# 
# LEF OUT 
# User Name : spalutla 
# Date : Tue Mar 31 10:02:19 2015
# 
VERSION 5.5 ;
NAMESCASESENSITIVE ON ;
BUSBITCHARS "[]" ;
DIVIDERCHAR "/" ;

UNITS
  DATABASE MICRONS 1000 ;
END UNITS
MANUFACTURINGGRID 0.001 ;

LAYER poly
  TYPE MASTERSLICE ;
END poly

LAYER tcn
  TYPE MASTERSLICE ;
END tcn

LAYER marker
  TYPE MASTERSLICE ;
END marker

LAYER ptpdrawn
  TYPE MASTERSLICE ;
END ptpdrawn

LAYER nwell
  TYPE MASTERSLICE ;
END nwell

LAYER nsddrawn
  TYPE MASTERSLICE ;
END nsddrawn

LAYER psddrawn
  TYPE MASTERSLICE ;
END psddrawn

LAYER resdrawn
  TYPE MASTERSLICE ;
END resdrawn

LAYER nwellesddrawn
  TYPE MASTERSLICE ;
END nwellesddrawn

LAYER deepnwelldrawn
  TYPE MASTERSLICE ;
END deepnwelldrawn

LAYER tgoxiddrawn
  TYPE MASTERSLICE ;
END tgoxiddrawn

LAYER esddrawn
  TYPE MASTERSLICE ;
END esddrawn

LAYER mresistordrawn
  TYPE MASTERSLICE ;
END mresistordrawn

LAYER ulndrawn
  TYPE MASTERSLICE ;
END ulndrawn

LAYER ulpdrawn
  TYPE MASTERSLICE ;
END ulpdrawn

LAYER llndrawn
  TYPE MASTERSLICE ;
END llndrawn

LAYER llpdrawn
  TYPE MASTERSLICE ;
END llpdrawn

LAYER via10drawn
  TYPE MASTERSLICE ;
END via10drawn

LAYER dummy54
  TYPE MASTERSLICE ;
END dummy54

LAYER via11drawn
  TYPE MASTERSLICE ;
END via11drawn

LAYER metal11drawn
  TYPE MASTERSLICE ;
END metal11drawn

LAYER noprot
  TYPE MASTERSLICE ;
END noprot

LAYER tv2drawn
  TYPE MASTERSLICE ;
END tv2drawn

LAYER tm2drawn
  TYPE MASTERSLICE ;
END tm2drawn

LAYER txrdrawn
  TYPE MASTERSLICE ;
END txrdrawn

LAYER m1pgdrawn
  TYPE MASTERSLICE ;
END m1pgdrawn

LAYER m2pgdrawn
  TYPE MASTERSLICE ;
END m2pgdrawn

LAYER m3pgdrawn
  TYPE MASTERSLICE ;
END m3pgdrawn

LAYER ce3drawn
  TYPE MASTERSLICE ;
END ce3drawn

LAYER dummy81
  TYPE MASTERSLICE ;
END dummy81

LAYER sram_iddrawn
  TYPE MASTERSLICE ;
END sram_iddrawn

LAYER dummy83
  TYPE MASTERSLICE ;
END dummy83

LAYER polycheckdrawn
  TYPE MASTERSLICE ;
END polycheckdrawn

LAYER prmdrawn
  TYPE MASTERSLICE ;
END prmdrawn

LAYER rctdrawn
  TYPE MASTERSLICE ;
END rctdrawn

LAYER cptdrawn
  TYPE MASTERSLICE ;
END cptdrawn

LAYER cobdrawn
  TYPE MASTERSLICE ;
END cobdrawn

LAYER cbpdrawn
  TYPE MASTERSLICE ;
END cbpdrawn

LAYER ce2
  TYPE MASTERSLICE ;
END ce2

LAYER ce1
  TYPE MASTERSLICE ;
END ce1

LAYER cbvdrawn
  TYPE MASTERSLICE ;
END cbvdrawn

LAYER nv1drawn
  TYPE MASTERSLICE ;
END nv1drawn

LAYER pv1drawn
  TYPE MASTERSLICE ;
END pv1drawn

LAYER nv2drawn
  TYPE MASTERSLICE ;
END nv2drawn

LAYER pv2drawn
  TYPE MASTERSLICE ;
END pv2drawn

LAYER pv3drawn
  TYPE MASTERSLICE ;
END pv3drawn

LAYER nv3drawn
  TYPE MASTERSLICE ;
END nv3drawn

LAYER tnwdrawn
  TYPE MASTERSLICE ;
END tnwdrawn

LAYER tpwdrawn
  TYPE MASTERSLICE ;
END tpwdrawn

LAYER diffusiondrawn
  TYPE MASTERSLICE ;
END diffusiondrawn

LAYER pwelldrawn
  TYPE MASTERSLICE ;
END pwelldrawn

LAYER metalc1drawn
  TYPE MASTERSLICE ;
END metalc1drawn

LAYER metalc2drawn
  TYPE MASTERSLICE ;
END metalc2drawn

LAYER metalc3drawn
  TYPE MASTERSLICE ;
END metalc3drawn

LAYER metalc4drawn
  TYPE MASTERSLICE ;
END metalc4drawn

LAYER metalc5drawn
  TYPE MASTERSLICE ;
END metalc5drawn

LAYER dummy126
  TYPE MASTERSLICE ;
END dummy126

LAYER tntdrawn
  TYPE MASTERSLICE ;
END tntdrawn

LAYER tptdrawn
  TYPE MASTERSLICE ;
END tptdrawn

LAYER nu1drawn
  TYPE MASTERSLICE ;
END nu1drawn

LAYER pu1drawn
  TYPE MASTERSLICE ;
END pu1drawn

LAYER thxdrawn
  TYPE MASTERSLICE ;
END thxdrawn

LAYER xntdrawn
  TYPE MASTERSLICE ;
END xntdrawn

LAYER xptdrawn
  TYPE MASTERSLICE ;
END xptdrawn

LAYER xhxdrawn
  TYPE MASTERSLICE ;
END xhxdrawn

LAYER ulldrawn
  TYPE MASTERSLICE ;
END ulldrawn

LAYER naldrawn
  TYPE MASTERSLICE ;
END naldrawn

LAYER paldrawn
  TYPE MASTERSLICE ;
END paldrawn

LAYER dvndrawn
  TYPE MASTERSLICE ;
END dvndrawn

LAYER bgddrawn
  TYPE MASTERSLICE ;
END bgddrawn

LAYER dvpdrawn
  TYPE MASTERSLICE ;
END dvpdrawn

LAYER hvgdrawn
  TYPE MASTERSLICE ;
END hvgdrawn

LAYER dmgdrawn
  TYPE MASTERSLICE ;
END dmgdrawn

LAYER nmgdrawn
  TYPE MASTERSLICE ;
END nmgdrawn

LAYER pmgdrawn
  TYPE MASTERSLICE ;
END pmgdrawn

LAYER svndrawn
  TYPE MASTERSLICE ;
END svndrawn

LAYER svpdrawn
  TYPE MASTERSLICE ;
END svpdrawn

LAYER nesdrawn
  TYPE MASTERSLICE ;
END nesdrawn

LAYER doxdrawn
  TYPE MASTERSLICE ;
END doxdrawn

LAYER evndrawn
  TYPE MASTERSLICE ;
END evndrawn

LAYER tcalignmentdrawn
  TYPE MASTERSLICE ;
END tcalignmentdrawn

LAYER reidrawn
  TYPE MASTERSLICE ;
END reidrawn

LAYER xvndrawn
  TYPE MASTERSLICE ;
END xvndrawn

LAYER ag3drawn
  TYPE MASTERSLICE ;
END ag3drawn

LAYER tcnpdrawn
  TYPE MASTERSLICE ;
END tcnpdrawn

LAYER pladrawn
  TYPE MASTERSLICE ;
END pladrawn

LAYER c4tdrawn
  TYPE MASTERSLICE ;
END c4tdrawn

LAYER c4edrawn
  TYPE MASTERSLICE ;
END c4edrawn

LAYER zerothdrawn
  TYPE MASTERSLICE ;
END zerothdrawn

LAYER raddrawn
  TYPE MASTERSLICE ;
END raddrawn

LAYER ag2drawn
  TYPE MASTERSLICE ;
END ag2drawn

LAYER ag5drawn
  TYPE MASTERSLICE ;
END ag5drawn

LAYER gcn
  TYPE MASTERSLICE ;
END gcn

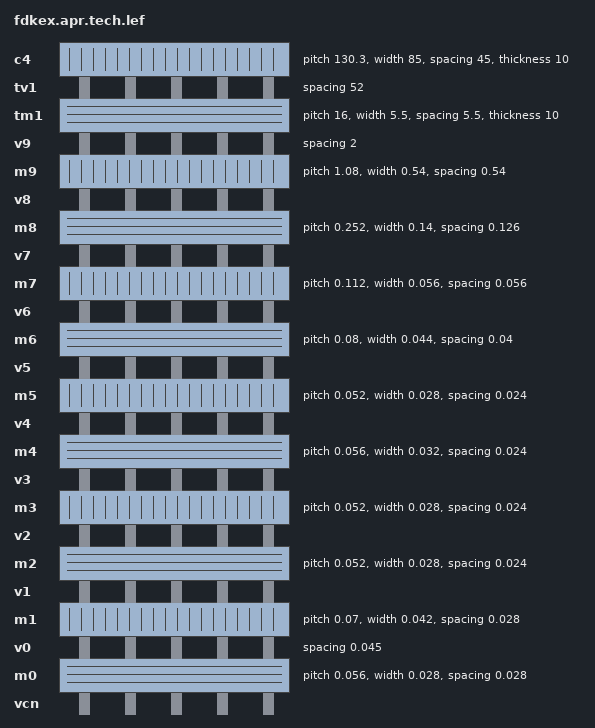
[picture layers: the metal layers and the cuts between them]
LAYER vcn
  TYPE CUT ;
END vcn

LAYER m0
  TYPE ROUTING ;
  DIRECTION HORIZONTAL ;
  PITCH 0.056 ;
  WIDTH 0.028 ;
  SPACING 0.028 ;
  MINWIDTH 0.028 ;
  CAPMULTIPLIER 1 ;
END m0

LAYER v0
  TYPE CUT ;
  SPACING 0.045 ADJACENTCUTS 3 WITHIN 0.045 ;
END v0

LAYER m1
  TYPE ROUTING ;
  DIRECTION VERTICAL ;
  PITCH 0.07 ;
  WIDTH 0.042 ;
  SPACING 0.028 ;
  MINWIDTH 0.042 ;
  CAPMULTIPLIER 1 ;
END m1

LAYER v1
  TYPE CUT ;
END v1

LAYER m2
  TYPE ROUTING ;
  DIRECTION HORIZONTAL ;
  PITCH 0.052 ;
  WIDTH 0.028 ;
  SPACING 0.024 ;
  MINWIDTH 0.028 ;
  CAPMULTIPLIER 1 ;
END m2

LAYER v2
  TYPE CUT ;
END v2

LAYER m3
  TYPE ROUTING ;
  DIRECTION VERTICAL ;
  PITCH 0.052 ;
  WIDTH 0.028 ;
  SPACING 0.024 ;
  MINWIDTH 0.028 ;
  CAPMULTIPLIER 1 ;
END m3

LAYER v3
  TYPE CUT ;
END v3

LAYER m4
  TYPE ROUTING ;
  DIRECTION HORIZONTAL ;
  PITCH 0.056 ;
  WIDTH 0.032 ;
  SPACING 0.024 ;
  MINWIDTH 0.028 ;
  CAPMULTIPLIER 1 ;
END m4

LAYER v4
  TYPE CUT ;
END v4

LAYER m5
  TYPE ROUTING ;
  DIRECTION VERTICAL ;
  PITCH 0.052 ;
  WIDTH 0.028 ;
  SPACING 0.024 ;
  MINWIDTH 0.028 ;
  CAPMULTIPLIER 1 ;
END m5

LAYER v5
  TYPE CUT ;
END v5

LAYER m6
  TYPE ROUTING ;
  DIRECTION HORIZONTAL ;
  PITCH 0.08 ;
  WIDTH 0.044 ;
  SPACING 0.04 ;
  MINWIDTH 0.04 ;
  CAPMULTIPLIER 1 ;
END m6

LAYER v6
  TYPE CUT ;
END v6

LAYER m7
  TYPE ROUTING ;
  DIRECTION VERTICAL ;
  PITCH 0.112 ;
  WIDTH 0.056 ;
  SPACING 0.056 ;
  MINWIDTH 0.056 ;
  CAPMULTIPLIER 1 ;
END m7

LAYER v7
  TYPE CUT ;
END v7

LAYER m8
  TYPE ROUTING ;
  DIRECTION HORIZONTAL ;
  PITCH 0.252 ;
  WIDTH 0.14 ;
  SPACING 0.126 ;
  MINWIDTH 0.126 ;
  CAPMULTIPLIER 1 ;
END m8

LAYER v8
  TYPE CUT ;
END v8

LAYER m9
  TYPE ROUTING ;
  DIRECTION VERTICAL ;
  PITCH 1.08 ;
  WIDTH 0.54 ;
  SPACING 0.54 ;
  MINWIDTH 0.54 ;
  MINENCLOSEDAREA 2.2 ;
  CAPMULTIPLIER 1 ;
END m9

LAYER v9
  TYPE CUT ;
  SPACING 2 ;
END v9

LAYER tm1
  TYPE ROUTING ;
  DIRECTION HORIZONTAL ;
  PITCH 16 ;
  WIDTH 5.5 ;
  AREA 200 ;
  SPACING 5.5 ;
  MINWIDTH 5.5 ;
  MINENCLOSEDAREA 250 ;
  THICKNESS 10 ;
  CAPMULTIPLIER 1 ;
END tm1

LAYER tv1
  TYPE CUT ;
  SPACING 52 ;
END tv1

LAYER c4
  TYPE ROUTING ;
  DIRECTION VERTICAL ;
  PITCH 130.3 ;
  WIDTH 85 ;
  AREA 200 ;
  SPACING 45 ;
  MINWIDTH 85 ;
  THICKNESS 10 ;
  CAPMULTIPLIER 1 ;
END c4

LAYER OverlapCheck
  TYPE OVERLAP ;
END OverlapCheck
MAXVIASTACK 10 RANGE gcn c4 ;

VIA VCNAX
  DEFAULT 
  RESISTANCE 5.72 ;
  LAYER gcn ;
    RECT -0.0270 -0.0160 0.0270 0.0160 ;
  LAYER vcn ;
    RECT -0.0210 -0.0140 0.0210 0.0140 ;
  LAYER m0 ;
    RECT -0.0430 -0.0140 0.0430 0.0140 ;
END VCNAX

VIA VIA0AX
  DEFAULT 
  RESISTANCE 5.72 ;
  LAYER m0 ;
    RECT -0.0350 -0.0140 0.0350 0.0140 ;
  LAYER v0 ;
    RECT -0.0210 -0.0140 0.0210 0.0140 ;
  LAYER m1 ;
    RECT -0.0210 -0.0280 0.0210 0.0280 ;
END VIA0AX

VIA VCNB
  RESISTANCE 5.72 ;
  LAYER gcn ;
    RECT -0.0270 -0.0160 0.0270 0.0160 ;
  LAYER vcn ;
    RECT -0.0210 -0.0230 0.0210 0.0230 ;
  LAYER m0 ;
    RECT -0.0430 -0.0230 0.0430 0.0230 ;
END VCNB

VIA VIA0CX
  RESISTANCE 5.72 ;
  LAYER m0 ;
    RECT -0.0350 -0.0200 0.0350 0.0200 ;
  LAYER v0 ;
    RECT -0.0210 -0.0200 0.0210 0.0200 ;
  LAYER m1 ;
    RECT -0.0210 -0.0340 0.0210 0.0340 ;
END VIA0CX

VIA VIA1A
  DEFAULT 
  RESISTANCE 5.72 ;
  LAYER m1 ;
    RECT -0.0210 -0.0210 0.0210 0.0210 ;
  LAYER v1 ;
    RECT -0.0180 -0.0140 0.0180 0.0140 ;
  LAYER m2 ;
    RECT -0.0420 -0.0140 0.0420 0.0140 ;
END VIA1A

VIA VIA1F
  RESISTANCE 5.72 ;
  LAYER m1 ;
    RECT -0.0210 -0.0270 0.0210 0.0270 ;
  LAYER v1 ;
    RECT -0.0180 -0.0200 0.0180 0.0200 ;
  LAYER m2 ;
    RECT -0.0420 -0.0200 0.0420 0.0200 ;
END VIA1F

VIA VIA1V
  RESISTANCE 5.72 ;
  LAYER m1 ;
    RECT -0.0210 -0.0440 0.0210 0.0440 ;
  LAYER v1 ;
    RECT -0.0180 -0.0370 0.0180 0.0370 ;
  LAYER m2 ;
    RECT -0.0420 -0.0370 0.0420 0.0370 ;
END VIA1V

VIA VIA0A
  RESISTANCE 5.72 ;
  LAYER m0 ;
    RECT -0.0350 -0.0210 0.0350 0.0210 ;
  LAYER v0 ;
    RECT -0.0210 -0.0210 0.0210 0.0210 ;
  LAYER m1 ;
    RECT -0.0210 -0.0350 0.0210 0.0350 ;
END VIA0A

VIA VIA0B
  RESISTANCE 5.72 ;
  LAYER m0 ;
    RECT -0.0350 -0.0230 0.0350 0.0230 ;
  LAYER v0 ;
    RECT -0.0210 -0.0230 0.0210 0.0230 ;
  LAYER m1 ;
    RECT -0.0210 -0.0370 0.0210 0.0370 ;
END VIA0B

VIA VIA2B
  RESISTANCE 5.72 ;
  LAYER m2 ;
    RECT -0.0240 -0.0140 0.0240 0.0140 ;
  LAYER v2 ;
    RECT -0.0150 -0.0160 0.0150 0.0160 ;
  LAYER m3 ;
    RECT -0.0150 -0.0400 0.0150 0.0400 ;
END VIA2B

VIA VIA2F
  RESISTANCE 5.72 ;
  LAYER m2 ;
    RECT -0.0290 -0.0140 0.0290 0.0140 ;
  LAYER v2 ;
    RECT -0.0200 -0.0160 0.0200 0.0160 ;
  LAYER m3 ;
    RECT -0.0200 -0.0400 0.0200 0.0400 ;
END VIA2F

VIA VIA3B
  RESISTANCE 5.72 ;
  LAYER m3 ;
    RECT -0.0140 -0.0240 0.0140 0.0240 ;
  LAYER v3 ;
    RECT -0.0160 -0.0150 0.0160 0.0150 ;
  LAYER m4 ;
    RECT -0.0400 -0.0150 0.0400 0.0150 ;
END VIA3B

VIA VIA4B
  RESISTANCE 5.72 ;
  LAYER m4 ;
    RECT -0.0240 -0.0140 0.0240 0.0140 ;
  LAYER v4 ;
    RECT -0.0150 -0.0160 0.0150 0.0160 ;
  LAYER m5 ;
    RECT -0.0150 -0.0400 0.0150 0.0400 ;
END VIA4B

VIA VIA4F
  RESISTANCE 5.72 ;
  LAYER m4 ;
    RECT -0.0290 -0.0140 0.0290 0.0140 ;
  LAYER v4 ;
    RECT -0.0200 -0.0160 0.0200 0.0160 ;
  LAYER m5 ;
    RECT -0.0200 -0.0400 0.0200 0.0400 ;
END VIA4F

VIA VIA8A
  DEFAULT 
  RESISTANCE 5.72 ;
  LAYER m8 ;
    RECT -0.3500 -0.3500 0.3500 0.3500 ;
  LAYER v8 ;
    RECT -0.2200 -0.2200 0.2200 0.2200 ;
  LAYER m9 ;
    RECT -0.2700 -0.3500 0.2700 0.3500 ;
END VIA8A

VIA VIA8C
  RESISTANCE 5.72 ;
  LAYER m8 ;
    RECT -0.5200 -0.3000 0.5200 0.3000 ;
  LAYER v8 ;
    RECT -0.4400 -0.2200 0.4400 0.2200 ;
  LAYER m9 ;
    RECT -0.4900 -0.3500 0.4900 0.3500 ;
END VIA8C

VIA VIA2A
  DEFAULT 
  RESISTANCE 5.72 ;
  LAYER m2 ;
    RECT -0.0230 -0.0140 0.0230 0.0140 ;
  LAYER v2 ;
    RECT -0.0140 -0.0160 0.0140 0.0160 ;
  LAYER m3 ;
    RECT -0.0140 -0.0400 0.0140 0.0400 ;
END VIA2A

VIA VIA2L40
  RESISTANCE 5.72 ;
  LAYER m2 ;
    RECT -0.0430 -0.0200 0.0430 0.0200 ;
  LAYER v2 ;
    RECT -0.0340 -0.0160 0.0340 0.0160 ;
  LAYER m3 ;
    RECT -0.0340 -0.0400 0.0340 0.0400 ;
END VIA2L40

VIA VIA2L74
  RESISTANCE 5.72 ;
  LAYER m2 ;
    RECT -0.0430 -0.0370 0.0430 0.0370 ;
  LAYER v2 ;
    RECT -0.0340 -0.0160 0.0340 0.0160 ;
  LAYER m3 ;
    RECT -0.0340 -0.0400 0.0340 0.0400 ;
END VIA2L74

VIA VIA9A
  DEFAULT 
  RESISTANCE 5.72 ;
  LAYER m9 ;
    RECT -0.5400 -1.0650 0.5400 1.0650 ;
  LAYER v9 ;
    RECT -0.4000 -0.9250 0.4000 0.9250 ;
  LAYER tm1 ;
    RECT -3.4000 -3.9250 3.4000 3.9250 ;
END VIA9A

VIA VIA9B
  RESISTANCE 5.72 ;
  LAYER m9 ;
    RECT -0.5400 -3.8400 0.5400 3.8400 ;
  LAYER v9 ;
    RECT -0.4000 -3.7000 0.4000 3.7000 ;
  LAYER tm1 ;
    RECT -3.4000 -6.7000 3.4000 6.7000 ;
END VIA9B

VIA VIA9C
  RESISTANCE 5.72 ;
  LAYER m9 ;
    RECT -0.5400 -1.9900 0.5400 1.9900 ;
  LAYER v9 ;
    RECT -0.4000 -1.8500 0.4000 1.8500 ;
  LAYER tm1 ;
    RECT -3.4000 -4.8500 3.4000 4.8500 ;
END VIA9C

VIA VIA2S
  RESISTANCE 5.72 ;
  LAYER m2 ;
    RECT -0.0470 -0.0140 0.0470 0.0140 ;
  LAYER v2 ;
    RECT -0.0380 -0.0160 0.0380 0.0160 ;
  LAYER m3 ;
    RECT -0.0380 -0.0400 0.0380 0.0400 ;
END VIA2S

VIA VIA3A
  RESISTANCE 5.72 ;
  LAYER m3 ;
    RECT -0.0140 -0.0230 0.0140 0.0230 ;
  LAYER v3 ;
    RECT -0.0160 -0.0140 0.0160 0.0140 ;
  LAYER m4 ;
    RECT -0.0400 -0.0140 0.0400 0.0140 ;
END VIA3A

VIA VIA3F
  RESISTANCE 5.72 ;
  LAYER m3 ;
    RECT -0.0140 -0.0290 0.0140 0.0290 ;
  LAYER v3 ;
    RECT -0.0160 -0.0200 0.0160 0.0200 ;
  LAYER m4 ;
    RECT -0.0400 -0.0200 0.0400 0.0200 ;
END VIA3F

VIA VIA3RY
  RESISTANCE 5.72 ;
  LAYER m3 ;
    RECT -0.0340 -0.0390 0.0340 0.0390 ;
  LAYER v3 ;
    RECT -0.0220 -0.0300 0.0220 0.0300 ;
  LAYER m4 ;
    RECT -0.0460 -0.0300 0.0460 0.0300 ;
END VIA3RY

VIA VIA3VX
  RESISTANCE 5.72 ;
  LAYER m3 ;
    RECT -0.0340 -0.0420 0.0340 0.0420 ;
  LAYER v3 ;
    RECT -0.0200 -0.0330 0.0200 0.0330 ;
  LAYER m4 ;
    RECT -0.0440 -0.0330 0.0440 0.0330 ;
END VIA3VX

VIA VIA3NX
  RESISTANCE 5.72 ;
  LAYER m3 ;
    RECT -0.0340 -0.0460 0.0340 0.0460 ;
  LAYER v3 ;
    RECT -0.0190 -0.0370 0.0190 0.0370 ;
  LAYER m4 ;
    RECT -0.0430 -0.0370 0.0430 0.0370 ;
END VIA3NX

VIA VIA4A
  DEFAULT 
  RESISTANCE 5.72 ;
  LAYER m4 ;
    RECT -0.0230 -0.0140 0.0230 0.0140 ;
  LAYER v4 ;
    RECT -0.0140 -0.0160 0.0140 0.0160 ;
  LAYER m5 ;
    RECT -0.0140 -0.0400 0.0140 0.0400 ;
END VIA4A

VIA VIA4L40
  RESISTANCE 5.72 ;
  LAYER m4 ;
    RECT -0.0430 -0.0200 0.0430 0.0200 ;
  LAYER v4 ;
    RECT -0.0340 -0.0160 0.0340 0.0160 ;
  LAYER m5 ;
    RECT -0.0340 -0.0400 0.0340 0.0400 ;
END VIA4L40

VIA VIA4L60
  RESISTANCE 5.72 ;
  LAYER m4 ;
    RECT -0.0430 -0.0300 0.0430 0.0300 ;
  LAYER v4 ;
    RECT -0.0340 -0.0160 0.0340 0.0160 ;
  LAYER m5 ;
    RECT -0.0340 -0.0400 0.0340 0.0400 ;
END VIA4L60

VIA VIA4L66
  RESISTANCE 5.72 ;
  LAYER m4 ;
    RECT -0.0430 -0.0330 0.0430 0.0330 ;
  LAYER v4 ;
    RECT -0.0340 -0.0160 0.0340 0.0160 ;
  LAYER m5 ;
    RECT -0.0340 -0.0400 0.0340 0.0400 ;
END VIA4L66

VIA VIA4L74
  RESISTANCE 5.72 ;
  LAYER m4 ;
    RECT -0.0430 -0.0370 0.0430 0.0370 ;
  LAYER v4 ;
    RECT -0.0340 -0.0160 0.0340 0.0160 ;
  LAYER m5 ;
    RECT -0.0340 -0.0400 0.0340 0.0400 ;
END VIA4L74

VIA VIA3GX
  RESISTANCE 5.72 ;
  LAYER m3 ;
    RECT -0.0240 -0.0320 0.0240 0.0320 ;
  LAYER v3 ;
    RECT -0.0260 -0.0230 0.0260 0.0230 ;
  LAYER m4 ;
    RECT -0.0500 -0.0230 0.0500 0.0230 ;
END VIA3GX

VIA VIA5A
  RESISTANCE 5.72 ;
  LAYER m5 ;
    RECT -0.0140 -0.0320 0.0140 0.0320 ;
  LAYER v5 ;
    RECT -0.0160 -0.0200 0.0160 0.0200 ;
  LAYER m6 ;
    RECT -0.0380 -0.0200 0.0380 0.0200 ;
END VIA5A

VIA VIA5B
  DEFAULT 
  RESISTANCE 5.72 ;
  LAYER m5 ;
    RECT -0.0140 -0.0340 0.0140 0.0340 ;
  LAYER v5 ;
    RECT -0.0160 -0.0220 0.0160 0.0220 ;
  LAYER m6 ;
    RECT -0.0380 -0.0220 0.0380 0.0220 ;
END VIA5B

VIA VIA4S
  RESISTANCE 5.72 ;
  LAYER m4 ;
    RECT -0.0470 -0.0140 0.0470 0.0140 ;
  LAYER v4 ;
    RECT -0.0380 -0.0160 0.0380 0.0160 ;
  LAYER m5 ;
    RECT -0.0380 -0.0400 0.0380 0.0400 ;
END VIA4S

VIA VIA5A_30
  RESISTANCE 5.72 ;
  LAYER m5 ;
    RECT -0.0150 -0.0320 0.0150 0.0320 ;
  LAYER v5 ;
    RECT -0.0160 -0.0200 0.0160 0.0200 ;
  LAYER m6 ;
    RECT -0.0380 -0.0200 0.0380 0.0200 ;
END VIA5A_30

VIA VIA5V
  RESISTANCE 5.72 ;
  LAYER m5 ;
    RECT -0.0220 -0.0570 0.0220 0.0570 ;
  LAYER v5 ;
    RECT -0.0240 -0.0450 0.0240 0.0450 ;
  LAYER m6 ;
    RECT -0.0460 -0.0450 0.0460 0.0450 ;
END VIA5V

VIA VIA3RX
  RESISTANCE 5.72 ;
  LAYER m3 ;
    RECT -0.0200 -0.0390 0.0200 0.0390 ;
  LAYER v3 ;
    RECT -0.0190 -0.0300 0.0190 0.0300 ;
  LAYER m4 ;
    RECT -0.0430 -0.0300 0.0430 0.0300 ;
END VIA3RX

VIA VIA5R
  RESISTANCE 5.72 ;
  LAYER m5 ;
    RECT -0.0140 -0.0570 0.0140 0.0570 ;
  LAYER v5 ;
    RECT -0.0160 -0.0450 0.0160 0.0450 ;
  LAYER m6 ;
    RECT -0.0380 -0.0450 0.0380 0.0450 ;
END VIA5R

VIA VIA6A40
  RESISTANCE 5.72 ;
  LAYER m6 ;
    RECT -0.0440 -0.0200 0.0440 0.0200 ;
  LAYER v6 ;
    RECT -0.0280 -0.0300 0.0280 0.0300 ;
  LAYER m7 ;
    RECT -0.0280 -0.0620 0.0280 0.0620 ;
END VIA6A40

VIA VIA6A44
  DEFAULT 
  RESISTANCE 5.72 ;
  LAYER m6 ;
    RECT -0.0440 -0.0220 0.0440 0.0220 ;
  LAYER v6 ;
    RECT -0.0280 -0.0300 0.0280 0.0300 ;
  LAYER m7 ;
    RECT -0.0280 -0.0620 0.0280 0.0620 ;
END VIA6A44

VIA VIA6F
  RESISTANCE 5.72 ;
  LAYER m6 ;
    RECT -0.1000 -0.0450 0.1000 0.0450 ;
  LAYER v6 ;
    RECT -0.0840 -0.0300 0.0840 0.0300 ;
  LAYER m7 ;
    RECT -0.0840 -0.0620 0.0840 0.0620 ;
END VIA6F

VIA VIA5RP
  RESISTANCE 5.72 ;
  LAYER m5 ;
    RECT -0.0200 -0.0570 0.0200 0.0570 ;
  LAYER v5 ;
    RECT -0.0220 -0.0450 0.0220 0.0450 ;
  LAYER m6 ;
    RECT -0.0440 -0.0450 0.0440 0.0450 ;
END VIA5RP

VIA VIA5W
  RESISTANCE 5.72 ;
  LAYER m5 ;
    RECT -0.0320 -0.0340 0.0320 0.0340 ;
  LAYER v5 ;
    RECT -0.0340 -0.0220 0.0340 0.0220 ;
  LAYER m6 ;
    RECT -0.0560 -0.0220 0.0560 0.0220 ;
END VIA5W

VIA VIA7E
  RESISTANCE 5.72 ;
  LAYER m7 ;
    RECT -0.0330 -0.1890 0.0330 0.1890 ;
  LAYER v7 ;
    RECT -0.0420 -0.0630 0.0420 0.0630 ;
  LAYER m8 ;
    RECT -0.0700 -0.0910 0.0700 0.0910 ;
END VIA7E

VIA VIA4J
  RESISTANCE 5.72 ;
  LAYER m4 ;
    RECT -0.0370 -0.0140 0.0370 0.0140 ;
  LAYER v4 ;
    RECT -0.0280 -0.0160 0.0280 0.0160 ;
  LAYER m5 ;
    RECT -0.0280 -0.0400 0.0280 0.0400 ;
END VIA4J

VIA VIA7A
  RESISTANCE 5.72 ;
  LAYER m7 ;
    RECT -0.0280 -0.0910 0.0280 0.0910 ;
  LAYER v7 ;
    RECT -0.0370 -0.0630 0.0370 0.0630 ;
  LAYER m8 ;
    RECT -0.0650 -0.0630 0.0650 0.0630 ;
END VIA7A

VIA VIA7D
  RESISTANCE 5.72 ;
  LAYER m7 ;
    RECT -0.0810 -0.0910 0.0810 0.0910 ;
  LAYER v7 ;
    RECT -0.0900 -0.0630 0.0900 0.0630 ;
  LAYER m8 ;
    RECT -0.1180 -0.0630 0.1180 0.0630 ;
END VIA7D

VIA VIA3G
  RESISTANCE 5.72 ;
  LAYER m3 ;
    RECT -0.0140 -0.0320 0.0140 0.0320 ;
  LAYER v3 ;
    RECT -0.0160 -0.0230 0.0160 0.0230 ;
  LAYER m4 ;
    RECT -0.0400 -0.0230 0.0400 0.0230 ;
END VIA3G

VIA VIA2JX
  RESISTANCE 5.72 ;
  LAYER m2 ;
    RECT -0.0370 -0.0210 0.0370 0.0210 ;
  LAYER v2 ;
    RECT -0.0280 -0.0230 0.0280 0.0230 ;
  LAYER m3 ;
    RECT -0.0280 -0.0470 0.0280 0.0470 ;
END VIA2JX

VIA VIA2R
  RESISTANCE 5.72 ;
  LAYER m2 ;
    RECT -0.0390 -0.0140 0.0390 0.0140 ;
  LAYER v2 ;
    RECT -0.0300 -0.0160 0.0300 0.0160 ;
  LAYER m3 ;
    RECT -0.0300 -0.0400 0.0300 0.0400 ;
END VIA2R

VIA VIA2RX
  RESISTANCE 5.72 ;
  LAYER m2 ;
    RECT -0.0390 -0.0210 0.0390 0.0210 ;
  LAYER v2 ;
    RECT -0.0300 -0.0190 0.0300 0.0190 ;
  LAYER m3 ;
    RECT -0.0300 -0.0430 0.0300 0.0430 ;
END VIA2RX

VIA VIA2RY
  RESISTANCE 5.72 ;
  LAYER m2 ;
    RECT -0.0390 -0.0200 0.0390 0.0200 ;
  LAYER v2 ;
    RECT -0.0300 -0.0220 0.0300 0.0220 ;
  LAYER m3 ;
    RECT -0.0300 -0.0460 0.0300 0.0460 ;
END VIA2RY

VIA VIA4JX
  RESISTANCE 5.72 ;
  LAYER m4 ;
    RECT -0.0370 -0.0200 0.0370 0.0200 ;
  LAYER v4 ;
    RECT -0.0280 -0.0230 0.0280 0.0230 ;
  LAYER m5 ;
    RECT -0.0280 -0.0470 0.0280 0.0470 ;
END VIA4JX

VIA VIA4R
  RESISTANCE 5.72 ;
  LAYER m4 ;
    RECT -0.0390 -0.0140 0.0390 0.0140 ;
  LAYER v4 ;
    RECT -0.0300 -0.0160 0.0300 0.0160 ;
  LAYER m5 ;
    RECT -0.0300 -0.0400 0.0300 0.0400 ;
END VIA4R

VIA VIA4RY
  RESISTANCE 5.72 ;
  LAYER m4 ;
    RECT -0.0390 -0.0200 0.0390 0.0200 ;
  LAYER v4 ;
    RECT -0.0300 -0.0220 0.0300 0.0220 ;
  LAYER m5 ;
    RECT -0.0300 -0.0460 0.0300 0.0460 ;
END VIA4RY

VIA VIA3A_30
  RESISTANCE 5.72 ;
  LAYER m3 ;
    RECT -0.0150 -0.0230 0.0150 0.0230 ;
  LAYER v3 ;
    RECT -0.0160 -0.0140 0.0160 0.0140 ;
  LAYER m4 ;
    RECT -0.0400 -0.0140 0.0400 0.0140 ;
END VIA3A_30

VIA VIA3A_40
  RESISTANCE 5.72 ;
  LAYER m3 ;
    RECT -0.0200 -0.0230 0.0200 0.0230 ;
  LAYER v3 ;
    RECT -0.0160 -0.0140 0.0160 0.0140 ;
  LAYER m4 ;
    RECT -0.0400 -0.0140 0.0400 0.0140 ;
END VIA3A_40

VIA VIA5B_44
  RESISTANCE 5.72 ;
  LAYER m5 ;
    RECT -0.0160 -0.0340 0.0160 0.0340 ;
  LAYER v5 ;
    RECT -0.0160 -0.0220 0.0160 0.0220 ;
  LAYER m6 ;
    RECT -0.0380 -0.0220 0.0380 0.0220 ;
END VIA5B_44

VIA VIA5A_40
  RESISTANCE 5.72 ;
  LAYER m5 ;
    RECT -0.0200 -0.0320 0.0200 0.0320 ;
  LAYER v5 ;
    RECT -0.0160 -0.0200 0.0160 0.0200 ;
  LAYER m6 ;
    RECT -0.0380 -0.0200 0.0380 0.0200 ;
END VIA5A_40

VIA VIA4F_30
  RESISTANCE 5.72 ;
  LAYER m4 ;
    RECT -0.0290 -0.0150 0.0290 0.0150 ;
  LAYER v4 ;
    RECT -0.0200 -0.0160 0.0200 0.0160 ;
  LAYER m5 ;
    RECT -0.0200 -0.0400 0.0200 0.0400 ;
END VIA4F_30

VIA VIA4B_30
  RESISTANCE 5.72 ;
  LAYER m4 ;
    RECT -0.0240 -0.0150 0.0240 0.0150 ;
  LAYER v4 ;
    RECT -0.0150 -0.0160 0.0150 0.0160 ;
  LAYER m5 ;
    RECT -0.0150 -0.0400 0.0150 0.0400 ;
END VIA4B_30

VIA VIA3B_30
  RESISTANCE 5.72 ;
  LAYER m3 ;
    RECT -0.0150 -0.0240 0.0150 0.0240 ;
  LAYER v3 ;
    RECT -0.0160 -0.0150 0.0160 0.0150 ;
  LAYER m4 ;
    RECT -0.0400 -0.0150 0.0400 0.0150 ;
END VIA3B_30

VIA VIA3B_40
  RESISTANCE 5.72 ;
  LAYER m3 ;
    RECT -0.0200 -0.0240 0.0200 0.0240 ;
  LAYER v3 ;
    RECT -0.0160 -0.0150 0.0160 0.0150 ;
  LAYER m4 ;
    RECT -0.0400 -0.0150 0.0400 0.0150 ;
END VIA3B_40

VIA VIA5B_4044
  RESISTANCE 5.72 ;
  LAYER m5 ;
    RECT -0.0200 -0.0340 0.0200 0.0340 ;
  LAYER v5 ;
    RECT -0.0160 -0.0220 0.0160 0.0220 ;
  LAYER m6 ;
    RECT -0.0380 -0.0220 0.0380 0.0220 ;
END VIA5B_4044

VIA VIA4A_30
  RESISTANCE 5.72 ;
  LAYER m4 ;
    RECT -0.0230 -0.0150 0.0230 0.0150 ;
  LAYER v4 ;
    RECT -0.0140 -0.0160 0.0140 0.0160 ;
  LAYER m5 ;
    RECT -0.0140 -0.0400 0.0140 0.0400 ;
END VIA4A_30

VIA VIA5BP
  RESISTANCE 5.72 ;
  LAYER m5 ;
    RECT -0.0200 -0.0340 0.0200 0.0340 ;
  LAYER v5 ;
    RECT -0.0220 -0.0220 0.0220 0.0220 ;
  LAYER m6 ;
    RECT -0.0440 -0.0220 0.0440 0.0220 ;
END VIA5BP

VIA VIA5MP
  RESISTANCE 5.72 ;
  LAYER m5 ;
    RECT -0.0230 -0.0660 0.0230 0.0660 ;
  LAYER v5 ;
    RECT -0.0220 -0.0540 0.0220 0.0540 ;
  LAYER m6 ;
    RECT -0.0440 -0.0540 0.0440 0.0540 ;
END VIA5MP

VIA VIA4O
  RESISTANCE 5.72 ;
  LAYER m4 ;
    RECT -0.0510 -0.0140 0.0510 0.0140 ;
  LAYER v4 ;
    RECT -0.0420 -0.0160 0.0420 0.0160 ;
  LAYER m5 ;
    RECT -0.0420 -0.0400 0.0420 0.0400 ;
END VIA4O

VIA VIA2J
  RESISTANCE 5.72 ;
  LAYER m2 ;
    RECT -0.0370 -0.0140 0.0370 0.0140 ;
  LAYER v2 ;
    RECT -0.0280 -0.0160 0.0280 0.0160 ;
  LAYER m3 ;
    RECT -0.0280 -0.0400 0.0280 0.0400 ;
END VIA2J

VIA VIA3N
  RESISTANCE 5.72 ;
  LAYER m3 ;
    RECT -0.0140 -0.0420 0.0140 0.0420 ;
  LAYER v3 ;
    RECT -0.0160 -0.0330 0.0160 0.0330 ;
  LAYER m4 ;
    RECT -0.0400 -0.0330 0.0400 0.0330 ;
END VIA3N

VIA VIA2TIE68
  RESISTANCE 5.72 ;
  LAYER m2 ;
    RECT -0.0430 -0.0140 0.0430 0.0140 ;
  LAYER v2 ;
    RECT -0.0340 -0.0160 0.0340 0.0160 ;
  LAYER m3 ;
    RECT -0.0340 -0.0400 0.0340 0.0400 ;
END VIA2TIE68

VIA VIA2O
  RESISTANCE 5.72 ;
  LAYER m2 ;
    RECT -0.0510 -0.0140 0.0510 0.0140 ;
  LAYER v2 ;
    RECT -0.0420 -0.0160 0.0420 0.0160 ;
  LAYER m3 ;
    RECT -0.0420 -0.0400 0.0420 0.0400 ;
END VIA2O

VIA VIA3HL
  RESISTANCE 5.72 ;
  LAYER m3 ;
    RECT -0.0160 -0.0330 0.0160 0.0330 ;
  LAYER v3 ;
    RECT -0.0160 -0.0240 0.0160 0.0240 ;
  LAYER m4 ;
    RECT -0.0400 -0.0300 0.0400 0.0300 ;
END VIA3HL

VIA VIA4RX
  RESISTANCE 5.72 ;
  LAYER m4 ;
    RECT -0.0390 -0.0190 0.0390 0.0190 ;
  LAYER v4 ;
    RECT -0.0300 -0.0190 0.0300 0.0190 ;
  LAYER m5 ;
    RECT -0.0300 -0.0430 0.0300 0.0430 ;
END VIA4RX

VIA VIA7C
  RESISTANCE 5.72 ;
  LAYER m7 ;
    RECT -0.0540 -0.0910 0.0540 0.0910 ;
  LAYER v7 ;
    RECT -0.0630 -0.0630 0.0630 0.0630 ;
  LAYER m8 ;
    RECT -0.0910 -0.0630 0.0910 0.0630 ;
END VIA7C

VIA VIA2HL
  RESISTANCE 5.72 ;
  LAYER m2 ;
    RECT -0.0240 -0.0140 0.0240 0.0140 ;
  LAYER v2 ;
    RECT -0.0240 -0.0160 0.0240 0.0160 ;
  LAYER m3 ;
    RECT -0.0300 -0.0400 0.0300 0.0400 ;
END VIA2HL

VIA VIA3S
  RESISTANCE 5.72 ;
  LAYER m3 ;
    RECT -0.0140 -0.0470 0.0140 0.0470 ;
  LAYER v3 ;
    RECT -0.0160 -0.0380 0.0160 0.0380 ;
  LAYER m4 ;
    RECT -0.0400 -0.0380 0.0400 0.0380 ;
END VIA3S

VIA VIA3D
  RESISTANCE 5.72 ;
  LAYER m3 ;
    RECT -0.0140 -0.0270 0.0140 0.0270 ;
  LAYER v3 ;
    RECT -0.0160 -0.0180 0.0160 0.0180 ;
  LAYER m4 ;
    RECT -0.0400 -0.0180 0.0400 0.0180 ;
END VIA3D

VIA VIA5A_32
  RESISTANCE 5.72 ;
  LAYER m5 ;
    RECT -0.0160 -0.0320 0.0160 0.0320 ;
  LAYER v5 ;
    RECT -0.0160 -0.0200 0.0160 0.0200 ;
  LAYER m6 ;
    RECT -0.0380 -0.0200 0.0380 0.0200 ;
END VIA5A_32

VIA VIA2C
  RESISTANCE 5.72 ;
  LAYER m2 ;
    RECT -0.0250 -0.0140 0.0250 0.0140 ;
  LAYER v2 ;
    RECT -0.0160 -0.0160 0.0160 0.0160 ;
  LAYER m3 ;
    RECT -0.0160 -0.0400 0.0160 0.0400 ;
END VIA2C

VIA VIA4C
  RESISTANCE 5.72 ;
  LAYER m4 ;
    RECT -0.0250 -0.0160 0.0250 0.0160 ;
  LAYER v4 ;
    RECT -0.0160 -0.0160 0.0160 0.0160 ;
  LAYER m5 ;
    RECT -0.0160 -0.0400 0.0160 0.0400 ;
END VIA4C

VIA VIA3O
  RESISTANCE 5.72 ;
  LAYER m3 ;
    RECT -0.0140 -0.0510 0.0140 0.0510 ;
  LAYER v3 ;
    RECT -0.0160 -0.0420 0.0160 0.0420 ;
  LAYER m4 ;
    RECT -0.0400 -0.0420 0.0400 0.0420 ;
END VIA3O

VIA VIA3C
  RESISTANCE 5.72 ;
  LAYER m3 ;
    RECT -0.0160 -0.0250 0.0160 0.0250 ;
  LAYER v3 ;
    RECT -0.0160 -0.0160 0.0160 0.0160 ;
  LAYER m4 ;
    RECT -0.0400 -0.0160 0.0400 0.0160 ;
END VIA3C

VIA VIA3C_32
  DEFAULT 
  RESISTANCE 5.72 ;
  LAYER m3 ;
    RECT -0.0140 -0.0250 0.0140 0.0250 ;
  LAYER v3 ;
    RECT -0.0160 -0.0160 0.0160 0.0160 ;
  LAYER m4 ;
    RECT -0.0400 -0.0160 0.0400 0.0160 ;
END VIA3C_32

VIA VIA5FA
  RESISTANCE 5.72 ;
  LAYER m5 ;
    RECT -0.0140 -0.0660 0.0140 0.0660 ;
  LAYER v5 ;
    RECT -0.0160 -0.0540 0.0160 0.0540 ;
  LAYER m6 ;
    RECT -0.0380 -0.0540 0.0380 0.0540 ;
END VIA5FA

VIA VIA7F
  DEFAULT 
  RESISTANCE 5.72 ;
  LAYER m7 ;
    RECT -0.0280 -0.0980 0.0280 0.0980 ;
  LAYER v7 ;
    RECT -0.0370 -0.0700 0.0370 0.0700 ;
  LAYER m8 ;
    RECT -0.0650 -0.0700 0.0650 0.0700 ;
END VIA7F

VIA VIA3S_TIE
  RESISTANCE 5.72 ;
  LAYER m3 ;
    RECT -0.0160 -0.0470 0.0160 0.0470 ;
  LAYER v3 ;
    RECT -0.0160 -0.0380 0.0160 0.0380 ;
  LAYER m4 ;
    RECT -0.0400 -0.0380 0.0400 0.0380 ;
END VIA3S_TIE

VIA VIA3O_TIE
  RESISTANCE 5.72 ;
  LAYER m3 ;
    RECT -0.0160 -0.0510 0.0160 0.0510 ;
  LAYER v3 ;
    RECT -0.0160 -0.0420 0.0160 0.0420 ;
  LAYER m4 ;
    RECT -0.0400 -0.0420 0.0400 0.0420 ;
END VIA3O_TIE

VIA VIA4O_TIE
  RESISTANCE 5.72 ;
  LAYER m4 ;
    RECT -0.0510 -0.0160 0.0510 0.0160 ;
  LAYER v4 ;
    RECT -0.0420 -0.0160 0.0420 0.0160 ;
  LAYER m5 ;
    RECT -0.0420 -0.0400 0.0420 0.0400 ;
END VIA4O_TIE

VIA VIA6C
  RESISTANCE 5.72 ;
  LAYER m6 ;
    RECT -0.0580 -0.0200 0.0580 0.0200 ;
  LAYER v6 ;
    RECT -0.0420 -0.0300 0.0420 0.0300 ;
  LAYER m7 ;
    RECT -0.0420 -0.0620 0.0420 0.0620 ;
END VIA6C

VIA VIA6CX
  RESISTANCE 5.72 ;
  LAYER m6 ;
    RECT -0.0580 -0.0360 0.0580 0.0360 ;
  LAYER v6 ;
    RECT -0.0420 -0.0360 0.0420 0.0360 ;
  LAYER m7 ;
    RECT -0.0420 -0.0680 0.0420 0.0680 ;
END VIA6CX

VIA VIA0AY
  RESISTANCE 5.72 ;
  LAYER m0 ;
    RECT -0.0430 -0.0140 0.0430 0.0140 ;
  LAYER v0 ;
    RECT -0.0280 -0.0140 0.0280 0.0140 ;
  LAYER m1 ;
    RECT -0.0280 -0.0280 0.0280 0.0280 ;
END VIA0AY

VIA VIA7B
  RESISTANCE 5.72 ;
  LAYER m7 ;
    RECT -0.0280 -0.1330 0.0280 0.1330 ;
  LAYER v7 ;
    RECT -0.0370 -0.1050 0.0370 0.1050 ;
  LAYER m8 ;
    RECT -0.0650 -0.1050 0.0650 0.1050 ;
END VIA7B

VIA VIA7C_A
  RESISTANCE 5.72 ;
  LAYER m7 ;
    RECT -0.0540 -0.0910 0.0540 0.0910 ;
  LAYER v7 ;
    RECT -0.0630 -0.0630 0.0630 0.0630 ;
  LAYER m8 ;
    RECT -0.0910 -0.0630 0.0910 0.0630 ;
END VIA7C_A

VIA VIA0AX_XN
  RESISTANCE 5.72 ;
  LAYER m0 ;
    RECT -0.0350 -0.0140 0.0350 0.0140 ;
  LAYER v0 ;
    RECT -0.0210 -0.0140 0.0210 0.0140 ;
  LAYER m1 ;
    RECT -0.0280 -0.0280 0.0280 0.0280 ;
END VIA0AX_XN

VIA VIA0CX_XN
  RESISTANCE 5.72 ;
  LAYER m0 ;
    RECT -0.0350 -0.0200 0.0350 0.0200 ;
  LAYER v0 ;
    RECT -0.0210 -0.0200 0.0210 0.0200 ;
  LAYER m1 ;
    RECT -0.0280 -0.0340 0.0280 0.0340 ;
END VIA0CX_XN

VIA VIA0A_XN
  RESISTANCE 5.72 ;
  LAYER m0 ;
    RECT -0.0350 -0.0210 0.0350 0.0210 ;
  LAYER v0 ;
    RECT -0.0210 -0.0210 0.0210 0.0210 ;
  LAYER m1 ;
    RECT -0.0280 -0.0350 0.0280 0.0350 ;
END VIA0A_XN

VIA VIA1A_XN
  RESISTANCE 5.72 ;
  LAYER m1 ;
    RECT -0.0280 -0.0210 0.0280 0.0210 ;
  LAYER v1 ;
    RECT -0.0180 -0.0140 0.0180 0.0140 ;
  LAYER m2 ;
    RECT -0.0420 -0.0140 0.0420 0.0140 ;
END VIA1A_XN

VIA VIA1F_XN
  RESISTANCE 5.72 ;
  LAYER m1 ;
    RECT -0.0280 -0.0270 0.0280 0.0270 ;
  LAYER v1 ;
    RECT -0.0180 -0.0200 0.0180 0.0200 ;
  LAYER m2 ;
    RECT -0.0420 -0.0200 0.0420 0.0200 ;
END VIA1F_XN

VIA VIA3RX_TIE_28
  RESISTANCE 5.72 ;
  LAYER m3 ;
    RECT -0.0140 -0.0390 0.0140 0.0390 ;
  LAYER v3 ;
    RECT -0.0190 -0.0300 0.0190 0.0300 ;
  LAYER m4 ;
    RECT -0.0430 -0.0300 0.0430 0.0300 ;
END VIA3RX_TIE_28

VIA VIA3RX_TIE_32
  RESISTANCE 5.72 ;
  LAYER m3 ;
    RECT -0.0160 -0.0390 0.0160 0.0390 ;
  LAYER v3 ;
    RECT -0.0190 -0.0300 0.0190 0.0300 ;
  LAYER m4 ;
    RECT -0.0430 -0.0300 0.0430 0.0300 ;
END VIA3RX_TIE_32

VIA VIA0BW
  RESISTANCE 5.72 ;
  LAYER m0 ;
    RECT -0.0420 -0.0230 0.0420 0.0230 ;
  LAYER v0 ;
    RECT -0.0280 -0.0230 0.0280 0.0230 ;
  LAYER m1 ;
    RECT -0.0280 -0.0370 0.0280 0.0370 ;
END VIA0BW

VIA VIA1V_XN
  RESISTANCE 5.72 ;
  LAYER m1 ;
    RECT -0.0280 -0.0440 0.0280 0.0440 ;
  LAYER v1 ;
    RECT -0.0180 -0.0370 0.0180 0.0370 ;
  LAYER m2 ;
    RECT -0.0420 -0.0370 0.0420 0.0370 ;
END VIA1V_XN

VIA VIA2A_32
  DEFAULT 
  RESISTANCE 5.72 ;
  LAYER m2 ;
    RECT -0.0230 -0.0160 0.0230 0.0160 ;
  LAYER v2 ;
    RECT -0.0140 -0.0160 0.0140 0.0160 ;
  LAYER m3 ;
    RECT -0.0140 -0.0400 0.0140 0.0400 ;
END VIA2A_32

VIA VIA1C
  RESISTANCE 5.72 ;
  LAYER m1 ;
    RECT -0.0210 -0.0230 0.0210 0.0230 ;
  LAYER v1 ;
    RECT -0.0180 -0.0160 0.0180 0.0160 ;
  LAYER m2 ;
    RECT -0.0420 -0.0160 0.0420 0.0160 ;
END VIA1C

VIA VIA1E
  RESISTANCE 5.72 ;
  LAYER m1 ;
    RECT -0.0210 -0.0260 0.0210 0.0260 ;
  LAYER v1 ;
    RECT -0.0180 -0.0190 0.0180 0.0190 ;
  LAYER m2 ;
    RECT -0.0420 -0.0190 0.0420 0.0190 ;
END VIA1E

VIA VIA0FX
  RESISTANCE 5.72 ;
  LAYER m0 ;
    RECT -0.0350 -0.0410 0.0350 0.0410 ;
  LAYER v0 ;
    RECT -0.0210 -0.0390 0.0210 0.0390 ;
  LAYER m1 ;
    RECT -0.0210 -0.0560 0.0210 0.0560 ;
END VIA0FX

VIA VIA5MP_56
  RESISTANCE 5.72 ;
  LAYER m5 ;
    RECT -0.0280 -0.0660 0.0280 0.0660 ;
  LAYER v5 ;
    RECT -0.0220 -0.0540 0.0220 0.0540 ;
  LAYER m6 ;
    RECT -0.0440 -0.0540 0.0440 0.0540 ;
END VIA5MP_56

VIA VIA5MP_60
  RESISTANCE 5.72 ;
  LAYER m5 ;
    RECT -0.0300 -0.0660 0.0300 0.0660 ;
  LAYER v5 ;
    RECT -0.0220 -0.0540 0.0220 0.0540 ;
  LAYER m6 ;
    RECT -0.0440 -0.0540 0.0440 0.0540 ;
END VIA5MP_60

VIA VIA4O_30
  RESISTANCE 5.72 ;
  LAYER m4 ;
    RECT -0.0510 -0.0150 0.0510 0.0150 ;
  LAYER v4 ;
    RECT -0.0420 -0.0160 0.0420 0.0160 ;
  LAYER m5 ;
    RECT -0.0420 -0.0400 0.0420 0.0400 ;
END VIA4O_30

VIA VIA6F_44
  RESISTANCE 5.72 ;
  LAYER m6 ;
    RECT -0.1000 -0.0220 0.1000 0.0220 ;
  LAYER v6 ;
    RECT -0.0840 -0.0300 0.0840 0.0300 ;
  LAYER m7 ;
    RECT -0.0840 -0.0620 0.0840 0.0620 ;
END VIA6F_44

VIA VIA2G
  RESISTANCE 5.72 ;
  LAYER m2 ;
    RECT -0.0320 -0.0140 0.0320 0.0140 ;
  LAYER v2 ;
    RECT -0.0230 -0.0160 0.0230 0.0160 ;
  LAYER m3 ;
    RECT -0.0230 -0.0400 0.0230 0.0400 ;
END VIA2G

VIA VIA2G_32
  RESISTANCE 5.72 ;
  LAYER m2 ;
    RECT -0.0320 -0.0160 0.0320 0.0160 ;
  LAYER v2 ;
    RECT -0.0230 -0.0160 0.0230 0.0160 ;
  LAYER m3 ;
    RECT -0.0230 -0.0400 0.0230 0.0400 ;
END VIA2G_32

VIA VIA2G_38
  RESISTANCE 5.72 ;
  LAYER m2 ;
    RECT -0.0320 -0.0190 0.0320 0.0190 ;
  LAYER v2 ;
    RECT -0.0230 -0.0160 0.0230 0.0160 ;
  LAYER m3 ;
    RECT -0.0230 -0.0400 0.0230 0.0400 ;
END VIA2G_38

VIA VIA2G_40
  RESISTANCE 5.72 ;
  LAYER m2 ;
    RECT -0.0320 -0.0200 0.0320 0.0200 ;
  LAYER v2 ;
    RECT -0.0230 -0.0160 0.0230 0.0160 ;
  LAYER m3 ;
    RECT -0.0230 -0.0400 0.0230 0.0400 ;
END VIA2G_40

VIA VIA2R_32
  RESISTANCE 5.72 ;
  LAYER m2 ;
    RECT -0.0390 -0.0160 0.0390 0.0160 ;
  LAYER v2 ;
    RECT -0.0300 -0.0160 0.0300 0.0160 ;
  LAYER m3 ;
    RECT -0.0300 -0.0400 0.0300 0.0400 ;
END VIA2R_32

VIA VIA2R_38
  RESISTANCE 5.72 ;
  LAYER m2 ;
    RECT -0.0390 -0.0190 0.0390 0.0190 ;
  LAYER v2 ;
    RECT -0.0300 -0.0160 0.0300 0.0160 ;
  LAYER m3 ;
    RECT -0.0300 -0.0400 0.0300 0.0400 ;
END VIA2R_38

VIA VIA2L38
  RESISTANCE 5.72 ;
  LAYER m2 ;
    RECT -0.0430 -0.0190 0.0430 0.0190 ;
  LAYER v2 ;
    RECT -0.0340 -0.0160 0.0340 0.0160 ;
  LAYER m3 ;
    RECT -0.0340 -0.0400 0.0340 0.0400 ;
END VIA2L38

VIA VIA2GY
  RESISTANCE 5.72 ;
  LAYER m2 ;
    RECT -0.0320 -0.0290 0.0320 0.0290 ;
  LAYER v2 ;
    RECT -0.0230 -0.0290 0.0230 0.0290 ;
  LAYER m3 ;
    RECT -0.0230 -0.0530 0.0230 0.0530 ;
END VIA2GY

VIA VIA3A_60
  RESISTANCE 5.72 ;
  LAYER m3 ;
    RECT -0.0300 -0.0230 0.0300 0.0230 ;
  LAYER v3 ;
    RECT -0.0160 -0.0140 0.0160 0.0140 ;
  LAYER m4 ;
    RECT -0.0400 -0.0140 0.0400 0.0140 ;
END VIA3A_60

VIA VIA3B_60
  RESISTANCE 5.72 ;
  LAYER m3 ;
    RECT -0.0300 -0.0240 0.0300 0.0240 ;
  LAYER v3 ;
    RECT -0.0160 -0.0150 0.0160 0.0150 ;
  LAYER m4 ;
    RECT -0.0400 -0.0150 0.0400 0.0150 ;
END VIA3B_60

VIA VIA3C_40
  RESISTANCE 5.72 ;
  LAYER m3 ;
    RECT -0.0200 -0.0250 0.0200 0.0250 ;
  LAYER v3 ;
    RECT -0.0160 -0.0160 0.0160 0.0160 ;
  LAYER m4 ;
    RECT -0.0400 -0.0160 0.0400 0.0160 ;
END VIA3C_40

VIA VIA3C_60
  RESISTANCE 5.72 ;
  LAYER m3 ;
    RECT -0.0300 -0.0250 0.0300 0.0250 ;
  LAYER v3 ;
    RECT -0.0160 -0.0160 0.0160 0.0160 ;
  LAYER m4 ;
    RECT -0.0400 -0.0160 0.0400 0.0160 ;
END VIA3C_60

VIA VIA3C_30
  RESISTANCE 5.72 ;
  LAYER m3 ;
    RECT -0.0150 -0.0250 0.0150 0.0250 ;
  LAYER v3 ;
    RECT -0.0160 -0.0160 0.0160 0.0160 ;
  LAYER m4 ;
    RECT -0.0400 -0.0160 0.0400 0.0160 ;
END VIA3C_30

VIA VIA3F_30
  RESISTANCE 5.72 ;
  LAYER m3 ;
    RECT -0.0150 -0.0290 0.0150 0.0290 ;
  LAYER v3 ;
    RECT -0.0160 -0.0200 0.0160 0.0200 ;
  LAYER m4 ;
    RECT -0.0400 -0.0200 0.0400 0.0200 ;
END VIA3F_30

VIA VIA3F_32
  RESISTANCE 5.72 ;
  LAYER m3 ;
    RECT -0.0160 -0.0290 0.0160 0.0290 ;
  LAYER v3 ;
    RECT -0.0160 -0.0200 0.0160 0.0200 ;
  LAYER m4 ;
    RECT -0.0400 -0.0200 0.0400 0.0200 ;
END VIA3F_32

VIA VIA3F_40
  RESISTANCE 5.72 ;
  LAYER m3 ;
    RECT -0.0200 -0.0290 0.0200 0.0290 ;
  LAYER v3 ;
    RECT -0.0160 -0.0200 0.0160 0.0200 ;
  LAYER m4 ;
    RECT -0.0400 -0.0200 0.0400 0.0200 ;
END VIA3F_40

VIA VIA3F_60
  RESISTANCE 5.72 ;
  LAYER m3 ;
    RECT -0.0300 -0.0290 0.0300 0.0290 ;
  LAYER v3 ;
    RECT -0.0160 -0.0200 0.0160 0.0200 ;
  LAYER m4 ;
    RECT -0.0400 -0.0200 0.0400 0.0200 ;
END VIA3F_60

VIA VIA3F_68
  RESISTANCE 5.72 ;
  LAYER m3 ;
    RECT -0.0340 -0.0290 0.0340 0.0290 ;
  LAYER v3 ;
    RECT -0.0160 -0.0200 0.0160 0.0200 ;
  LAYER m4 ;
    RECT -0.0400 -0.0200 0.0400 0.0200 ;
END VIA3F_68

VIA VIA3G_30
  RESISTANCE 5.72 ;
  LAYER m3 ;
    RECT -0.0150 -0.0320 0.0150 0.0320 ;
  LAYER v3 ;
    RECT -0.0160 -0.0230 0.0160 0.0230 ;
  LAYER m4 ;
    RECT -0.0400 -0.0230 0.0400 0.0230 ;
END VIA3G_30

VIA VIA3G_32
  RESISTANCE 5.72 ;
  LAYER m3 ;
    RECT -0.0160 -0.0320 0.0160 0.0320 ;
  LAYER v3 ;
    RECT -0.0160 -0.0230 0.0160 0.0230 ;
  LAYER m4 ;
    RECT -0.0400 -0.0230 0.0400 0.0230 ;
END VIA3G_32

VIA VIA3G_40
  RESISTANCE 5.72 ;
  LAYER m3 ;
    RECT -0.0200 -0.0320 0.0200 0.0320 ;
  LAYER v3 ;
    RECT -0.0160 -0.0230 0.0160 0.0230 ;
  LAYER m4 ;
    RECT -0.0400 -0.0230 0.0400 0.0230 ;
END VIA3G_40

VIA VIA3G_60
  RESISTANCE 5.72 ;
  LAYER m3 ;
    RECT -0.0300 -0.0320 0.0300 0.0320 ;
  LAYER v3 ;
    RECT -0.0160 -0.0230 0.0160 0.0230 ;
  LAYER m4 ;
    RECT -0.0400 -0.0230 0.0400 0.0230 ;
END VIA3G_60

VIA VIA3R
  RESISTANCE 5.72 ;
  LAYER m3 ;
    RECT -0.0140 -0.0390 0.0140 0.0390 ;
  LAYER v3 ;
    RECT -0.0160 -0.0300 0.0160 0.0300 ;
  LAYER m4 ;
    RECT -0.0400 -0.0300 0.0400 0.0300 ;
END VIA3R

VIA VIA3R_30
  RESISTANCE 5.72 ;
  LAYER m3 ;
    RECT -0.0150 -0.0390 0.0150 0.0390 ;
  LAYER v3 ;
    RECT -0.0160 -0.0300 0.0160 0.0300 ;
  LAYER m4 ;
    RECT -0.0400 -0.0300 0.0400 0.0300 ;
END VIA3R_30

VIA VIA3R_32
  RESISTANCE 5.72 ;
  LAYER m3 ;
    RECT -0.0160 -0.0390 0.0160 0.0390 ;
  LAYER v3 ;
    RECT -0.0160 -0.0300 0.0160 0.0300 ;
  LAYER m4 ;
    RECT -0.0400 -0.0300 0.0400 0.0300 ;
END VIA3R_32

VIA VIA3R_40
  RESISTANCE 5.72 ;
  LAYER m3 ;
    RECT -0.0200 -0.0390 0.0200 0.0390 ;
  LAYER v3 ;
    RECT -0.0160 -0.0300 0.0160 0.0300 ;
  LAYER m4 ;
    RECT -0.0400 -0.0300 0.0400 0.0300 ;
END VIA3R_40

VIA VIA3RY_60
  RESISTANCE 5.72 ;
  LAYER m3 ;
    RECT -0.0300 -0.0390 0.0300 0.0390 ;
  LAYER v3 ;
    RECT -0.0220 -0.0300 0.0220 0.0300 ;
  LAYER m4 ;
    RECT -0.0460 -0.0300 0.0460 0.0300 ;
END VIA3RY_60

VIA VIA3N_30
  RESISTANCE 5.72 ;
  LAYER m3 ;
    RECT -0.0150 -0.0420 0.0150 0.0420 ;
  LAYER v3 ;
    RECT -0.0160 -0.0330 0.0160 0.0330 ;
  LAYER m4 ;
    RECT -0.0400 -0.0330 0.0400 0.0330 ;
END VIA3N_30

VIA VIA3N_32
  RESISTANCE 5.72 ;
  LAYER m3 ;
    RECT -0.0160 -0.0420 0.0160 0.0420 ;
  LAYER v3 ;
    RECT -0.0160 -0.0330 0.0160 0.0330 ;
  LAYER m4 ;
    RECT -0.0400 -0.0330 0.0400 0.0330 ;
END VIA3N_32

VIA VIA3N_40
  RESISTANCE 5.72 ;
  LAYER m3 ;
    RECT -0.0200 -0.0420 0.0200 0.0420 ;
  LAYER v3 ;
    RECT -0.0160 -0.0330 0.0160 0.0330 ;
  LAYER m4 ;
    RECT -0.0400 -0.0330 0.0400 0.0330 ;
END VIA3N_40

VIA VIA3NX_60
  RESISTANCE 5.72 ;
  LAYER m3 ;
    RECT -0.0300 -0.0460 0.0300 0.0460 ;
  LAYER v3 ;
    RECT -0.0190 -0.0370 0.0190 0.0370 ;
  LAYER m4 ;
    RECT -0.0430 -0.0370 0.0430 0.0370 ;
END VIA3NX_60

VIA VIA1F_PG
  RESISTANCE 5.72 ;
  LAYER m1 ;
    RECT -0.0210 -0.0370 0.0210 0.0370 ;
  LAYER v1 ;
    RECT -0.0180 -0.0200 0.0180 0.0200 ;
  LAYER m2 ;
    RECT -0.0420 -0.0200 0.0420 0.0200 ;
END VIA1F_PG

VIA VIA3NX_76
  RESISTANCE 5.72 ;
  LAYER m3 ;
    RECT -0.0380 -0.0460 0.0380 0.0460 ;
  LAYER v3 ;
    RECT -0.0190 -0.0370 0.0190 0.0370 ;
  LAYER m4 ;
    RECT -0.0430 -0.0370 0.0430 0.0370 ;
END VIA3NX_76

VIA VIA3VX_60
  RESISTANCE 5.72 ;
  LAYER m3 ;
    RECT -0.0300 -0.0420 0.0300 0.0420 ;
  LAYER v3 ;
    RECT -0.0200 -0.0330 0.0200 0.0330 ;
  LAYER m4 ;
    RECT -0.0440 -0.0330 0.0440 0.0330 ;
END VIA3VX_60

VIA VIA3VX_76
  RESISTANCE 5.72 ;
  LAYER m3 ;
    RECT -0.0380 -0.0420 0.0380 0.0420 ;
  LAYER v3 ;
    RECT -0.0200 -0.0330 0.0200 0.0330 ;
  LAYER m4 ;
    RECT -0.0440 -0.0330 0.0440 0.0330 ;
END VIA3VX_76

VIA VIA3S_30
  RESISTANCE 5.72 ;
  LAYER m3 ;
    RECT -0.0150 -0.0470 0.0150 0.0470 ;
  LAYER v3 ;
    RECT -0.0160 -0.0380 0.0160 0.0380 ;
  LAYER m4 ;
    RECT -0.0400 -0.0380 0.0400 0.0380 ;
END VIA3S_30

VIA VIA3S_40
  RESISTANCE 5.72 ;
  LAYER m3 ;
    RECT -0.0200 -0.0470 0.0200 0.0470 ;
  LAYER v3 ;
    RECT -0.0160 -0.0380 0.0160 0.0380 ;
  LAYER m4 ;
    RECT -0.0400 -0.0380 0.0400 0.0380 ;
END VIA3S_40

VIA VIA3S_60
  RESISTANCE 5.72 ;
  LAYER m3 ;
    RECT -0.0300 -0.0470 0.0300 0.0470 ;
  LAYER v3 ;
    RECT -0.0160 -0.0380 0.0160 0.0380 ;
  LAYER m4 ;
    RECT -0.0400 -0.0380 0.0400 0.0380 ;
END VIA3S_60

VIA VIA3S_68
  RESISTANCE 5.72 ;
  LAYER m3 ;
    RECT -0.0340 -0.0470 0.0340 0.0470 ;
  LAYER v3 ;
    RECT -0.0160 -0.0380 0.0160 0.0380 ;
  LAYER m4 ;
    RECT -0.0400 -0.0380 0.0400 0.0380 ;
END VIA3S_68

VIA VIA3S_76
  RESISTANCE 5.72 ;
  LAYER m3 ;
    RECT -0.0380 -0.0470 0.0380 0.0470 ;
  LAYER v3 ;
    RECT -0.0160 -0.0380 0.0160 0.0380 ;
  LAYER m4 ;
    RECT -0.0400 -0.0380 0.0400 0.0380 ;
END VIA3S_76

VIA VIA3O_30
  RESISTANCE 5.72 ;
  LAYER m3 ;
    RECT -0.0150 -0.0510 0.0150 0.0510 ;
  LAYER v3 ;
    RECT -0.0160 -0.0420 0.0160 0.0420 ;
  LAYER m4 ;
    RECT -0.0400 -0.0420 0.0400 0.0420 ;
END VIA3O_30

VIA VIA3O_40
  RESISTANCE 5.72 ;
  LAYER m3 ;
    RECT -0.0200 -0.0510 0.0200 0.0510 ;
  LAYER v3 ;
    RECT -0.0160 -0.0420 0.0160 0.0420 ;
  LAYER m4 ;
    RECT -0.0400 -0.0420 0.0400 0.0420 ;
END VIA3O_40

VIA VIA3O_60
  RESISTANCE 5.72 ;
  LAYER m3 ;
    RECT -0.0300 -0.0510 0.0300 0.0510 ;
  LAYER v3 ;
    RECT -0.0160 -0.0420 0.0160 0.0420 ;
  LAYER m4 ;
    RECT -0.0400 -0.0420 0.0400 0.0420 ;
END VIA3O_60

VIA VIA3O_68
  RESISTANCE 5.72 ;
  LAYER m3 ;
    RECT -0.0340 -0.0510 0.0340 0.0510 ;
  LAYER v3 ;
    RECT -0.0160 -0.0420 0.0160 0.0420 ;
  LAYER m4 ;
    RECT -0.0400 -0.0420 0.0400 0.0420 ;
END VIA3O_68

VIA VIA3O_76
  RESISTANCE 5.72 ;
  LAYER m3 ;
    RECT -0.0380 -0.0510 0.0380 0.0510 ;
  LAYER v3 ;
    RECT -0.0160 -0.0420 0.0160 0.0420 ;
  LAYER m4 ;
    RECT -0.0400 -0.0420 0.0400 0.0420 ;
END VIA3O_76

VIA VIA4A_32
  RESISTANCE 5.72 ;
  LAYER m4 ;
    RECT -0.0230 -0.0160 0.0230 0.0160 ;
  LAYER v4 ;
    RECT -0.0140 -0.0160 0.0140 0.0160 ;
  LAYER m5 ;
    RECT -0.0140 -0.0400 0.0140 0.0400 ;
END VIA4A_32

VIA VIA4A_36
  RESISTANCE 5.72 ;
  LAYER m4 ;
    RECT -0.0230 -0.0180 0.0230 0.0180 ;
  LAYER v4 ;
    RECT -0.0140 -0.0160 0.0140 0.0160 ;
  LAYER m5 ;
    RECT -0.0140 -0.0400 0.0140 0.0400 ;
END VIA4A_36

VIA VIA4A_40
  RESISTANCE 5.72 ;
  LAYER m4 ;
    RECT -0.0230 -0.0200 0.0230 0.0200 ;
  LAYER v4 ;
    RECT -0.0140 -0.0160 0.0140 0.0160 ;
  LAYER m5 ;
    RECT -0.0140 -0.0400 0.0140 0.0400 ;
END VIA4A_40

VIA VIA4A_46
  RESISTANCE 5.72 ;
  LAYER m4 ;
    RECT -0.0230 -0.0230 0.0230 0.0230 ;
  LAYER v4 ;
    RECT -0.0140 -0.0160 0.0140 0.0160 ;
  LAYER m5 ;
    RECT -0.0140 -0.0400 0.0140 0.0400 ;
END VIA4A_46

VIA VIA4A_54
  RESISTANCE 5.72 ;
  LAYER m4 ;
    RECT -0.0230 -0.0270 0.0230 0.0270 ;
  LAYER v4 ;
    RECT -0.0140 -0.0160 0.0140 0.0160 ;
  LAYER m5 ;
    RECT -0.0140 -0.0400 0.0140 0.0400 ;
END VIA4A_54

VIA VIA4A_56
  RESISTANCE 5.72 ;
  LAYER m4 ;
    RECT -0.0230 -0.0280 0.0230 0.0280 ;
  LAYER v4 ;
    RECT -0.0140 -0.0160 0.0140 0.0160 ;
  LAYER m5 ;
    RECT -0.0140 -0.0400 0.0140 0.0400 ;
END VIA4A_56

VIA VIA4A_60
  RESISTANCE 5.72 ;
  LAYER m4 ;
    RECT -0.0230 -0.0300 0.0230 0.0300 ;
  LAYER v4 ;
    RECT -0.0140 -0.0160 0.0140 0.0160 ;
  LAYER m5 ;
    RECT -0.0140 -0.0400 0.0140 0.0400 ;
END VIA4A_60

VIA VIA4A_66
  RESISTANCE 5.72 ;
  LAYER m4 ;
    RECT -0.0230 -0.0330 0.0230 0.0330 ;
  LAYER v4 ;
    RECT -0.0140 -0.0160 0.0140 0.0160 ;
  LAYER m5 ;
    RECT -0.0140 -0.0400 0.0140 0.0400 ;
END VIA4A_66

VIA VIA4B_32
  RESISTANCE 5.72 ;
  LAYER m4 ;
    RECT -0.0240 -0.0160 0.0240 0.0160 ;
  LAYER v4 ;
    RECT -0.0150 -0.0160 0.0150 0.0160 ;
  LAYER m5 ;
    RECT -0.0150 -0.0400 0.0150 0.0400 ;
END VIA4B_32

VIA VIA4B_36
  RESISTANCE 5.72 ;
  LAYER m4 ;
    RECT -0.0240 -0.0180 0.0240 0.0180 ;
  LAYER v4 ;
    RECT -0.0150 -0.0160 0.0150 0.0160 ;
  LAYER m5 ;
    RECT -0.0150 -0.0400 0.0150 0.0400 ;
END VIA4B_36

VIA VIA4B_40
  RESISTANCE 5.72 ;
  LAYER m4 ;
    RECT -0.0240 -0.0200 0.0240 0.0200 ;
  LAYER v4 ;
    RECT -0.0150 -0.0160 0.0150 0.0160 ;
  LAYER m5 ;
    RECT -0.0150 -0.0400 0.0150 0.0400 ;
END VIA4B_40

VIA VIA4B_46
  RESISTANCE 5.72 ;
  LAYER m4 ;
    RECT -0.0240 -0.0230 0.0240 0.0230 ;
  LAYER v4 ;
    RECT -0.0150 -0.0160 0.0150 0.0160 ;
  LAYER m5 ;
    RECT -0.0150 -0.0400 0.0150 0.0400 ;
END VIA4B_46

VIA VIA4B_54
  RESISTANCE 5.72 ;
  LAYER m4 ;
    RECT -0.0240 -0.0270 0.0240 0.0270 ;
  LAYER v4 ;
    RECT -0.0150 -0.0160 0.0150 0.0160 ;
  LAYER m5 ;
    RECT -0.0150 -0.0400 0.0150 0.0400 ;
END VIA4B_54

VIA VIA4B_56
  RESISTANCE 5.72 ;
  LAYER m4 ;
    RECT -0.0240 -0.0280 0.0240 0.0280 ;
  LAYER v4 ;
    RECT -0.0150 -0.0160 0.0150 0.0160 ;
  LAYER m5 ;
    RECT -0.0150 -0.0400 0.0150 0.0400 ;
END VIA4B_56

VIA VIA4B_60
  RESISTANCE 5.72 ;
  LAYER m4 ;
    RECT -0.0240 -0.0300 0.0240 0.0300 ;
  LAYER v4 ;
    RECT -0.0150 -0.0160 0.0150 0.0160 ;
  LAYER m5 ;
    RECT -0.0150 -0.0400 0.0150 0.0400 ;
END VIA4B_60

VIA VIA4B_66
  RESISTANCE 5.72 ;
  LAYER m4 ;
    RECT -0.0240 -0.0330 0.0240 0.0330 ;
  LAYER v4 ;
    RECT -0.0150 -0.0160 0.0150 0.0160 ;
  LAYER m5 ;
    RECT -0.0150 -0.0400 0.0150 0.0400 ;
END VIA4B_66

VIA VIA4C_30
  RESISTANCE 5.72 ;
  LAYER m4 ;
    RECT -0.0250 -0.0150 0.0250 0.0150 ;
  LAYER v4 ;
    RECT -0.0160 -0.0160 0.0160 0.0160 ;
  LAYER m5 ;
    RECT -0.0160 -0.0400 0.0160 0.0400 ;
END VIA4C_30

VIA VIA4C_36
  RESISTANCE 5.72 ;
  LAYER m4 ;
    RECT -0.0250 -0.0180 0.0250 0.0180 ;
  LAYER v4 ;
    RECT -0.0160 -0.0160 0.0160 0.0160 ;
  LAYER m5 ;
    RECT -0.0160 -0.0400 0.0160 0.0400 ;
END VIA4C_36

VIA VIA4C_40
  RESISTANCE 5.72 ;
  LAYER m4 ;
    RECT -0.0250 -0.0200 0.0250 0.0200 ;
  LAYER v4 ;
    RECT -0.0160 -0.0160 0.0160 0.0160 ;
  LAYER m5 ;
    RECT -0.0160 -0.0400 0.0160 0.0400 ;
END VIA4C_40

VIA VIA4C_46
  RESISTANCE 5.72 ;
  LAYER m4 ;
    RECT -0.0250 -0.0230 0.0250 0.0230 ;
  LAYER v4 ;
    RECT -0.0160 -0.0160 0.0160 0.0160 ;
  LAYER m5 ;
    RECT -0.0160 -0.0400 0.0160 0.0400 ;
END VIA4C_46

VIA VIA4C_54
  RESISTANCE 5.72 ;
  LAYER m4 ;
    RECT -0.0250 -0.0270 0.0250 0.0270 ;
  LAYER v4 ;
    RECT -0.0160 -0.0160 0.0160 0.0160 ;
  LAYER m5 ;
    RECT -0.0160 -0.0400 0.0160 0.0400 ;
END VIA4C_54

VIA VIA4C_56
  RESISTANCE 5.72 ;
  LAYER m4 ;
    RECT -0.0250 -0.0280 0.0250 0.0280 ;
  LAYER v4 ;
    RECT -0.0160 -0.0160 0.0160 0.0160 ;
  LAYER m5 ;
    RECT -0.0160 -0.0400 0.0160 0.0400 ;
END VIA4C_56

VIA VIA4C_60
  RESISTANCE 5.72 ;
  LAYER m4 ;
    RECT -0.0250 -0.0300 0.0250 0.0300 ;
  LAYER v4 ;
    RECT -0.0160 -0.0160 0.0160 0.0160 ;
  LAYER m5 ;
    RECT -0.0160 -0.0400 0.0160 0.0400 ;
END VIA4C_60

VIA VIA4C_66
  RESISTANCE 5.72 ;
  LAYER m4 ;
    RECT -0.0250 -0.0330 0.0250 0.0330 ;
  LAYER v4 ;
    RECT -0.0160 -0.0160 0.0160 0.0160 ;
  LAYER m5 ;
    RECT -0.0160 -0.0400 0.0160 0.0400 ;
END VIA4C_66

VIA VIA0FX_78
  RESISTANCE 5.72 ;
  LAYER m0 ;
    RECT -0.0350 -0.0390 0.0350 0.0390 ;
  LAYER v0 ;
    RECT -0.0210 -0.0390 0.0210 0.0390 ;
  LAYER m1 ;
    RECT -0.0210 -0.0560 0.0210 0.0560 ;
END VIA0FX_78

VIA VIA0AX_36
  RESISTANCE 5.72 ;
  LAYER m0 ;
    RECT -0.0350 -0.0180 0.0350 0.0180 ;
  LAYER v0 ;
    RECT -0.0210 -0.0140 0.0210 0.0140 ;
  LAYER m1 ;
    RECT -0.0210 -0.0280 0.0210 0.0280 ;
END VIA0AX_36

VIA VIA0FX_80
  RESISTANCE 5.72 ;
  LAYER m0 ;
    RECT -0.0350 -0.0400 0.0350 0.0400 ;
  LAYER v0 ;
    RECT -0.0210 -0.0390 0.0210 0.0390 ;
  LAYER m1 ;
    RECT -0.0210 -0.0560 0.0210 0.0560 ;
END VIA0FX_80

VIA VIA0BX
  RESISTANCE 5.72 ;
  LAYER m0 ;
    RECT -0.0350 -0.0160 0.0350 0.0160 ;
  LAYER v0 ;
    RECT -0.0210 -0.0160 0.0210 0.0160 ;
  LAYER m1 ;
    RECT -0.0210 -0.0300 0.0210 0.0300 ;
END VIA0BX

VIA VIA2A_m3_26
  RESISTANCE 5.72 ;
  LAYER m2 ;
    RECT -0.0230 -0.0140 0.0230 0.0140 ;
  LAYER v2 ;
    RECT -0.0140 -0.0160 0.0140 0.0160 ;
  LAYER m3 ;
    RECT -0.0140 -0.0420 0.0140 0.0420 ;
END VIA2A_m3_26

VIA VIA0BX_36
  RESISTANCE 5.72 ;
  LAYER m0 ;
    RECT -0.0350 -0.0180 0.0350 0.0180 ;
  LAYER v0 ;
    RECT -0.0210 -0.0160 0.0210 0.0160 ;
  LAYER m1 ;
    RECT -0.0210 -0.0300 0.0210 0.0300 ;
END VIA0BX_36

VIA VIA2C_m3_26
  RESISTANCE 5.72 ;
  LAYER m2 ;
    RECT -0.0250 -0.0140 0.0250 0.0140 ;
  LAYER v2 ;
    RECT -0.0160 -0.0160 0.0160 0.0160 ;
  LAYER m3 ;
    RECT -0.0160 -0.0420 0.0160 0.0420 ;
END VIA2C_m3_26

VIA VIA1HJ
  RESISTANCE 5.72 ;
  LAYER m1 ;
    RECT -0.0210 -0.0490 0.0210 0.0490 ;
  LAYER v1 ;
    RECT -0.0180 -0.0320 0.0180 0.0320 ;
  LAYER m2 ;
    RECT -0.0420 -0.0380 0.0420 0.0380 ;
END VIA1HJ

VIA VIA5MP_66
  RESISTANCE 5.72 ;
  LAYER m5 ;
    RECT -0.0330 -0.0660 0.0330 0.0660 ;
  LAYER v5 ;
    RECT -0.0220 -0.0540 0.0220 0.0540 ;
  LAYER m6 ;
    RECT -0.0440 -0.0540 0.0440 0.0540 ;
END VIA5MP_66

VIA VIA5MP_68
  RESISTANCE 5.72 ;
  LAYER m5 ;
    RECT -0.0340 -0.0660 0.0340 0.0660 ;
  LAYER v5 ;
    RECT -0.0220 -0.0540 0.0220 0.0540 ;
  LAYER m6 ;
    RECT -0.0440 -0.0540 0.0440 0.0540 ;
END VIA5MP_68

VIA VIA5MP_74
  RESISTANCE 5.72 ;
  LAYER m5 ;
    RECT -0.0370 -0.0660 0.0370 0.0660 ;
  LAYER v5 ;
    RECT -0.0220 -0.0540 0.0220 0.0540 ;
  LAYER m6 ;
    RECT -0.0440 -0.0540 0.0440 0.0540 ;
END VIA5MP_74

VIA VIA5MP_76
  RESISTANCE 5.72 ;
  LAYER m5 ;
    RECT -0.0380 -0.0660 0.0380 0.0660 ;
  LAYER v5 ;
    RECT -0.0220 -0.0540 0.0220 0.0540 ;
  LAYER m6 ;
    RECT -0.0440 -0.0540 0.0440 0.0540 ;
END VIA5MP_76

VIA VIA5MP_84
  RESISTANCE 5.72 ;
  LAYER m5 ;
    RECT -0.0420 -0.0660 0.0420 0.0660 ;
  LAYER v5 ;
    RECT -0.0220 -0.0540 0.0220 0.0540 ;
  LAYER m6 ;
    RECT -0.0440 -0.0540 0.0440 0.0540 ;
END VIA5MP_84

VIA VIA5FA_32
  RESISTANCE 5.72 ;
  LAYER m5 ;
    RECT -0.0160 -0.0660 0.0160 0.0660 ;
  LAYER v5 ;
    RECT -0.0160 -0.0540 0.0160 0.0540 ;
  LAYER m6 ;
    RECT -0.0380 -0.0540 0.0380 0.0540 ;
END VIA5FA_32

VIA VIA4A_m5_26
  RESISTANCE 5.72 ;
  LAYER m4 ;
    RECT -0.0230 -0.0160 0.0230 0.0160 ;
  LAYER v4 ;
    RECT -0.0140 -0.0160 0.0140 0.0160 ;
  LAYER m5 ;
    RECT -0.0140 -0.0420 0.0140 0.0420 ;
END VIA4A_m5_26

VIA VIA4C_m5_26
  RESISTANCE 5.72 ;
  LAYER m4 ;
    RECT -0.0250 -0.0160 0.0250 0.0160 ;
  LAYER v4 ;
    RECT -0.0160 -0.0160 0.0160 0.0160 ;
  LAYER m5 ;
    RECT -0.0160 -0.0420 0.0160 0.0420 ;
END VIA4C_m5_26

VIA VIA4RX_40_60
  RESISTANCE 5.72 ;
  LAYER m4 ;
    RECT -0.0390 -0.0200 0.0390 0.0200 ;
  LAYER v4 ;
    RECT -0.0300 -0.0190 0.0300 0.0190 ;
  LAYER m5 ;
    RECT -0.0300 -0.0430 0.0300 0.0430 ;
END VIA4RX_40_60

VIA VIA4RY_60_60
  RESISTANCE 5.72 ;
  LAYER m4 ;
    RECT -0.0390 -0.0300 0.0390 0.0300 ;
  LAYER v4 ;
    RECT -0.0300 -0.0220 0.0300 0.0220 ;
  LAYER m5 ;
    RECT -0.0300 -0.0460 0.0300 0.0460 ;
END VIA4RY_60_60

VIA VIA5B_60_44
  RESISTANCE 5.72 ;
  LAYER m5 ;
    RECT -0.0300 -0.0340 0.0300 0.0340 ;
  LAYER v5 ;
    RECT -0.0160 -0.0220 0.0160 0.0220 ;
  LAYER m6 ;
    RECT -0.0380 -0.0220 0.0380 0.0220 ;
END VIA5B_60_44

VIA VIA4R_60_60
  RESISTANCE 5.72 ;
  LAYER m4 ;
    RECT -0.0390 -0.0200 0.0390 0.0200 ;
  LAYER v4 ;
    RECT -0.0300 -0.0160 0.0300 0.0160 ;
  LAYER m5 ;
    RECT -0.0300 -0.0400 0.0300 0.0400 ;
END VIA4R_60_60

VIA VIA5FA_40
  RESISTANCE 5.72 ;
  LAYER m5 ;
    RECT -0.0200 -0.0660 0.0200 0.0660 ;
  LAYER v5 ;
    RECT -0.0160 -0.0540 0.0160 0.0540 ;
  LAYER m6 ;
    RECT -0.0380 -0.0540 0.0380 0.0540 ;
END VIA5FA_40

VIA VIA5C
  RESISTANCE 5.72 ;
  LAYER m5 ;
    RECT -0.0140 -0.0520 0.0140 0.0520 ;
  LAYER v5 ;
    RECT -0.0160 -0.0400 0.0160 0.0400 ;
  LAYER m6 ;
    RECT -0.0380 -0.0400 0.0380 0.0400 ;
END VIA5C

VIA VIA5C_32
  RESISTANCE 5.72 ;
  LAYER m5 ;
    RECT -0.0160 -0.0520 0.0160 0.0520 ;
  LAYER v5 ;
    RECT -0.0160 -0.0400 0.0160 0.0400 ;
  LAYER m6 ;
    RECT -0.0380 -0.0400 0.0380 0.0400 ;
END VIA5C_32

VIA VIA5C_36
  RESISTANCE 5.72 ;
  LAYER m5 ;
    RECT -0.0180 -0.0520 0.0180 0.0520 ;
  LAYER v5 ;
    RECT -0.0160 -0.0400 0.0160 0.0400 ;
  LAYER m6 ;
    RECT -0.0380 -0.0400 0.0380 0.0400 ;
END VIA5C_36

VIA VIA5CP
  RESISTANCE 5.72 ;
  LAYER m5 ;
    RECT -0.0200 -0.0520 0.0200 0.0520 ;
  LAYER v5 ;
    RECT -0.0220 -0.0400 0.0220 0.0400 ;
  LAYER m6 ;
    RECT -0.0440 -0.0400 0.0440 0.0400 ;
END VIA5CP

VIA VIA5CP_46
  RESISTANCE 5.72 ;
  LAYER m5 ;
    RECT -0.0230 -0.0520 0.0230 0.0520 ;
  LAYER v5 ;
    RECT -0.0220 -0.0400 0.0220 0.0400 ;
  LAYER m6 ;
    RECT -0.0440 -0.0400 0.0440 0.0400 ;
END VIA5CP_46

VIA VIA5CP_56
  RESISTANCE 5.72 ;
  LAYER m5 ;
    RECT -0.0280 -0.0520 0.0280 0.0520 ;
  LAYER v5 ;
    RECT -0.0220 -0.0400 0.0220 0.0400 ;
  LAYER m6 ;
    RECT -0.0440 -0.0400 0.0440 0.0400 ;
END VIA5CP_56

VIA VIA5CP_60
  RESISTANCE 5.72 ;
  LAYER m5 ;
    RECT -0.0300 -0.0520 0.0300 0.0520 ;
  LAYER v5 ;
    RECT -0.0220 -0.0400 0.0220 0.0400 ;
  LAYER m6 ;
    RECT -0.0440 -0.0400 0.0440 0.0400 ;
END VIA5CP_60

VIA VIA5CP_66
  RESISTANCE 5.72 ;
  LAYER m5 ;
    RECT -0.0330 -0.0520 0.0330 0.0520 ;
  LAYER v5 ;
    RECT -0.0220 -0.0400 0.0220 0.0400 ;
  LAYER m6 ;
    RECT -0.0440 -0.0400 0.0440 0.0400 ;
END VIA5CP_66

VIA VIA5CP_74
  RESISTANCE 5.72 ;
  LAYER m5 ;
    RECT -0.0370 -0.0520 0.0370 0.0520 ;
  LAYER v5 ;
    RECT -0.0220 -0.0400 0.0220 0.0400 ;
  LAYER m6 ;
    RECT -0.0440 -0.0400 0.0440 0.0400 ;
END VIA5CP_74

VIA VIA5CP_76
  RESISTANCE 5.72 ;
  LAYER m5 ;
    RECT -0.0340 -0.0520 0.0340 0.0520 ;
  LAYER v5 ;
    RECT -0.0220 -0.0400 0.0220 0.0400 ;
  LAYER m6 ;
    RECT -0.0440 -0.0400 0.0440 0.0400 ;
END VIA5CP_76

VIA VIA5CP_84
  RESISTANCE 5.72 ;
  LAYER m5 ;
    RECT -0.0420 -0.0520 0.0420 0.0520 ;
  LAYER v5 ;
    RECT -0.0220 -0.0400 0.0220 0.0400 ;
  LAYER m6 ;
    RECT -0.0440 -0.0400 0.0440 0.0400 ;
END VIA5CP_84

VIA VIA6C_44
  RESISTANCE 5.72 ;
  LAYER m6 ;
    RECT -0.0580 -0.0220 0.0580 0.0220 ;
  LAYER v6 ;
    RECT -0.0420 -0.0300 0.0420 0.0300 ;
  LAYER m7 ;
    RECT -0.0420 -0.0620 0.0420 0.0620 ;
END VIA6C_44

VIA VIA6C_90
  RESISTANCE 5.72 ;
  LAYER m6 ;
    RECT -0.0580 -0.0450 0.0580 0.0450 ;
  LAYER v6 ;
    RECT -0.0420 -0.0300 0.0420 0.0300 ;
  LAYER m7 ;
    RECT -0.0420 -0.0620 0.0420 0.0620 ;
END VIA6C_90

VIA VIA6C_108
  RESISTANCE 5.72 ;
  LAYER m6 ;
    RECT -0.0580 -0.0540 0.0580 0.0540 ;
  LAYER v6 ;
    RECT -0.0420 -0.0300 0.0420 0.0300 ;
  LAYER m7 ;
    RECT -0.0420 -0.0620 0.0420 0.0620 ;
END VIA6C_108

VIA VIA6A_90
  RESISTANCE 5.72 ;
  LAYER m6 ;
    RECT -0.0440 -0.0450 0.0440 0.0450 ;
  LAYER v6 ;
    RECT -0.0280 -0.0300 0.0280 0.0300 ;
  LAYER m7 ;
    RECT -0.0280 -0.0620 0.0280 0.0620 ;
END VIA6A_90

VIA VIA0AX_DA
  RESISTANCE 5.72 ;
  LAYER m0 ;
    RECT -0.0400 -0.0140 0.0400 0.0140 ;
  LAYER v0 ;
    RECT -0.0210 -0.0140 0.0210 0.0140 ;
  LAYER m1 ;
    RECT -0.0210 -0.0280 0.0210 0.0280 ;
END VIA0AX_DA

VIA VIA0AX_DB
  RESISTANCE 5.72 ;
  LAYER m0 ;
    RECT -0.0350 -0.0140 0.0350 0.0140 ;
  LAYER v0 ;
    RECT -0.0210 -0.0140 0.0210 0.0140 ;
  LAYER m1 ;
    RECT -0.0210 -0.0330 0.0210 0.0330 ;
END VIA0AX_DB

VIA VIA0AX_DC
  RESISTANCE 5.72 ;
  LAYER m0 ;
    RECT -0.0400 -0.0140 0.0400 0.0140 ;
  LAYER v0 ;
    RECT -0.0210 -0.0140 0.0210 0.0140 ;
  LAYER m1 ;
    RECT -0.0210 -0.0330 0.0210 0.0330 ;
END VIA0AX_DC

VIA VIA1A_DA
  RESISTANCE 5.72 ;
  LAYER m1 ;
    RECT -0.0210 -0.0260 0.0210 0.0260 ;
  LAYER v1 ;
    RECT -0.0180 -0.0140 0.0180 0.0140 ;
  LAYER m2 ;
    RECT -0.0420 -0.0140 0.0420 0.0140 ;
END VIA1A_DA

VIA VIA1A_DB
  RESISTANCE 5.72 ;
  LAYER m1 ;
    RECT -0.0210 -0.0210 0.0210 0.0210 ;
  LAYER v1 ;
    RECT -0.0180 -0.0140 0.0180 0.0140 ;
  LAYER m2 ;
    RECT -0.0470 -0.0140 0.0470 0.0140 ;
END VIA1A_DB

VIA VIA1A_DC
  RESISTANCE 5.72 ;
  LAYER m1 ;
    RECT -0.0210 -0.0260 0.0210 0.0260 ;
  LAYER v1 ;
    RECT -0.0180 -0.0140 0.0180 0.0140 ;
  LAYER m2 ;
    RECT -0.0470 -0.0140 0.0470 0.0140 ;
END VIA1A_DC

VIA VIA2A_DA
  RESISTANCE 5.72 ;
  LAYER m2 ;
    RECT -0.0280 -0.0140 0.0280 0.0140 ;
  LAYER v2 ;
    RECT -0.0140 -0.0160 0.0140 0.0160 ;
  LAYER m3 ;
    RECT -0.0140 -0.0400 0.0140 0.0400 ;
END VIA2A_DA

VIA VIA2A_DB
  RESISTANCE 5.72 ;
  LAYER m2 ;
    RECT -0.0230 -0.0140 0.0230 0.0140 ;
  LAYER v2 ;
    RECT -0.0140 -0.0160 0.0140 0.0160 ;
  LAYER m3 ;
    RECT -0.0140 -0.0450 0.0140 0.0450 ;
END VIA2A_DB

VIA VIA2A_DC
  RESISTANCE 5.72 ;
  LAYER m2 ;
    RECT -0.0280 -0.0140 0.0280 0.0140 ;
  LAYER v2 ;
    RECT -0.0140 -0.0160 0.0140 0.0160 ;
  LAYER m3 ;
    RECT -0.0140 -0.0450 0.0140 0.0450 ;
END VIA2A_DC

VIA VIA2C_DA
  RESISTANCE 5.72 ;
  LAYER m2 ;
    RECT -0.0300 -0.0140 0.0300 0.0140 ;
  LAYER v2 ;
    RECT -0.0160 -0.0160 0.0160 0.0160 ;
  LAYER m3 ;
    RECT -0.0160 -0.0400 0.0160 0.0400 ;
END VIA2C_DA

VIA VIA2C_DB
  RESISTANCE 5.72 ;
  LAYER m2 ;
    RECT -0.0250 -0.0140 0.0250 0.0140 ;
  LAYER v2 ;
    RECT -0.0160 -0.0160 0.0160 0.0160 ;
  LAYER m3 ;
    RECT -0.0160 -0.0450 0.0160 0.0450 ;
END VIA2C_DB

VIA VIA2C_DC
  RESISTANCE 5.72 ;
  LAYER m2 ;
    RECT -0.0300 -0.0140 0.0300 0.0140 ;
  LAYER v2 ;
    RECT -0.0160 -0.0160 0.0160 0.0160 ;
  LAYER m3 ;
    RECT -0.0160 -0.0450 0.0160 0.0450 ;
END VIA2C_DC

VIA VIA3C_DA
  RESISTANCE 5.72 ;
  LAYER m3 ;
    RECT -0.0160 -0.0300 0.0160 0.0300 ;
  LAYER v3 ;
    RECT -0.0160 -0.0160 0.0160 0.0160 ;
  LAYER m4 ;
    RECT -0.0400 -0.0160 0.0400 0.0160 ;
END VIA3C_DA

VIA VIA3C_DB
  RESISTANCE 5.72 ;
  LAYER m3 ;
    RECT -0.0160 -0.0250 0.0160 0.0250 ;
  LAYER v3 ;
    RECT -0.0160 -0.0160 0.0160 0.0160 ;
  LAYER m4 ;
    RECT -0.0450 -0.0160 0.0450 0.0160 ;
END VIA3C_DB

VIA VIA3C_DC
  RESISTANCE 5.72 ;
  LAYER m3 ;
    RECT -0.0160 -0.0300 0.0160 0.0300 ;
  LAYER v3 ;
    RECT -0.0160 -0.0160 0.0160 0.0160 ;
  LAYER m4 ;
    RECT -0.0450 -0.0160 0.0450 0.0160 ;
END VIA3C_DC

VIA VIA3C_32_DA
  RESISTANCE 5.72 ;
  LAYER m3 ;
    RECT -0.0140 -0.0280 0.0140 0.0280 ;
  LAYER v3 ;
    RECT -0.0160 -0.0160 0.0160 0.0160 ;
  LAYER m4 ;
    RECT -0.0400 -0.0160 0.0400 0.0160 ;
END VIA3C_32_DA

VIA VIA3C_32_DB
  RESISTANCE 5.72 ;
  LAYER m3 ;
    RECT -0.0140 -0.0250 0.0140 0.0250 ;
  LAYER v3 ;
    RECT -0.0160 -0.0160 0.0160 0.0160 ;
  LAYER m4 ;
    RECT -0.0450 -0.0160 0.0450 0.0160 ;
END VIA3C_32_DB

VIA VIA3C_32_DC
  RESISTANCE 5.72 ;
  LAYER m3 ;
    RECT -0.0140 -0.0280 0.0140 0.0280 ;
  LAYER v3 ;
    RECT -0.0160 -0.0160 0.0160 0.0160 ;
  LAYER m4 ;
    RECT -0.0450 -0.0160 0.0450 0.0160 ;
END VIA3C_32_DC

VIA VIA4A_32_DA
  RESISTANCE 5.72 ;
  LAYER m4 ;
    RECT -0.0280 -0.0160 0.0280 0.0160 ;
  LAYER v4 ;
    RECT -0.0140 -0.0160 0.0140 0.0160 ;
  LAYER m5 ;
    RECT -0.0140 -0.0400 0.0140 0.0400 ;
END VIA4A_32_DA

VIA VIA4A_32_DB
  RESISTANCE 5.72 ;
  LAYER m4 ;
    RECT -0.0230 -0.0160 0.0230 0.0160 ;
  LAYER v4 ;
    RECT -0.0140 -0.0160 0.0140 0.0160 ;
  LAYER m5 ;
    RECT -0.0140 -0.0450 0.0140 0.0450 ;
END VIA4A_32_DB

VIA VIA4A_32_DC
  RESISTANCE 5.72 ;
  LAYER m4 ;
    RECT -0.0280 -0.0160 0.0280 0.0160 ;
  LAYER v4 ;
    RECT -0.0140 -0.0160 0.0140 0.0160 ;
  LAYER m5 ;
    RECT -0.0140 -0.0450 0.0140 0.0450 ;
END VIA4A_32_DC

VIA VIA4C_DA
  RESISTANCE 5.72 ;
  LAYER m4 ;
    RECT -0.0280 -0.0160 0.0280 0.0160 ;
  LAYER v4 ;
    RECT -0.0160 -0.0160 0.0160 0.0160 ;
  LAYER m5 ;
    RECT -0.0160 -0.0400 0.0160 0.0400 ;
END VIA4C_DA

VIA VIA4C_DB
  RESISTANCE 5.72 ;
  LAYER m4 ;
    RECT -0.0250 -0.0160 0.0250 0.0160 ;
  LAYER v4 ;
    RECT -0.0160 -0.0160 0.0160 0.0160 ;
  LAYER m5 ;
    RECT -0.0160 -0.0450 0.0160 0.0450 ;
END VIA4C_DB

VIA VIA4C_DC
  RESISTANCE 5.72 ;
  LAYER m4 ;
    RECT -0.0280 -0.0160 0.0280 0.0160 ;
  LAYER v4 ;
    RECT -0.0160 -0.0160 0.0160 0.0160 ;
  LAYER m5 ;
    RECT -0.0160 -0.0450 0.0160 0.0450 ;
END VIA4C_DC

VIA VIA6A44_DA
  RESISTANCE 5.72 ;
  LAYER m6 ;
    RECT -0.0680 -0.0220 0.0680 0.0220 ;
  LAYER v6 ;
    RECT -0.0280 -0.0300 0.0280 0.0300 ;
  LAYER m7 ;
    RECT -0.0280 -0.0620 0.0280 0.0620 ;
END VIA6A44_DA

VIA VIA6A44_DB
  RESISTANCE 5.72 ;
  LAYER m6 ;
    RECT -0.0440 -0.0220 0.0440 0.0220 ;
  LAYER v6 ;
    RECT -0.0280 -0.0300 0.0280 0.0300 ;
  LAYER m7 ;
    RECT -0.0280 -0.0720 0.0280 0.0720 ;
END VIA6A44_DB

VIA VIA6A44_DC
  RESISTANCE 5.72 ;
  LAYER m6 ;
    RECT -0.0680 -0.0220 0.0680 0.0220 ;
  LAYER v6 ;
    RECT -0.0280 -0.0300 0.0280 0.0300 ;
  LAYER m7 ;
    RECT -0.0280 -0.0720 0.0280 0.0720 ;
END VIA6A44_DC

VIA VIA7F_168
  RESISTANCE 5.72 ;
  LAYER m7 ;
    RECT -0.0750 -0.0980 0.0750 0.0980 ;
  LAYER v7 ;
    RECT -0.0370 -0.0700 0.0370 0.0700 ;
  LAYER m8 ;
    RECT -0.0650 -0.0700 0.0650 0.0700 ;
END VIA7F_168

VIA VIA2O_40
  RESISTANCE 5.72 ;
  LAYER m2 ;
    RECT -0.0510 -0.0200 0.0510 0.0200 ;
  LAYER v2 ;
    RECT -0.0420 -0.0160 0.0420 0.0160 ;
  LAYER m3 ;
    RECT -0.0420 -0.0400 0.0420 0.0400 ;
END VIA2O_40

VIA VIA2O_74
  RESISTANCE 5.72 ;
  LAYER m2 ;
    RECT -0.0510 -0.0370 0.0510 0.0370 ;
  LAYER v2 ;
    RECT -0.0420 -0.0160 0.0420 0.0160 ;
  LAYER m3 ;
    RECT -0.0420 -0.0400 0.0420 0.0400 ;
END VIA2O_74

VIA VIA5O
  RESISTANCE 5.72 ;
  LAYER m5 ;
    RECT -0.0140 -0.0420 0.0140 0.0420 ;
  LAYER v5 ;
    RECT -0.0160 -0.0300 0.0160 0.0300 ;
  LAYER m6 ;
    RECT -0.0380 -0.0300 0.0380 0.0300 ;
END VIA5O

VIA VIA6F_40
  RESISTANCE 5.72 ;
  LAYER m6 ;
    RECT -0.1000 -0.0200 0.1000 0.0200 ;
  LAYER v6 ;
    RECT -0.0840 -0.0300 0.0840 0.0300 ;
  LAYER m7 ;
    RECT -0.0840 -0.0620 0.0840 0.0620 ;
END VIA6F_40

VIA VIA6F_60
  RESISTANCE 5.72 ;
  LAYER m6 ;
    RECT -0.1000 -0.0300 0.1000 0.0300 ;
  LAYER v6 ;
    RECT -0.0840 -0.0300 0.0840 0.0300 ;
  LAYER m7 ;
    RECT -0.0840 -0.0620 0.0840 0.0620 ;
END VIA6F_60

VIA VIA6F_108
  RESISTANCE 5.72 ;
  LAYER m6 ;
    RECT -0.1000 -0.0540 0.1000 0.0540 ;
  LAYER v6 ;
    RECT -0.0840 -0.0300 0.0840 0.0300 ;
  LAYER m7 ;
    RECT -0.0840 -0.0620 0.0840 0.0620 ;
END VIA6F_108

VIA VIA6A60
  RESISTANCE 5.72 ;
  LAYER m6 ;
    RECT -0.0440 -0.0300 0.0440 0.0300 ;
  LAYER v6 ;
    RECT -0.0280 -0.0300 0.0280 0.0300 ;
  LAYER m7 ;
    RECT -0.0280 -0.0620 0.0280 0.0620 ;
END VIA6A60

VIA VIA6A108
  RESISTANCE 5.72 ;
  LAYER m6 ;
    RECT -0.0440 -0.0540 0.0440 0.0540 ;
  LAYER v6 ;
    RECT -0.0280 -0.0300 0.0280 0.0300 ;
  LAYER m7 ;
    RECT -0.0280 -0.0620 0.0280 0.0620 ;
END VIA6A108

VIA VIA7A_168
  RESISTANCE 5.72 ;
  LAYER m7 ;
    RECT -0.0840 -0.0910 0.0840 0.0910 ;
  LAYER v7 ;
    RECT -0.0370 -0.0630 0.0370 0.0630 ;
  LAYER m8 ;
    RECT -0.0650 -0.0630 0.0650 0.0630 ;
END VIA7A_168

VIA VIA4C_28
  RESISTANCE 5.72 ;
  LAYER m4 ;
    RECT -0.0250 -0.0140 0.0250 0.0140 ;
  LAYER v4 ;
    RECT -0.0160 -0.0160 0.0160 0.0160 ;
  LAYER m5 ;
    RECT -0.0160 -0.0400 0.0160 0.0400 ;
END VIA4C_28

VIA VIA3A_32
  RESISTANCE 5.72 ;
  LAYER m3 ;
    RECT -0.0160 -0.0230 0.0160 0.0230 ;
  LAYER v3 ;
    RECT -0.0160 -0.0140 0.0160 0.0140 ;
  LAYER m4 ;
    RECT -0.0400 -0.0140 0.0400 0.0140 ;
END VIA3A_32

VIA VIA5B_DA
  RESISTANCE 5.72 ;
  LAYER m5 ;
    RECT -0.0140 -0.0390 0.0140 0.0390 ;
  LAYER v5 ;
    RECT -0.0160 -0.0220 0.0160 0.0220 ;
  LAYER m6 ;
    RECT -0.0380 -0.0220 0.0380 0.0220 ;
END VIA5B_DA

VIA VIA5B_DB
  RESISTANCE 5.72 ;
  LAYER m5 ;
    RECT -0.0140 -0.0340 0.0140 0.0340 ;
  LAYER v5 ;
    RECT -0.0160 -0.0220 0.0160 0.0220 ;
  LAYER m6 ;
    RECT -0.0560 -0.0220 0.0560 0.0220 ;
END VIA5B_DB

VIA VIA5B_DC
  RESISTANCE 5.72 ;
  LAYER m5 ;
    RECT -0.0140 -0.0390 0.0140 0.0390 ;
  LAYER v5 ;
    RECT -0.0160 -0.0220 0.0160 0.0220 ;
  LAYER m6 ;
    RECT -0.0560 -0.0220 0.0560 0.0220 ;
END VIA5B_DC

VIA VIA5B_44_DA
  RESISTANCE 5.72 ;
  LAYER m5 ;
    RECT -0.0160 -0.0390 0.0160 0.0390 ;
  LAYER v5 ;
    RECT -0.0160 -0.0220 0.0160 0.0220 ;
  LAYER m6 ;
    RECT -0.0380 -0.0220 0.0380 0.0220 ;
END VIA5B_44_DA

VIA VIA5B_44_DB
  RESISTANCE 5.72 ;
  LAYER m5 ;
    RECT -0.0160 -0.0340 0.0160 0.0340 ;
  LAYER v5 ;
    RECT -0.0160 -0.0220 0.0160 0.0220 ;
  LAYER m6 ;
    RECT -0.0560 -0.0220 0.0560 0.0220 ;
END VIA5B_44_DB

VIA VIA5B_44_DC
  RESISTANCE 5.72 ;
  LAYER m5 ;
    RECT -0.0160 -0.0390 0.0160 0.0390 ;
  LAYER v5 ;
    RECT -0.0160 -0.0220 0.0160 0.0220 ;
  LAYER m6 ;
    RECT -0.0560 -0.0220 0.0560 0.0220 ;
END VIA5B_44_DC

VIA VIA7F_DA
  RESISTANCE 5.72 ;
  LAYER m7 ;
    RECT -0.0280 -0.1020 0.0280 0.1020 ;
  LAYER v7 ;
    RECT -0.0370 -0.0700 0.0370 0.0700 ;
  LAYER m8 ;
    RECT -0.0650 -0.0700 0.0650 0.0700 ;
END VIA7F_DA

VIA VIA7F_DB
  RESISTANCE 5.72 ;
  LAYER m7 ;
    RECT -0.0280 -0.0980 0.0280 0.0980 ;
  LAYER v7 ;
    RECT -0.0370 -0.0700 0.0370 0.0700 ;
  LAYER m8 ;
    RECT -0.0690 -0.0700 0.0690 0.0700 ;
END VIA7F_DB

VIA VIA1HL
  RESISTANCE 5.72 ;
  LAYER m1 ;
    RECT -0.0210 -0.0310 0.0210 0.0310 ;
  LAYER v1 ;
    RECT -0.0180 -0.0240 0.0180 0.0240 ;
  LAYER m2 ;
    RECT -0.0420 -0.0240 0.0420 0.0240 ;
END VIA1HL

VIA VIA6E
  RESISTANCE 5.72 ;
  LAYER m6 ;
    RECT -0.0910 -0.0200 0.0910 0.0200 ;
  LAYER v6 ;
    RECT -0.0750 -0.0300 0.0750 0.0300 ;
  LAYER m7 ;
    RECT -0.0750 -0.0620 0.0750 0.0620 ;
END VIA6E

VIA VIA6E_44
  RESISTANCE 5.72 ;
  LAYER m6 ;
    RECT -0.0910 -0.0220 0.0910 0.0220 ;
  LAYER v6 ;
    RECT -0.0750 -0.0300 0.0750 0.0300 ;
  LAYER m7 ;
    RECT -0.0750 -0.0620 0.0750 0.0620 ;
END VIA6E_44

VIA VIA6E_90
  RESISTANCE 5.72 ;
  LAYER m6 ;
    RECT -0.0910 -0.0450 0.0910 0.0450 ;
  LAYER v6 ;
    RECT -0.0750 -0.0300 0.0750 0.0300 ;
  LAYER m7 ;
    RECT -0.0750 -0.0620 0.0750 0.0620 ;
END VIA6E_90

VIA VIA6E_108
  RESISTANCE 5.72 ;
  LAYER m6 ;
    RECT -0.0910 -0.0540 0.0910 0.0540 ;
  LAYER v6 ;
    RECT -0.0750 -0.0300 0.0750 0.0300 ;
  LAYER m7 ;
    RECT -0.0750 -0.0620 0.0750 0.0620 ;
END VIA6E_108

VIA VIA7F_DC
  RESISTANCE 5.72 ;
  LAYER m7 ;
    RECT -0.0280 -0.1020 0.0280 0.1020 ;
  LAYER v7 ;
    RECT -0.0370 -0.0700 0.0370 0.0700 ;
  LAYER m8 ;
    RECT -0.0690 -0.0700 0.0690 0.0700 ;
END VIA7F_DC

VIA VIA1HA
  RESISTANCE 5.72 ;
  LAYER m1 ;
    RECT -0.0210 -0.0250 0.0210 0.0250 ;
  LAYER v1 ;
    RECT -0.0180 -0.0180 0.0180 0.0180 ;
  LAYER m2 ;
    RECT -0.0420 -0.0180 0.0420 0.0180 ;
END VIA1HA

VIA VIA1HK
  RESISTANCE 5.72 ;
  LAYER m1 ;
    RECT -0.0210 -0.0520 0.0210 0.0520 ;
  LAYER v1 ;
    RECT -0.0180 -0.0350 0.0180 0.0350 ;
  LAYER m2 ;
    RECT -0.0420 -0.0350 0.0420 0.0350 ;
END VIA1HK

VIA VIA1S
  RESISTANCE 5.72 ;
  LAYER m1 ;
    RECT -0.0210 -0.0450 0.0210 0.0450 ;
  LAYER v1 ;
    RECT -0.0180 -0.0380 0.0180 0.0380 ;
  LAYER m2 ;
    RECT -0.0420 -0.0380 0.0420 0.0380 ;
END VIA1S

VIA TV1A
  DEFAULT 
  RESISTANCE 5.72 ;
  LAYER tm1 ;
    RECT -6.0000 -18.0000 6.0000 18.0000 ;
  LAYER tv1 ;
    RECT -3.0000 -15.0000 3.0000 15.0000 ;
  LAYER c4 ;
    RECT -6.0000 -18.0000 6.0000 18.0000 ;
END TV1A

VIA VIA9A_R
  RESISTANCE 5.72 ;
  LAYER m9 ;
    RECT -1.0650 -0.5400 1.0650 0.5400 ;
  LAYER v9 ;
    RECT -0.9250 -0.4000 0.9250 0.4000 ;
  LAYER tm1 ;
    RECT -3.9250 -3.4000 3.9250 3.4000 ;
END VIA9A_R

VIA VIA9B_R
  RESISTANCE 5.72 ;
  LAYER m9 ;
    RECT -3.8400 -0.5400 3.8400 0.5400 ;
  LAYER v9 ;
    RECT -3.7000 -0.4000 3.7000 0.4000 ;
  LAYER tm1 ;
    RECT -6.7000 -3.4000 6.7000 3.4000 ;
END VIA9B_R

VIA VIA9C_R
  RESISTANCE 5.72 ;
  LAYER m9 ;
    RECT -1.9900 -0.5400 1.9900 0.5400 ;
  LAYER v9 ;
    RECT -1.8500 -0.4000 1.8500 0.4000 ;
  LAYER tm1 ;
    RECT -4.8500 -3.4000 4.8500 3.4000 ;
END VIA9C_R

VIARULE VCNAX GENERATE
  LAYER gcn ;
    ENCLOSURE 0.006 0.002 ;
  LAYER m0 ;
    ENCLOSURE 0.022 0 ;
  LAYER vcn ;
    RECT -0.0210 -0.0140 0.0210 0.0140 ;
    SPACING 0.042 BY 0.028 ;
    RESISTANCE 5.72 ;
END VCNAX

VIARULE VIA0AX GENERATE
  LAYER m0 ;
    ENCLOSURE 0.014 0 ;
  LAYER m1 ;
    ENCLOSURE 0 0.014 ;
  LAYER v0 ;
    RECT -0.0210 -0.0140 0.0210 0.0140 ;
    SPACING 0.042 BY 0.028 ;
    RESISTANCE 5.72 ;
END VIA0AX

VIARULE VCNB GENERATE
  LAYER gcn ;
    ENCLOSURE 0.006 -0.007 ;
  LAYER m0 ;
    ENCLOSURE 0.022 0 ;
  LAYER vcn ;
    RECT -0.0210 -0.0230 0.0210 0.0230 ;
    SPACING 0.042 BY 0.046 ;
    RESISTANCE 5.72 ;
END VCNB

VIARULE VIA0CX GENERATE
  LAYER m0 ;
    ENCLOSURE 0.014 0 ;
  LAYER m1 ;
    ENCLOSURE 0 0.014 ;
  LAYER v0 ;
    RECT -0.0210 -0.0200 0.0210 0.0200 ;
    SPACING 0.042 BY 0.04 ;
    RESISTANCE 5.72 ;
END VIA0CX

VIARULE VIA1A GENERATE
  LAYER m1 ;
    ENCLOSURE 0.003 0.007 ;
  LAYER m2 ;
    ENCLOSURE 0.024 0 ;
  LAYER v1 ;
    RECT -0.0180 -0.0140 0.0180 0.0140 ;
    SPACING 0.036 BY 0.028 ;
    RESISTANCE 5.72 ;
END VIA1A

VIARULE VIA1F GENERATE
  LAYER m1 ;
    ENCLOSURE 0.003 0.007 ;
  LAYER m2 ;
    ENCLOSURE 0.024 0 ;
  LAYER v1 ;
    RECT -0.0180 -0.0200 0.0180 0.0200 ;
    SPACING 0.036 BY 0.04 ;
    RESISTANCE 5.72 ;
END VIA1F

VIARULE VIA1V GENERATE
  LAYER m1 ;
    ENCLOSURE 0.003 0.007 ;
  LAYER m2 ;
    ENCLOSURE 0.024 0 ;
  LAYER v1 ;
    RECT -0.0180 -0.0370 0.0180 0.0370 ;
    SPACING 0.036 BY 0.074 ;
    RESISTANCE 5.72 ;
END VIA1V

VIARULE VIA0A GENERATE
  LAYER m0 ;
    ENCLOSURE 0.014 0 ;
  LAYER m1 ;
    ENCLOSURE 0 0.014 ;
  LAYER v0 ;
    RECT -0.0210 -0.0210 0.0210 0.0210 ;
    SPACING 0.042 BY 0.042 ;
    RESISTANCE 5.72 ;
END VIA0A

VIARULE VIA0B GENERATE
  LAYER m0 ;
    ENCLOSURE 0.014 0 ;
  LAYER m1 ;
    ENCLOSURE 0 0.014 ;
  LAYER v0 ;
    RECT -0.0210 -0.0230 0.0210 0.0230 ;
    SPACING 0.042 BY 0.046 ;
    RESISTANCE 5.72 ;
END VIA0B

VIARULE VIA2B GENERATE
  LAYER m2 ;
    ENCLOSURE 0.009 -0.002 ;
  LAYER m3 ;
    ENCLOSURE 0 0.024 ;
  LAYER v2 ;
    RECT -0.0150 -0.0160 0.0150 0.0160 ;
    SPACING 0.054 BY 0.056 ;
    RESISTANCE 5.72 ;
END VIA2B

VIARULE VIA2F GENERATE
  LAYER m2 ;
    ENCLOSURE 0.009 -0.002 ;
  LAYER m3 ;
    ENCLOSURE 0 0.024 ;
  LAYER v2 ;
    RECT -0.0200 -0.0160 0.0200 0.0160 ;
    SPACING 0.064 BY 0.056 ;
    RESISTANCE 5.72 ;
END VIA2F

VIARULE VIA3B GENERATE
  LAYER m3 ;
    ENCLOSURE -0.002 0.009 ;
  LAYER m4 ;
    ENCLOSURE 0.024 0 ;
  LAYER v3 ;
    RECT -0.0160 -0.0150 0.0160 0.0150 ;
    SPACING 0.056 BY 0.054 ;
    RESISTANCE 5.72 ;
END VIA3B

VIARULE VIA4B GENERATE
  LAYER m4 ;
    ENCLOSURE 0.009 -0.002 ;
  LAYER m5 ;
    ENCLOSURE 0 0.024 ;
  LAYER v4 ;
    RECT -0.0150 -0.0160 0.0150 0.0160 ;
    SPACING 0.054 BY 0.056 ;
    RESISTANCE 5.72 ;
END VIA4B

VIARULE VIA4F GENERATE
  LAYER m4 ;
    ENCLOSURE 0.009 -0.002 ;
  LAYER m5 ;
    ENCLOSURE 0 0.024 ;
  LAYER v4 ;
    RECT -0.0200 -0.0160 0.0200 0.0160 ;
    SPACING 0.064 BY 0.056 ;
    RESISTANCE 5.72 ;
END VIA4F

VIARULE VIA8A GENERATE
  LAYER m8 ;
    ENCLOSURE 0.13 0.13 ;
  LAYER m9 ;
    ENCLOSURE 0.05 0.13 ;
  LAYER v8 ;
    RECT -0.2200 -0.2200 0.2200 0.2200 ;
    SPACING 1.08 BY 1.08 ;
    RESISTANCE 5.72 ;
END VIA8A

VIARULE VIA8C GENERATE
  LAYER m8 ;
    ENCLOSURE 0.08 0.08 ;
  LAYER m9 ;
    ENCLOSURE 0.05 0.13 ;
  LAYER v8 ;
    RECT -0.4400 -0.2200 0.4400 0.2200 ;
    SPACING 1.52 BY 1.08 ;
    RESISTANCE 5.72 ;
END VIA8C

VIARULE VIA2A GENERATE
  LAYER m2 ;
    ENCLOSURE 0.009 -0.002 ;
  LAYER m3 ;
    ENCLOSURE 0 0.024 ;
  LAYER v2 ;
    RECT -0.0140 -0.0160 0.0140 0.0160 ;
    SPACING 0.028 BY 0.032 ;
    RESISTANCE 5.72 ;
END VIA2A

VIARULE VIA2L40 GENERATE
  LAYER m2 ;
    ENCLOSURE 0.009 0.004 ;
  LAYER m3 ;
    ENCLOSURE 0 0.024 ;
  LAYER v2 ;
    RECT -0.0340 -0.0160 0.0340 0.0160 ;
    SPACING 0.068 BY 0.032 ;
    RESISTANCE 5.72 ;
END VIA2L40

VIARULE VIA2L74 GENERATE
  LAYER m2 ;
    ENCLOSURE 0.009 0.021 ;
  LAYER m3 ;
    ENCLOSURE 0 0.024 ;
  LAYER v2 ;
    RECT -0.0340 -0.0160 0.0340 0.0160 ;
    SPACING 0.068 BY 0.032 ;
    RESISTANCE 5.72 ;
END VIA2L74

VIARULE VIA9A GENERATE
  LAYER m9 ;
    ENCLOSURE 0.14 0.14 ;
  LAYER tm1 ;
    ENCLOSURE 3 3 ;
  LAYER v9 ;
    RECT -0.4000 -0.9250 0.4000 0.9250 ;
    SPACING 2.8 BY 3.85 ;
    RESISTANCE 5.72 ;
END VIA9A

VIARULE VIA9B GENERATE
  LAYER m9 ;
    ENCLOSURE 0.14 0.14 ;
  LAYER tm1 ;
    ENCLOSURE 3 3 ;
  LAYER v9 ;
    RECT -0.4000 -3.7000 0.4000 3.7000 ;
    SPACING 2.8 BY 9.4 ;
    RESISTANCE 5.72 ;
END VIA9B

VIARULE VIA9C GENERATE
  LAYER m9 ;
    ENCLOSURE 0.14 0.14 ;
  LAYER tm1 ;
    ENCLOSURE 3 3 ;
  LAYER v9 ;
    RECT -0.4000 -1.8500 0.4000 1.8500 ;
    SPACING 2.8 BY 5.7 ;
    RESISTANCE 5.72 ;
END VIA9C

VIARULE VIA2S GENERATE
  LAYER m2 ;
    ENCLOSURE 0.009 -0.002 ;
  LAYER m3 ;
    ENCLOSURE 0 0.024 ;
  LAYER v2 ;
    RECT -0.0380 -0.0160 0.0380 0.0160 ;
    SPACING 0.1 BY 0.056 ;
    RESISTANCE 5.72 ;
END VIA2S

VIARULE VIA3A GENERATE
  LAYER m3 ;
    ENCLOSURE -0.002 0.009 ;
  LAYER m4 ;
    ENCLOSURE 0.024 0 ;
  LAYER v3 ;
    RECT -0.0160 -0.0140 0.0160 0.0140 ;
    SPACING 0.032 BY 0.028 ;
    RESISTANCE 5.72 ;
END VIA3A

VIARULE VIA3F GENERATE
  LAYER m3 ;
    ENCLOSURE -0.002 0.009 ;
  LAYER m4 ;
    ENCLOSURE 0.024 0 ;
  LAYER v3 ;
    RECT -0.0160 -0.0200 0.0160 0.0200 ;
    SPACING 0.032 BY 0.04 ;
    RESISTANCE 5.72 ;
END VIA3F

VIARULE VIA3RY GENERATE
  LAYER m3 ;
    ENCLOSURE 0.012 0.009 ;
  LAYER m4 ;
    ENCLOSURE 0.024 0 ;
  LAYER v3 ;
    RECT -0.0220 -0.0300 0.0220 0.0300 ;
    SPACING 0.044 BY 0.06 ;
    RESISTANCE 5.72 ;
END VIA3RY

VIARULE VIA3VX GENERATE
  LAYER m3 ;
    ENCLOSURE 0.014 0.009 ;
  LAYER m4 ;
    ENCLOSURE 0.024 0 ;
  LAYER v3 ;
    RECT -0.0200 -0.0330 0.0200 0.0330 ;
    SPACING 0.04 BY 0.066 ;
    RESISTANCE 5.72 ;
END VIA3VX

VIARULE VIA3NX GENERATE
  LAYER m3 ;
    ENCLOSURE 0.015 0.009 ;
  LAYER m4 ;
    ENCLOSURE 0.024 0 ;
  LAYER v3 ;
    RECT -0.0190 -0.0370 0.0190 0.0370 ;
    SPACING 0.038 BY 0.074 ;
    RESISTANCE 5.72 ;
END VIA3NX

VIARULE VIA4A GENERATE
  LAYER m4 ;
    ENCLOSURE 0.009 -0.002 ;
  LAYER m5 ;
    ENCLOSURE 0 0.024 ;
  LAYER v4 ;
    RECT -0.0140 -0.0160 0.0140 0.0160 ;
    SPACING 0.028 BY 0.032 ;
    RESISTANCE 5.72 ;
END VIA4A

VIARULE VIA4L40 GENERATE
  LAYER m4 ;
    ENCLOSURE 0.009 0.004 ;
  LAYER m5 ;
    ENCLOSURE 0 0.024 ;
  LAYER v4 ;
    RECT -0.0340 -0.0160 0.0340 0.0160 ;
    SPACING 0.068 BY 0.032 ;
    RESISTANCE 5.72 ;
END VIA4L40

VIARULE VIA4L60 GENERATE
  LAYER m4 ;
    ENCLOSURE 0.009 0.014 ;
  LAYER m5 ;
    ENCLOSURE 0 0.024 ;
  LAYER v4 ;
    RECT -0.0340 -0.0160 0.0340 0.0160 ;
    SPACING 0.068 BY 0.032 ;
    RESISTANCE 5.72 ;
END VIA4L60

VIARULE VIA4L66 GENERATE
  LAYER m4 ;
    ENCLOSURE 0.009 0.017 ;
  LAYER m5 ;
    ENCLOSURE 0 0.024 ;
  LAYER v4 ;
    RECT -0.0340 -0.0160 0.0340 0.0160 ;
    SPACING 0.068 BY 0.032 ;
    RESISTANCE 5.72 ;
END VIA4L66

VIARULE VIA4L74 GENERATE
  LAYER m4 ;
    ENCLOSURE 0.009 0.021 ;
  LAYER m5 ;
    ENCLOSURE 0 0.024 ;
  LAYER v4 ;
    RECT -0.0340 -0.0160 0.0340 0.0160 ;
    SPACING 0.068 BY 0.032 ;
    RESISTANCE 5.72 ;
END VIA4L74

VIARULE VIA3GX GENERATE
  LAYER m3 ;
    ENCLOSURE -0.002 0.009 ;
  LAYER m4 ;
    ENCLOSURE 0.024 0 ;
  LAYER v3 ;
    RECT -0.0260 -0.0230 0.0260 0.0230 ;
    SPACING 0.076 BY 0.07 ;
    RESISTANCE 5.72 ;
END VIA3GX

VIARULE VIA5A GENERATE
  LAYER m5 ;
    ENCLOSURE -0.002 0.012 ;
  LAYER m6 ;
    ENCLOSURE 0.022 0 ;
  LAYER v5 ;
    RECT -0.0160 -0.0200 0.0160 0.0200 ;
    SPACING 0.032 BY 0.04 ;
    RESISTANCE 5.72 ;
END VIA5A

VIARULE VIA5B GENERATE
  LAYER m5 ;
    ENCLOSURE -0.002 0.012 ;
  LAYER m6 ;
    ENCLOSURE 0.022 0 ;
  LAYER v5 ;
    RECT -0.0160 -0.0220 0.0160 0.0220 ;
    SPACING 0.032 BY 0.044 ;
    RESISTANCE 5.72 ;
END VIA5B

VIARULE VIA4S GENERATE
  LAYER m4 ;
    ENCLOSURE 0.009 -0.002 ;
  LAYER m5 ;
    ENCLOSURE 0 0.024 ;
  LAYER v4 ;
    RECT -0.0380 -0.0160 0.0380 0.0160 ;
    SPACING 0.1 BY 0.056 ;
    RESISTANCE 5.72 ;
END VIA4S

VIARULE VIA5A_30 GENERATE
  LAYER m5 ;
    ENCLOSURE -0.001 0.012 ;
  LAYER m6 ;
    ENCLOSURE 0.022 0 ;
  LAYER v5 ;
    RECT -0.0160 -0.0200 0.0160 0.0200 ;
    SPACING 0.032 BY 0.04 ;
    RESISTANCE 5.72 ;
END VIA5A_30

VIARULE VIA5V GENERATE
  LAYER m5 ;
    ENCLOSURE -0.002 0.012 ;
  LAYER m6 ;
    ENCLOSURE 0.022 0 ;
  LAYER v5 ;
    RECT -0.0240 -0.0450 0.0240 0.0450 ;
    SPACING 0.048 BY 0.09 ;
    RESISTANCE 5.72 ;
END VIA5V

VIARULE VIA3RX GENERATE
  LAYER m3 ;
    ENCLOSURE 0.001 0.009 ;
  LAYER m4 ;
    ENCLOSURE 0.024 0 ;
  LAYER v3 ;
    RECT -0.0190 -0.0300 0.0190 0.0300 ;
    SPACING 0.062 BY 0.084 ;
    RESISTANCE 5.72 ;
END VIA3RX

VIARULE VIA5R GENERATE
  LAYER m5 ;
    ENCLOSURE -0.002 0.012 ;
  LAYER m6 ;
    ENCLOSURE 0.022 0 ;
  LAYER v5 ;
    RECT -0.0160 -0.0450 0.0160 0.0450 ;
    SPACING 0.032 BY 0.09 ;
    RESISTANCE 5.72 ;
END VIA5R

VIARULE VIA6A40 GENERATE
  LAYER m6 ;
    ENCLOSURE 0.016 -0.01 ;
  LAYER m7 ;
    ENCLOSURE 0 0.032 ;
  LAYER v6 ;
    RECT -0.0280 -0.0300 0.0280 0.0300 ;
    SPACING 0.056 BY 0.06 ;
    RESISTANCE 5.72 ;
END VIA6A40

VIARULE VIA6A44 GENERATE
  LAYER m6 ;
    ENCLOSURE 0.016 -0.008 ;
  LAYER m7 ;
    ENCLOSURE 0 0.032 ;
  LAYER v6 ;
    RECT -0.0280 -0.0300 0.0280 0.0300 ;
    SPACING 0.056 BY 0.06 ;
    RESISTANCE 5.72 ;
END VIA6A44

VIARULE VIA6F GENERATE
  LAYER m6 ;
    ENCLOSURE 0.016 0.015 ;
  LAYER m7 ;
    ENCLOSURE 0 0.032 ;
  LAYER v6 ;
    RECT -0.0840 -0.0300 0.0840 0.0300 ;
    SPACING 0.168 BY 0.06 ;
    RESISTANCE 5.72 ;
END VIA6F

VIARULE VIA5RP GENERATE
  LAYER m5 ;
    ENCLOSURE -0.002 0.012 ;
  LAYER m6 ;
    ENCLOSURE 0.022 0 ;
  LAYER v5 ;
    RECT -0.0220 -0.0450 0.0220 0.0450 ;
    SPACING 0.044 BY 0.09 ;
    RESISTANCE 5.72 ;
END VIA5RP

VIARULE VIA5W GENERATE
  LAYER m5 ;
    ENCLOSURE -0.002 0.012 ;
  LAYER m6 ;
    ENCLOSURE 0.022 0 ;
  LAYER v5 ;
    RECT -0.0340 -0.0220 0.0340 0.0220 ;
    SPACING 0.068 BY 0.044 ;
    RESISTANCE 5.72 ;
END VIA5W

VIARULE VIA7E GENERATE
  LAYER m7 ;
    ENCLOSURE -0.009 0.126 ;
  LAYER m8 ;
    ENCLOSURE 0.028 0.028 ;
  LAYER v7 ;
    RECT -0.0420 -0.0630 0.0420 0.0630 ;
    SPACING 0.084 BY 0.126 ;
    RESISTANCE 5.72 ;
END VIA7E

VIARULE VIA4J GENERATE
  LAYER m4 ;
    ENCLOSURE 0.009 -0.002 ;
  LAYER m5 ;
    ENCLOSURE 0 0.024 ;
  LAYER v4 ;
    RECT -0.0280 -0.0160 0.0280 0.0160 ;
    SPACING 0.08 BY 0.056 ;
    RESISTANCE 5.72 ;
END VIA4J

VIARULE VIA7A GENERATE
  LAYER m7 ;
    ENCLOSURE -0.009 0.028 ;
  LAYER m8 ;
    ENCLOSURE 0.028 0 ;
  LAYER v7 ;
    RECT -0.0370 -0.0630 0.0370 0.0630 ;
    SPACING 0.074 BY 0.126 ;
    RESISTANCE 5.72 ;
END VIA7A

VIARULE VIA7D GENERATE
  LAYER m7 ;
    ENCLOSURE -0.009 0.028 ;
  LAYER m8 ;
    ENCLOSURE 0.028 0 ;
  LAYER v7 ;
    RECT -0.0900 -0.0630 0.0900 0.0630 ;
    SPACING 0.33 BY 0.276 ;
    RESISTANCE 5.72 ;
END VIA7D

VIARULE VIA3G GENERATE
  LAYER m3 ;
    ENCLOSURE -0.002 0.009 ;
  LAYER m4 ;
    ENCLOSURE 0.024 0 ;
  LAYER v3 ;
    RECT -0.0160 -0.0230 0.0160 0.0230 ;
    SPACING 0.056 BY 0.07 ;
    RESISTANCE 5.72 ;
END VIA3G

VIARULE VIA2JX GENERATE
  LAYER m2 ;
    ENCLOSURE 0.009 -0.002 ;
  LAYER m3 ;
    ENCLOSURE 0 0.024 ;
  LAYER v2 ;
    RECT -0.0280 -0.0230 0.0280 0.0230 ;
    SPACING 0.056 BY 0.046 ;
    RESISTANCE 5.72 ;
END VIA2JX

VIARULE VIA2R GENERATE
  LAYER m2 ;
    ENCLOSURE 0.009 -0.002 ;
  LAYER m3 ;
    ENCLOSURE 0 0.024 ;
  LAYER v2 ;
    RECT -0.0300 -0.0160 0.0300 0.0160 ;
    SPACING 0.06 BY 0.032 ;
    RESISTANCE 5.72 ;
END VIA2R

VIARULE VIA2RX GENERATE
  LAYER m2 ;
    ENCLOSURE 0.009 0.002 ;
  LAYER m3 ;
    ENCLOSURE 0 0.024 ;
  LAYER v2 ;
    RECT -0.0300 -0.0190 0.0300 0.0190 ;
    SPACING 0.06 BY 0.038 ;
    RESISTANCE 5.72 ;
END VIA2RX

VIARULE VIA2RY GENERATE
  LAYER m2 ;
    ENCLOSURE 0.009 -0.002 ;
  LAYER m3 ;
    ENCLOSURE 0 0.024 ;
  LAYER v2 ;
    RECT -0.0300 -0.0220 0.0300 0.0220 ;
    SPACING 0.06 BY 0.044 ;
    RESISTANCE 5.72 ;
END VIA2RY

VIARULE VIA4JX GENERATE
  LAYER m4 ;
    ENCLOSURE 0.009 -0.003 ;
  LAYER m5 ;
    ENCLOSURE 0 0.024 ;
  LAYER v4 ;
    RECT -0.0280 -0.0230 0.0280 0.0230 ;
    SPACING 0.08 BY 0.07 ;
    RESISTANCE 5.72 ;
END VIA4JX

VIARULE VIA4R GENERATE
  LAYER m4 ;
    ENCLOSURE 0.009 -0.002 ;
  LAYER m5 ;
    ENCLOSURE 0 0.024 ;
  LAYER v4 ;
    RECT -0.0300 -0.0160 0.0300 0.0160 ;
    SPACING 0.084 BY 0.056 ;
    RESISTANCE 5.72 ;
END VIA4R

VIARULE VIA4RY GENERATE
  LAYER m4 ;
    ENCLOSURE 0.009 -0.002 ;
  LAYER m5 ;
    ENCLOSURE 0 0.024 ;
  LAYER v4 ;
    RECT -0.0300 -0.0220 0.0300 0.0220 ;
    SPACING 0.084 BY 0.068 ;
    RESISTANCE 5.72 ;
END VIA4RY

VIARULE VIA3A_30 GENERATE
  LAYER m3 ;
    ENCLOSURE -0.001 0.009 ;
  LAYER m4 ;
    ENCLOSURE 0.024 0 ;
  LAYER v3 ;
    RECT -0.0160 -0.0140 0.0160 0.0140 ;
    SPACING 0.032 BY 0.028 ;
    RESISTANCE 5.72 ;
END VIA3A_30

VIARULE VIA3A_40 GENERATE
  LAYER m3 ;
    ENCLOSURE 0.004 0.009 ;
  LAYER m4 ;
    ENCLOSURE 0.024 0 ;
  LAYER v3 ;
    RECT -0.0160 -0.0140 0.0160 0.0140 ;
    SPACING 0.032 BY 0.028 ;
    RESISTANCE 5.72 ;
END VIA3A_40

VIARULE VIA5B_44 GENERATE
  LAYER m5 ;
    ENCLOSURE 0 0.012 ;
  LAYER m6 ;
    ENCLOSURE 0.022 0 ;
  LAYER v5 ;
    RECT -0.0160 -0.0220 0.0160 0.0220 ;
    SPACING 0.032 BY 0.044 ;
    RESISTANCE 5.72 ;
END VIA5B_44

VIARULE VIA5A_40 GENERATE
  LAYER m5 ;
    ENCLOSURE 0.004 0.012 ;
  LAYER m6 ;
    ENCLOSURE 0.022 0 ;
  LAYER v5 ;
    RECT -0.0160 -0.0200 0.0160 0.0200 ;
    SPACING 0.032 BY 0.04 ;
    RESISTANCE 5.72 ;
END VIA5A_40

VIARULE VIA4F_30 GENERATE
  LAYER m4 ;
    ENCLOSURE 0.009 -0.001 ;
  LAYER m5 ;
    ENCLOSURE 0 0.024 ;
  LAYER v4 ;
    RECT -0.0200 -0.0160 0.0200 0.0160 ;
    SPACING 0.064 BY 0.056 ;
    RESISTANCE 5.72 ;
END VIA4F_30

VIARULE VIA4B_30 GENERATE
  LAYER m4 ;
    ENCLOSURE 0.009 -0.001 ;
  LAYER m5 ;
    ENCLOSURE 0 0.024 ;
  LAYER v4 ;
    RECT -0.0150 -0.0160 0.0150 0.0160 ;
    SPACING 0.054 BY 0.056 ;
    RESISTANCE 5.72 ;
END VIA4B_30

VIARULE VIA3B_30 GENERATE
  LAYER m3 ;
    ENCLOSURE -0.001 0.009 ;
  LAYER m4 ;
    ENCLOSURE 0.024 0 ;
  LAYER v3 ;
    RECT -0.0160 -0.0150 0.0160 0.0150 ;
    SPACING 0.056 BY 0.054 ;
    RESISTANCE 5.72 ;
END VIA3B_30

VIARULE VIA3B_40 GENERATE
  LAYER m3 ;
    ENCLOSURE 0.004 0.009 ;
  LAYER m4 ;
    ENCLOSURE 0.024 0 ;
  LAYER v3 ;
    RECT -0.0160 -0.0150 0.0160 0.0150 ;
    SPACING 0.056 BY 0.054 ;
    RESISTANCE 5.72 ;
END VIA3B_40

VIARULE VIA5B_4044 GENERATE
  LAYER m5 ;
    ENCLOSURE 0.004 0.012 ;
  LAYER m6 ;
    ENCLOSURE 0.022 0 ;
  LAYER v5 ;
    RECT -0.0160 -0.0220 0.0160 0.0220 ;
    SPACING 0.032 BY 0.044 ;
    RESISTANCE 5.72 ;
END VIA5B_4044

VIARULE VIA4A_30 GENERATE
  LAYER m4 ;
    ENCLOSURE 0.009 -0.001 ;
  LAYER m5 ;
    ENCLOSURE 0 0.024 ;
  LAYER v4 ;
    RECT -0.0140 -0.0160 0.0140 0.0160 ;
    SPACING 0.028 BY 0.032 ;
    RESISTANCE 5.72 ;
END VIA4A_30

VIARULE VIA5BP GENERATE
  LAYER m5 ;
    ENCLOSURE -0.002 0.012 ;
  LAYER m6 ;
    ENCLOSURE 0.022 0 ;
  LAYER v5 ;
    RECT -0.0220 -0.0220 0.0220 0.0220 ;
    SPACING 0.044 BY 0.044 ;
    RESISTANCE 5.72 ;
END VIA5BP

VIARULE VIA5MP GENERATE
  LAYER m5 ;
    ENCLOSURE 0.001 0.012 ;
  LAYER m6 ;
    ENCLOSURE 0.022 0 ;
  LAYER v5 ;
    RECT -0.0220 -0.0540 0.0220 0.0540 ;
    SPACING 0.044 BY 0.108 ;
    RESISTANCE 5.72 ;
END VIA5MP

VIARULE VIA4O GENERATE
  LAYER m4 ;
    ENCLOSURE 0.009 -0.002 ;
  LAYER m5 ;
    ENCLOSURE 0 0.024 ;
  LAYER v4 ;
    RECT -0.0420 -0.0160 0.0420 0.0160 ;
    SPACING 0.108 BY 0.056 ;
    RESISTANCE 5.72 ;
END VIA4O

VIARULE VIA2J GENERATE
  LAYER m2 ;
    ENCLOSURE 0.009 -0.002 ;
  LAYER m3 ;
    ENCLOSURE 0 0.024 ;
  LAYER v2 ;
    RECT -0.0280 -0.0160 0.0280 0.0160 ;
    SPACING 0.056 BY 0.032 ;
    RESISTANCE 5.72 ;
END VIA2J

VIARULE VIA3N GENERATE
  LAYER m3 ;
    ENCLOSURE -0.002 0.009 ;
  LAYER m4 ;
    ENCLOSURE 0.024 0 ;
  LAYER v3 ;
    RECT -0.0160 -0.0330 0.0160 0.0330 ;
    SPACING 0.032 BY 0.066 ;
    RESISTANCE 5.72 ;
END VIA3N

VIARULE VIA2TIE68 GENERATE
  LAYER m2 ;
    ENCLOSURE 0.009 -0.002 ;
  LAYER m3 ;
    ENCLOSURE 0 0.024 ;
  LAYER v2 ;
    RECT -0.0340 -0.0160 0.0340 0.0160 ;
    SPACING 0.068 BY 0.032 ;
    RESISTANCE 5.72 ;
END VIA2TIE68

VIARULE VIA2O GENERATE
  LAYER m2 ;
    ENCLOSURE 0.009 -0.002 ;
  LAYER m3 ;
    ENCLOSURE 0 0.024 ;
  LAYER v2 ;
    RECT -0.0420 -0.0160 0.0420 0.0160 ;
    SPACING 0.084 BY 0.032 ;
    RESISTANCE 5.72 ;
END VIA2O

VIARULE VIA3HL GENERATE
  LAYER m3 ;
    ENCLOSURE 0 0.009 ;
  LAYER m4 ;
    ENCLOSURE 0.024 0.006 ;
  LAYER v3 ;
    RECT -0.0160 -0.0240 0.0160 0.0240 ;
    SPACING 0.032 BY 0.048 ;
    RESISTANCE 5.72 ;
END VIA3HL

VIARULE VIA4RX GENERATE
  LAYER m4 ;
    ENCLOSURE 0.009 0 ;
  LAYER m5 ;
    ENCLOSURE 0 0.024 ;
  LAYER v4 ;
    RECT -0.0300 -0.0190 0.0300 0.0190 ;
    SPACING 0.084 BY 0.062 ;
    RESISTANCE 5.72 ;
END VIA4RX

VIARULE VIA7C GENERATE
  LAYER m7 ;
    ENCLOSURE -0.009 0.028 ;
  LAYER m8 ;
    ENCLOSURE 0.028 0 ;
  LAYER v7 ;
    RECT -0.0630 -0.0630 0.0630 0.0630 ;
    SPACING 0.252 BY 0.252 ;
    RESISTANCE 5.72 ;
END VIA7C

VIARULE VIA2HL GENERATE
  LAYER m2 ;
    ENCLOSURE 0 -0.002 ;
  LAYER m3 ;
    ENCLOSURE 0.006 0.024 ;
  LAYER v2 ;
    RECT -0.0240 -0.0160 0.0240 0.0160 ;
    SPACING 0.048 BY 0.032 ;
    RESISTANCE 5.72 ;
END VIA2HL

VIARULE VIA3S GENERATE
  LAYER m3 ;
    ENCLOSURE -0.002 0.009 ;
  LAYER m4 ;
    ENCLOSURE 0.024 0 ;
  LAYER v3 ;
    RECT -0.0160 -0.0380 0.0160 0.0380 ;
    SPACING 0.032 BY 0.076 ;
    RESISTANCE 5.72 ;
END VIA3S

VIARULE VIA3D GENERATE
  LAYER m3 ;
    ENCLOSURE -0.002 0.009 ;
  LAYER m4 ;
    ENCLOSURE 0.024 0 ;
  LAYER v3 ;
    RECT -0.0160 -0.0180 0.0160 0.0180 ;
    SPACING 0.032 BY 0.036 ;
    RESISTANCE 5.72 ;
END VIA3D

VIARULE VIA5A_32 GENERATE
  LAYER m5 ;
    ENCLOSURE 0 0.012 ;
  LAYER m6 ;
    ENCLOSURE 0.022 0 ;
  LAYER v5 ;
    RECT -0.0160 -0.0200 0.0160 0.0200 ;
    SPACING 0.032 BY 0.04 ;
    RESISTANCE 5.72 ;
END VIA5A_32

VIARULE VIA2C GENERATE
  LAYER m2 ;
    ENCLOSURE 0.009 -0.002 ;
  LAYER m3 ;
    ENCLOSURE 0 0.024 ;
  LAYER v2 ;
    RECT -0.0160 -0.0160 0.0160 0.0160 ;
    SPACING 0.032 BY 0.032 ;
    RESISTANCE 5.72 ;
END VIA2C

VIARULE VIA4C GENERATE
  LAYER m4 ;
    ENCLOSURE 0.009 0 ;
  LAYER m5 ;
    ENCLOSURE 0 0.024 ;
  LAYER v4 ;
    RECT -0.0160 -0.0160 0.0160 0.0160 ;
    SPACING 0.032 BY 0.032 ;
    RESISTANCE 5.72 ;
END VIA4C

VIARULE VIA3O GENERATE
  LAYER m3 ;
    ENCLOSURE -0.002 0.009 ;
  LAYER m4 ;
    ENCLOSURE 0.024 0 ;
  LAYER v3 ;
    RECT -0.0160 -0.0420 0.0160 0.0420 ;
    SPACING 0.032 BY 0.084 ;
    RESISTANCE 5.72 ;
END VIA3O

VIARULE VIA3C GENERATE
  LAYER m3 ;
    ENCLOSURE 0 0.009 ;
  LAYER m4 ;
    ENCLOSURE 0.024 0 ;
  LAYER v3 ;
    RECT -0.0160 -0.0160 0.0160 0.0160 ;
    SPACING 0.032 BY 0.032 ;
    RESISTANCE 5.72 ;
END VIA3C

VIARULE VIA3C_32 GENERATE
  LAYER m3 ;
    ENCLOSURE -0.002 0.009 ;
  LAYER m4 ;
    ENCLOSURE 0.024 0 ;
  LAYER v3 ;
    RECT -0.0160 -0.0160 0.0160 0.0160 ;
    SPACING 0.032 BY 0.032 ;
    RESISTANCE 5.72 ;
END VIA3C_32

VIARULE VIA5FA GENERATE
  LAYER m5 ;
    ENCLOSURE -0.002 0.012 ;
  LAYER m6 ;
    ENCLOSURE 0.022 0 ;
  LAYER v5 ;
    RECT -0.0160 -0.0540 0.0160 0.0540 ;
    SPACING 0.032 BY 0.108 ;
    RESISTANCE 5.72 ;
END VIA5FA

VIARULE VIA7F GENERATE
  LAYER m7 ;
    ENCLOSURE -0.009 0.028 ;
  LAYER m8 ;
    ENCLOSURE 0.028 0 ;
  LAYER v7 ;
    RECT -0.0370 -0.0700 0.0370 0.0700 ;
    SPACING 0.074 BY 0.14 ;
    RESISTANCE 5.72 ;
END VIA7F

VIARULE VIA3S_TIE GENERATE
  LAYER m3 ;
    ENCLOSURE 0 0.009 ;
  LAYER m4 ;
    ENCLOSURE 0.024 0 ;
  LAYER v3 ;
    RECT -0.0160 -0.0380 0.0160 0.0380 ;
    SPACING 0.032 BY 0.076 ;
    RESISTANCE 5.72 ;
END VIA3S_TIE

VIARULE VIA3O_TIE GENERATE
  LAYER m3 ;
    ENCLOSURE 0 0.009 ;
  LAYER m4 ;
    ENCLOSURE 0.024 0 ;
  LAYER v3 ;
    RECT -0.0160 -0.0420 0.0160 0.0420 ;
    SPACING 0.032 BY 0.084 ;
    RESISTANCE 5.72 ;
END VIA3O_TIE

VIARULE VIA4O_TIE GENERATE
  LAYER m4 ;
    ENCLOSURE 0.009 0 ;
  LAYER m5 ;
    ENCLOSURE 0 0.024 ;
  LAYER v4 ;
    RECT -0.0420 -0.0160 0.0420 0.0160 ;
    SPACING 0.108 BY 0.056 ;
    RESISTANCE 5.72 ;
END VIA4O_TIE

VIARULE VIA6C GENERATE
  LAYER m6 ;
    ENCLOSURE 0.016 -0.01 ;
  LAYER m7 ;
    ENCLOSURE 0 0.032 ;
  LAYER v6 ;
    RECT -0.0420 -0.0300 0.0420 0.0300 ;
    SPACING 0.084 BY 0.06 ;
    RESISTANCE 5.72 ;
END VIA6C

VIARULE VIA6CX GENERATE
  LAYER m6 ;
    ENCLOSURE 0.016 0 ;
  LAYER m7 ;
    ENCLOSURE 0 0.032 ;
  LAYER v6 ;
    RECT -0.0420 -0.0360 0.0420 0.0360 ;
    SPACING 0.084 BY 0.072 ;
    RESISTANCE 5.72 ;
END VIA6CX

VIARULE VIA0AY GENERATE
  LAYER m0 ;
    ENCLOSURE 0.015 0 ;
  LAYER m1 ;
    ENCLOSURE 0 0.014 ;
  LAYER v0 ;
    RECT -0.0280 -0.0140 0.0280 0.0140 ;
    SPACING 0.056 BY 0.028 ;
    RESISTANCE 5.72 ;
END VIA0AY

VIARULE VIA7B GENERATE
  LAYER m7 ;
    ENCLOSURE -0.009 0.028 ;
  LAYER m8 ;
    ENCLOSURE 0.028 0 ;
  LAYER v7 ;
    RECT -0.0370 -0.1050 0.0370 0.1050 ;
    SPACING 0.074 BY 0.21 ;
    RESISTANCE 5.72 ;
END VIA7B

VIARULE VIA7C_A GENERATE
  LAYER m7 ;
    ENCLOSURE -0.009 0.028 ;
  LAYER m8 ;
    ENCLOSURE 0.028 0 ;
  LAYER v7 ;
    RECT -0.0630 -0.0630 0.0630 0.0630 ;
    SPACING 0.252 BY 0.252 ;
    RESISTANCE 5.72 ;
END VIA7C_A

VIARULE VIA0AX_XN GENERATE
  LAYER m0 ;
    ENCLOSURE 0.014 0 ;
  LAYER m1 ;
    ENCLOSURE 0.007 0.014 ;
  LAYER v0 ;
    RECT -0.0210 -0.0140 0.0210 0.0140 ;
    SPACING 0.042 BY 0.028 ;
    RESISTANCE 5.72 ;
END VIA0AX_XN

VIARULE VIA0CX_XN GENERATE
  LAYER m0 ;
    ENCLOSURE 0.014 0 ;
  LAYER m1 ;
    ENCLOSURE 0.007 0.014 ;
  LAYER v0 ;
    RECT -0.0210 -0.0200 0.0210 0.0200 ;
    SPACING 0.042 BY 0.04 ;
    RESISTANCE 5.72 ;
END VIA0CX_XN

VIARULE VIA0A_XN GENERATE
  LAYER m0 ;
    ENCLOSURE 0.014 0 ;
  LAYER m1 ;
    ENCLOSURE 0.007 0.014 ;
  LAYER v0 ;
    RECT -0.0210 -0.0210 0.0210 0.0210 ;
    SPACING 0.042 BY 0.042 ;
    RESISTANCE 5.72 ;
END VIA0A_XN

VIARULE VIA1A_XN GENERATE
  LAYER m1 ;
    ENCLOSURE 0.01 0.007 ;
  LAYER m2 ;
    ENCLOSURE 0.024 0 ;
  LAYER v1 ;
    RECT -0.0180 -0.0140 0.0180 0.0140 ;
    SPACING 0.036 BY 0.028 ;
    RESISTANCE 5.72 ;
END VIA1A_XN

VIARULE VIA1F_XN GENERATE
  LAYER m1 ;
    ENCLOSURE 0.01 0.007 ;
  LAYER m2 ;
    ENCLOSURE 0.024 0 ;
  LAYER v1 ;
    RECT -0.0180 -0.0200 0.0180 0.0200 ;
    SPACING 0.036 BY 0.04 ;
    RESISTANCE 5.72 ;
END VIA1F_XN

VIARULE VIA3RX_TIE_28 GENERATE
  LAYER m3 ;
    ENCLOSURE -0.005 0.009 ;
  LAYER m4 ;
    ENCLOSURE 0.024 0 ;
  LAYER v3 ;
    RECT -0.0190 -0.0300 0.0190 0.0300 ;
    SPACING 0.062 BY 0.084 ;
    RESISTANCE 5.72 ;
END VIA3RX_TIE_28

VIARULE VIA3RX_TIE_32 GENERATE
  LAYER m3 ;
    ENCLOSURE -0.003 0.009 ;
  LAYER m4 ;
    ENCLOSURE 0.024 0 ;
  LAYER v3 ;
    RECT -0.0190 -0.0300 0.0190 0.0300 ;
    SPACING 0.062 BY 0.084 ;
    RESISTANCE 5.72 ;
END VIA3RX_TIE_32

VIARULE VIA0BW GENERATE
  LAYER m0 ;
    ENCLOSURE 0.014 0 ;
  LAYER m1 ;
    ENCLOSURE 0 0.014 ;
  LAYER v0 ;
    RECT -0.0280 -0.0230 0.0280 0.0230 ;
    SPACING 0.056 BY 0.046 ;
    RESISTANCE 5.72 ;
END VIA0BW

VIARULE VIA1V_XN GENERATE
  LAYER m1 ;
    ENCLOSURE 0.01 0.007 ;
  LAYER m2 ;
    ENCLOSURE 0.024 0 ;
  LAYER v1 ;
    RECT -0.0180 -0.0370 0.0180 0.0370 ;
    SPACING 0.036 BY 0.074 ;
    RESISTANCE 5.72 ;
END VIA1V_XN

VIARULE VIA2A_32 GENERATE
  LAYER m2 ;
    ENCLOSURE 0.009 0 ;
  LAYER m3 ;
    ENCLOSURE 0 0.024 ;
  LAYER v2 ;
    RECT -0.0140 -0.0160 0.0140 0.0160 ;
    SPACING 0.028 BY 0.032 ;
    RESISTANCE 5.72 ;
END VIA2A_32

VIARULE VIA1C GENERATE
  LAYER m1 ;
    ENCLOSURE 0.003 0.007 ;
  LAYER m2 ;
    ENCLOSURE 0.024 0 ;
  LAYER v1 ;
    RECT -0.0180 -0.0160 0.0180 0.0160 ;
    SPACING 0.036 BY 0.032 ;
    RESISTANCE 5.72 ;
END VIA1C

VIARULE VIA1E GENERATE
  LAYER m1 ;
    ENCLOSURE 0.003 0.007 ;
  LAYER m2 ;
    ENCLOSURE 0.024 0 ;
  LAYER v1 ;
    RECT -0.0180 -0.0190 0.0180 0.0190 ;
    SPACING 0.036 BY 0.038 ;
    RESISTANCE 5.72 ;
END VIA1E

VIARULE VIA0FX GENERATE
  LAYER m0 ;
    ENCLOSURE 0.014 0.002 ;
  LAYER m1 ;
    ENCLOSURE 0 0.017 ;
  LAYER v0 ;
    RECT -0.0210 -0.0390 0.0210 0.0390 ;
    SPACING 0.042 BY 0.078 ;
    RESISTANCE 5.72 ;
END VIA0FX

VIARULE VIA5MP_56 GENERATE
  LAYER m5 ;
    ENCLOSURE 0.006 0.012 ;
  LAYER m6 ;
    ENCLOSURE 0.022 0 ;
  LAYER v5 ;
    RECT -0.0220 -0.0540 0.0220 0.0540 ;
    SPACING 0.044 BY 0.108 ;
    RESISTANCE 5.72 ;
END VIA5MP_56

VIARULE VIA5MP_60 GENERATE
  LAYER m5 ;
    ENCLOSURE 0.008 0.012 ;
  LAYER m6 ;
    ENCLOSURE 0.022 0 ;
  LAYER v5 ;
    RECT -0.0220 -0.0540 0.0220 0.0540 ;
    SPACING 0.044 BY 0.108 ;
    RESISTANCE 5.72 ;
END VIA5MP_60

VIARULE VIA4O_30 GENERATE
  LAYER m4 ;
    ENCLOSURE 0.009 -0.001 ;
  LAYER m5 ;
    ENCLOSURE 0 0.024 ;
  LAYER v4 ;
    RECT -0.0420 -0.0160 0.0420 0.0160 ;
    SPACING 0.108 BY 0.056 ;
    RESISTANCE 5.72 ;
END VIA4O_30

VIARULE VIA6F_44 GENERATE
  LAYER m6 ;
    ENCLOSURE 0.016 -0.008 ;
  LAYER m7 ;
    ENCLOSURE 0 0.032 ;
  LAYER v6 ;
    RECT -0.0840 -0.0300 0.0840 0.0300 ;
    SPACING 0.168 BY 0.06 ;
    RESISTANCE 5.72 ;
END VIA6F_44

VIARULE VIA2G GENERATE
  LAYER m2 ;
    ENCLOSURE 0.009 -0.002 ;
  LAYER m3 ;
    ENCLOSURE 0 0.024 ;
  LAYER v2 ;
    RECT -0.0230 -0.0160 0.0230 0.0160 ;
    SPACING 0.046 BY 0.032 ;
    RESISTANCE 5.72 ;
END VIA2G

VIARULE VIA2G_32 GENERATE
  LAYER m2 ;
    ENCLOSURE 0.009 0 ;
  LAYER m3 ;
    ENCLOSURE 0 0.024 ;
  LAYER v2 ;
    RECT -0.0230 -0.0160 0.0230 0.0160 ;
    SPACING 0.046 BY 0.032 ;
    RESISTANCE 5.72 ;
END VIA2G_32

VIARULE VIA2G_38 GENERATE
  LAYER m2 ;
    ENCLOSURE 0.009 0.003 ;
  LAYER m3 ;
    ENCLOSURE 0 0.024 ;
  LAYER v2 ;
    RECT -0.0230 -0.0160 0.0230 0.0160 ;
    SPACING 0.046 BY 0.032 ;
    RESISTANCE 5.72 ;
END VIA2G_38

VIARULE VIA2G_40 GENERATE
  LAYER m2 ;
    ENCLOSURE 0.009 0.004 ;
  LAYER m3 ;
    ENCLOSURE 0 0.024 ;
  LAYER v2 ;
    RECT -0.0230 -0.0160 0.0230 0.0160 ;
    SPACING 0.046 BY 0.032 ;
    RESISTANCE 5.72 ;
END VIA2G_40

VIARULE VIA2R_32 GENERATE
  LAYER m2 ;
    ENCLOSURE 0.009 0 ;
  LAYER m3 ;
    ENCLOSURE 0 0.024 ;
  LAYER v2 ;
    RECT -0.0300 -0.0160 0.0300 0.0160 ;
    SPACING 0.06 BY 0.032 ;
    RESISTANCE 5.72 ;
END VIA2R_32

VIARULE VIA2R_38 GENERATE
  LAYER m2 ;
    ENCLOSURE 0.009 0.003 ;
  LAYER m3 ;
    ENCLOSURE 0 0.024 ;
  LAYER v2 ;
    RECT -0.0300 -0.0160 0.0300 0.0160 ;
    SPACING 0.06 BY 0.032 ;
    RESISTANCE 5.72 ;
END VIA2R_38

VIARULE VIA2L38 GENERATE
  LAYER m2 ;
    ENCLOSURE 0.009 0.003 ;
  LAYER m3 ;
    ENCLOSURE 0 0.024 ;
  LAYER v2 ;
    RECT -0.0340 -0.0160 0.0340 0.0160 ;
    SPACING 0.068 BY 0.032 ;
    RESISTANCE 5.72 ;
END VIA2L38

VIARULE VIA2GY GENERATE
  LAYER m2 ;
    ENCLOSURE 0.009 0 ;
  LAYER m3 ;
    ENCLOSURE 0 0.024 ;
  LAYER v2 ;
    RECT -0.0230 -0.0290 0.0230 0.0290 ;
    SPACING 0.046 BY 0.058 ;
    RESISTANCE 5.72 ;
END VIA2GY

VIARULE VIA3A_60 GENERATE
  LAYER m3 ;
    ENCLOSURE 0.014 0.009 ;
  LAYER m4 ;
    ENCLOSURE 0.024 0 ;
  LAYER v3 ;
    RECT -0.0160 -0.0140 0.0160 0.0140 ;
    SPACING 0.032 BY 0.028 ;
    RESISTANCE 5.72 ;
END VIA3A_60

VIARULE VIA3B_60 GENERATE
  LAYER m3 ;
    ENCLOSURE 0.014 0.009 ;
  LAYER m4 ;
    ENCLOSURE 0.024 0 ;
  LAYER v3 ;
    RECT -0.0160 -0.0150 0.0160 0.0150 ;
    SPACING 0.056 BY 0.054 ;
    RESISTANCE 5.72 ;
END VIA3B_60

VIARULE VIA3C_40 GENERATE
  LAYER m3 ;
    ENCLOSURE 0.004 0.009 ;
  LAYER m4 ;
    ENCLOSURE 0.024 0 ;
  LAYER v3 ;
    RECT -0.0160 -0.0160 0.0160 0.0160 ;
    SPACING 0.032 BY 0.032 ;
    RESISTANCE 5.72 ;
END VIA3C_40

VIARULE VIA3C_60 GENERATE
  LAYER m3 ;
    ENCLOSURE 0.014 0.009 ;
  LAYER m4 ;
    ENCLOSURE 0.024 0 ;
  LAYER v3 ;
    RECT -0.0160 -0.0160 0.0160 0.0160 ;
    SPACING 0.032 BY 0.032 ;
    RESISTANCE 5.72 ;
END VIA3C_60

VIARULE VIA3C_30 GENERATE
  LAYER m3 ;
    ENCLOSURE -0.001 0.009 ;
  LAYER m4 ;
    ENCLOSURE 0.024 0 ;
  LAYER v3 ;
    RECT -0.0160 -0.0160 0.0160 0.0160 ;
    SPACING 0.032 BY 0.032 ;
    RESISTANCE 5.72 ;
END VIA3C_30

VIARULE VIA3F_30 GENERATE
  LAYER m3 ;
    ENCLOSURE -0.001 0.009 ;
  LAYER m4 ;
    ENCLOSURE 0.024 0 ;
  LAYER v3 ;
    RECT -0.0160 -0.0200 0.0160 0.0200 ;
    SPACING 0.032 BY 0.04 ;
    RESISTANCE 5.72 ;
END VIA3F_30

VIARULE VIA3F_32 GENERATE
  LAYER m3 ;
    ENCLOSURE 0 0.009 ;
  LAYER m4 ;
    ENCLOSURE 0.024 0 ;
  LAYER v3 ;
    RECT -0.0160 -0.0200 0.0160 0.0200 ;
    SPACING 0.032 BY 0.04 ;
    RESISTANCE 5.72 ;
END VIA3F_32

VIARULE VIA3F_40 GENERATE
  LAYER m3 ;
    ENCLOSURE 0.004 0.009 ;
  LAYER m4 ;
    ENCLOSURE 0.024 0 ;
  LAYER v3 ;
    RECT -0.0160 -0.0200 0.0160 0.0200 ;
    SPACING 0.032 BY 0.04 ;
    RESISTANCE 5.72 ;
END VIA3F_40

VIARULE VIA3F_60 GENERATE
  LAYER m3 ;
    ENCLOSURE 0.014 0.009 ;
  LAYER m4 ;
    ENCLOSURE 0.024 0 ;
  LAYER v3 ;
    RECT -0.0160 -0.0200 0.0160 0.0200 ;
    SPACING 0.032 BY 0.04 ;
    RESISTANCE 5.72 ;
END VIA3F_60

VIARULE VIA3F_68 GENERATE
  LAYER m3 ;
    ENCLOSURE 0.018 0.009 ;
  LAYER m4 ;
    ENCLOSURE 0.024 0 ;
  LAYER v3 ;
    RECT -0.0160 -0.0200 0.0160 0.0200 ;
    SPACING 0.032 BY 0.04 ;
    RESISTANCE 5.72 ;
END VIA3F_68

VIARULE VIA3G_30 GENERATE
  LAYER m3 ;
    ENCLOSURE -0.001 0.009 ;
  LAYER m4 ;
    ENCLOSURE 0.024 0 ;
  LAYER v3 ;
    RECT -0.0160 -0.0230 0.0160 0.0230 ;
    SPACING 0.056 BY 0.07 ;
    RESISTANCE 5.72 ;
END VIA3G_30

VIARULE VIA3G_32 GENERATE
  LAYER m3 ;
    ENCLOSURE 0 0.009 ;
  LAYER m4 ;
    ENCLOSURE 0.024 0 ;
  LAYER v3 ;
    RECT -0.0160 -0.0230 0.0160 0.0230 ;
    SPACING 0.056 BY 0.07 ;
    RESISTANCE 5.72 ;
END VIA3G_32

VIARULE VIA3G_40 GENERATE
  LAYER m3 ;
    ENCLOSURE 0.004 0.009 ;
  LAYER m4 ;
    ENCLOSURE 0.024 0 ;
  LAYER v3 ;
    RECT -0.0160 -0.0230 0.0160 0.0230 ;
    SPACING 0.056 BY 0.07 ;
    RESISTANCE 5.72 ;
END VIA3G_40

VIARULE VIA3G_60 GENERATE
  LAYER m3 ;
    ENCLOSURE 0.014 0.009 ;
  LAYER m4 ;
    ENCLOSURE 0.024 0 ;
  LAYER v3 ;
    RECT -0.0160 -0.0230 0.0160 0.0230 ;
    SPACING 0.056 BY 0.07 ;
    RESISTANCE 5.72 ;
END VIA3G_60

VIARULE VIA3R GENERATE
  LAYER m3 ;
    ENCLOSURE -0.002 0.009 ;
  LAYER m4 ;
    ENCLOSURE 0.024 0 ;
  LAYER v3 ;
    RECT -0.0160 -0.0300 0.0160 0.0300 ;
    SPACING 0.056 BY 0.084 ;
    RESISTANCE 5.72 ;
END VIA3R

VIARULE VIA3R_30 GENERATE
  LAYER m3 ;
    ENCLOSURE -0.001 0.009 ;
  LAYER m4 ;
    ENCLOSURE 0.024 0 ;
  LAYER v3 ;
    RECT -0.0160 -0.0300 0.0160 0.0300 ;
    SPACING 0.056 BY 0.084 ;
    RESISTANCE 5.72 ;
END VIA3R_30

VIARULE VIA3R_32 GENERATE
  LAYER m3 ;
    ENCLOSURE 0 0.009 ;
  LAYER m4 ;
    ENCLOSURE 0.024 0 ;
  LAYER v3 ;
    RECT -0.0160 -0.0300 0.0160 0.0300 ;
    SPACING 0.056 BY 0.084 ;
    RESISTANCE 5.72 ;
END VIA3R_32

VIARULE VIA3R_40 GENERATE
  LAYER m3 ;
    ENCLOSURE 0.004 0.009 ;
  LAYER m4 ;
    ENCLOSURE 0.024 0 ;
  LAYER v3 ;
    RECT -0.0160 -0.0300 0.0160 0.0300 ;
    SPACING 0.056 BY 0.084 ;
    RESISTANCE 5.72 ;
END VIA3R_40

VIARULE VIA3RY_60 GENERATE
  LAYER m3 ;
    ENCLOSURE 0.008 0.009 ;
  LAYER m4 ;
    ENCLOSURE 0.024 0 ;
  LAYER v3 ;
    RECT -0.0220 -0.0300 0.0220 0.0300 ;
    SPACING 0.044 BY 0.06 ;
    RESISTANCE 5.72 ;
END VIA3RY_60

VIARULE VIA3N_30 GENERATE
  LAYER m3 ;
    ENCLOSURE -0.001 0.009 ;
  LAYER m4 ;
    ENCLOSURE 0.024 0 ;
  LAYER v3 ;
    RECT -0.0160 -0.0330 0.0160 0.0330 ;
    SPACING 0.032 BY 0.066 ;
    RESISTANCE 5.72 ;
END VIA3N_30

VIARULE VIA3N_32 GENERATE
  LAYER m3 ;
    ENCLOSURE 0 0.009 ;
  LAYER m4 ;
    ENCLOSURE 0.024 0 ;
  LAYER v3 ;
    RECT -0.0160 -0.0330 0.0160 0.0330 ;
    SPACING 0.032 BY 0.066 ;
    RESISTANCE 5.72 ;
END VIA3N_32

VIARULE VIA3N_40 GENERATE
  LAYER m3 ;
    ENCLOSURE 0.004 0.009 ;
  LAYER m4 ;
    ENCLOSURE 0.024 0 ;
  LAYER v3 ;
    RECT -0.0160 -0.0330 0.0160 0.0330 ;
    SPACING 0.032 BY 0.066 ;
    RESISTANCE 5.72 ;
END VIA3N_40

VIARULE VIA3NX_60 GENERATE
  LAYER m3 ;
    ENCLOSURE 0.011 0.009 ;
  LAYER m4 ;
    ENCLOSURE 0.024 0 ;
  LAYER v3 ;
    RECT -0.0190 -0.0370 0.0190 0.0370 ;
    SPACING 0.038 BY 0.074 ;
    RESISTANCE 5.72 ;
END VIA3NX_60

VIARULE VIA1F_PG GENERATE
  LAYER m1 ;
    ENCLOSURE 0.003 0.017 ;
  LAYER m2 ;
    ENCLOSURE 0.024 0 ;
  LAYER v1 ;
    RECT -0.0180 -0.0200 0.0180 0.0200 ;
    SPACING 0.036 BY 0.04 ;
    RESISTANCE 5.72 ;
END VIA1F_PG

VIARULE VIA3NX_76 GENERATE
  LAYER m3 ;
    ENCLOSURE 0.019 0.009 ;
  LAYER m4 ;
    ENCLOSURE 0.024 0 ;
  LAYER v3 ;
    RECT -0.0190 -0.0370 0.0190 0.0370 ;
    SPACING 0.038 BY 0.074 ;
    RESISTANCE 5.72 ;
END VIA3NX_76

VIARULE VIA3VX_60 GENERATE
  LAYER m3 ;
    ENCLOSURE 0.01 0.009 ;
  LAYER m4 ;
    ENCLOSURE 0.024 0 ;
  LAYER v3 ;
    RECT -0.0200 -0.0330 0.0200 0.0330 ;
    SPACING 0.04 BY 0.066 ;
    RESISTANCE 5.72 ;
END VIA3VX_60

VIARULE VIA3VX_76 GENERATE
  LAYER m3 ;
    ENCLOSURE 0.018 0.009 ;
  LAYER m4 ;
    ENCLOSURE 0.024 0 ;
  LAYER v3 ;
    RECT -0.0200 -0.0330 0.0200 0.0330 ;
    SPACING 0.04 BY 0.066 ;
    RESISTANCE 5.72 ;
END VIA3VX_76

VIARULE VIA3S_30 GENERATE
  LAYER m3 ;
    ENCLOSURE -0.001 0.009 ;
  LAYER m4 ;
    ENCLOSURE 0.024 0 ;
  LAYER v3 ;
    RECT -0.0160 -0.0380 0.0160 0.0380 ;
    SPACING 0.032 BY 0.076 ;
    RESISTANCE 5.72 ;
END VIA3S_30

VIARULE VIA3S_40 GENERATE
  LAYER m3 ;
    ENCLOSURE 0.004 0.009 ;
  LAYER m4 ;
    ENCLOSURE 0.024 0 ;
  LAYER v3 ;
    RECT -0.0160 -0.0380 0.0160 0.0380 ;
    SPACING 0.032 BY 0.076 ;
    RESISTANCE 5.72 ;
END VIA3S_40

VIARULE VIA3S_60 GENERATE
  LAYER m3 ;
    ENCLOSURE 0.014 0.009 ;
  LAYER m4 ;
    ENCLOSURE 0.024 0 ;
  LAYER v3 ;
    RECT -0.0160 -0.0380 0.0160 0.0380 ;
    SPACING 0.032 BY 0.076 ;
    RESISTANCE 5.72 ;
END VIA3S_60

VIARULE VIA3S_68 GENERATE
  LAYER m3 ;
    ENCLOSURE 0.018 0.009 ;
  LAYER m4 ;
    ENCLOSURE 0.024 0 ;
  LAYER v3 ;
    RECT -0.0160 -0.0380 0.0160 0.0380 ;
    SPACING 0.032 BY 0.076 ;
    RESISTANCE 5.72 ;
END VIA3S_68

VIARULE VIA3S_76 GENERATE
  LAYER m3 ;
    ENCLOSURE 0.022 0.009 ;
  LAYER m4 ;
    ENCLOSURE 0.024 0 ;
  LAYER v3 ;
    RECT -0.0160 -0.0380 0.0160 0.0380 ;
    SPACING 0.032 BY 0.076 ;
    RESISTANCE 5.72 ;
END VIA3S_76

VIARULE VIA3O_30 GENERATE
  LAYER m3 ;
    ENCLOSURE -0.001 0.009 ;
  LAYER m4 ;
    ENCLOSURE 0.024 0 ;
  LAYER v3 ;
    RECT -0.0160 -0.0420 0.0160 0.0420 ;
    SPACING 0.032 BY 0.084 ;
    RESISTANCE 5.72 ;
END VIA3O_30

VIARULE VIA3O_40 GENERATE
  LAYER m3 ;
    ENCLOSURE 0.004 0.009 ;
  LAYER m4 ;
    ENCLOSURE 0.024 0 ;
  LAYER v3 ;
    RECT -0.0160 -0.0420 0.0160 0.0420 ;
    SPACING 0.032 BY 0.084 ;
    RESISTANCE 5.72 ;
END VIA3O_40

VIARULE VIA3O_60 GENERATE
  LAYER m3 ;
    ENCLOSURE 0.014 0.009 ;
  LAYER m4 ;
    ENCLOSURE 0.024 0 ;
  LAYER v3 ;
    RECT -0.0160 -0.0420 0.0160 0.0420 ;
    SPACING 0.032 BY 0.084 ;
    RESISTANCE 5.72 ;
END VIA3O_60

VIARULE VIA3O_68 GENERATE
  LAYER m3 ;
    ENCLOSURE 0.018 0.009 ;
  LAYER m4 ;
    ENCLOSURE 0.024 0 ;
  LAYER v3 ;
    RECT -0.0160 -0.0420 0.0160 0.0420 ;
    SPACING 0.032 BY 0.084 ;
    RESISTANCE 5.72 ;
END VIA3O_68

VIARULE VIA3O_76 GENERATE
  LAYER m3 ;
    ENCLOSURE 0.022 0.009 ;
  LAYER m4 ;
    ENCLOSURE 0.024 0 ;
  LAYER v3 ;
    RECT -0.0160 -0.0420 0.0160 0.0420 ;
    SPACING 0.032 BY 0.084 ;
    RESISTANCE 5.72 ;
END VIA3O_76

VIARULE VIA4A_32 GENERATE
  LAYER m4 ;
    ENCLOSURE 0.009 0 ;
  LAYER m5 ;
    ENCLOSURE 0 0.024 ;
  LAYER v4 ;
    RECT -0.0140 -0.0160 0.0140 0.0160 ;
    SPACING 0.028 BY 0.032 ;
    RESISTANCE 5.72 ;
END VIA4A_32

VIARULE VIA4A_36 GENERATE
  LAYER m4 ;
    ENCLOSURE 0.009 0.002 ;
  LAYER m5 ;
    ENCLOSURE 0 0.024 ;
  LAYER v4 ;
    RECT -0.0140 -0.0160 0.0140 0.0160 ;
    SPACING 0.028 BY 0.032 ;
    RESISTANCE 5.72 ;
END VIA4A_36

VIARULE VIA4A_40 GENERATE
  LAYER m4 ;
    ENCLOSURE 0.009 0.004 ;
  LAYER m5 ;
    ENCLOSURE 0 0.024 ;
  LAYER v4 ;
    RECT -0.0140 -0.0160 0.0140 0.0160 ;
    SPACING 0.028 BY 0.032 ;
    RESISTANCE 5.72 ;
END VIA4A_40

VIARULE VIA4A_46 GENERATE
  LAYER m4 ;
    ENCLOSURE 0.009 0.007 ;
  LAYER m5 ;
    ENCLOSURE 0 0.024 ;
  LAYER v4 ;
    RECT -0.0140 -0.0160 0.0140 0.0160 ;
    SPACING 0.028 BY 0.032 ;
    RESISTANCE 5.72 ;
END VIA4A_46

VIARULE VIA4A_54 GENERATE
  LAYER m4 ;
    ENCLOSURE 0.009 0.011 ;
  LAYER m5 ;
    ENCLOSURE 0 0.024 ;
  LAYER v4 ;
    RECT -0.0140 -0.0160 0.0140 0.0160 ;
    SPACING 0.028 BY 0.032 ;
    RESISTANCE 5.72 ;
END VIA4A_54

VIARULE VIA4A_56 GENERATE
  LAYER m4 ;
    ENCLOSURE 0.009 0.012 ;
  LAYER m5 ;
    ENCLOSURE 0 0.024 ;
  LAYER v4 ;
    RECT -0.0140 -0.0160 0.0140 0.0160 ;
    SPACING 0.028 BY 0.032 ;
    RESISTANCE 5.72 ;
END VIA4A_56

VIARULE VIA4A_60 GENERATE
  LAYER m4 ;
    ENCLOSURE 0.009 0.014 ;
  LAYER m5 ;
    ENCLOSURE 0 0.024 ;
  LAYER v4 ;
    RECT -0.0140 -0.0160 0.0140 0.0160 ;
    SPACING 0.028 BY 0.032 ;
    RESISTANCE 5.72 ;
END VIA4A_60

VIARULE VIA4A_66 GENERATE
  LAYER m4 ;
    ENCLOSURE 0.009 0.017 ;
  LAYER m5 ;
    ENCLOSURE 0 0.024 ;
  LAYER v4 ;
    RECT -0.0140 -0.0160 0.0140 0.0160 ;
    SPACING 0.028 BY 0.032 ;
    RESISTANCE 5.72 ;
END VIA4A_66

VIARULE VIA4B_32 GENERATE
  LAYER m4 ;
    ENCLOSURE 0.009 0 ;
  LAYER m5 ;
    ENCLOSURE 0 0.024 ;
  LAYER v4 ;
    RECT -0.0150 -0.0160 0.0150 0.0160 ;
    SPACING 0.054 BY 0.056 ;
    RESISTANCE 5.72 ;
END VIA4B_32

VIARULE VIA4B_36 GENERATE
  LAYER m4 ;
    ENCLOSURE 0.009 0.002 ;
  LAYER m5 ;
    ENCLOSURE 0 0.024 ;
  LAYER v4 ;
    RECT -0.0150 -0.0160 0.0150 0.0160 ;
    SPACING 0.054 BY 0.056 ;
    RESISTANCE 5.72 ;
END VIA4B_36

VIARULE VIA4B_40 GENERATE
  LAYER m4 ;
    ENCLOSURE 0.009 0.004 ;
  LAYER m5 ;
    ENCLOSURE 0 0.024 ;
  LAYER v4 ;
    RECT -0.0150 -0.0160 0.0150 0.0160 ;
    SPACING 0.054 BY 0.056 ;
    RESISTANCE 5.72 ;
END VIA4B_40

VIARULE VIA4B_46 GENERATE
  LAYER m4 ;
    ENCLOSURE 0.009 0.007 ;
  LAYER m5 ;
    ENCLOSURE 0 0.024 ;
  LAYER v4 ;
    RECT -0.0150 -0.0160 0.0150 0.0160 ;
    SPACING 0.054 BY 0.056 ;
    RESISTANCE 5.72 ;
END VIA4B_46

VIARULE VIA4B_54 GENERATE
  LAYER m4 ;
    ENCLOSURE 0.009 0.011 ;
  LAYER m5 ;
    ENCLOSURE 0 0.024 ;
  LAYER v4 ;
    RECT -0.0150 -0.0160 0.0150 0.0160 ;
    SPACING 0.054 BY 0.056 ;
    RESISTANCE 5.72 ;
END VIA4B_54

VIARULE VIA4B_56 GENERATE
  LAYER m4 ;
    ENCLOSURE 0.009 0.012 ;
  LAYER m5 ;
    ENCLOSURE 0 0.024 ;
  LAYER v4 ;
    RECT -0.0150 -0.0160 0.0150 0.0160 ;
    SPACING 0.054 BY 0.056 ;
    RESISTANCE 5.72 ;
END VIA4B_56

VIARULE VIA4B_60 GENERATE
  LAYER m4 ;
    ENCLOSURE 0.009 0.014 ;
  LAYER m5 ;
    ENCLOSURE 0 0.024 ;
  LAYER v4 ;
    RECT -0.0150 -0.0160 0.0150 0.0160 ;
    SPACING 0.054 BY 0.056 ;
    RESISTANCE 5.72 ;
END VIA4B_60

VIARULE VIA4B_66 GENERATE
  LAYER m4 ;
    ENCLOSURE 0.009 0.017 ;
  LAYER m5 ;
    ENCLOSURE 0 0.024 ;
  LAYER v4 ;
    RECT -0.0150 -0.0160 0.0150 0.0160 ;
    SPACING 0.054 BY 0.056 ;
    RESISTANCE 5.72 ;
END VIA4B_66

VIARULE VIA4C_30 GENERATE
  LAYER m4 ;
    ENCLOSURE 0.009 -0.001 ;
  LAYER m5 ;
    ENCLOSURE 0 0.024 ;
  LAYER v4 ;
    RECT -0.0160 -0.0160 0.0160 0.0160 ;
    SPACING 0.032 BY 0.032 ;
    RESISTANCE 5.72 ;
END VIA4C_30

VIARULE VIA4C_36 GENERATE
  LAYER m4 ;
    ENCLOSURE 0.009 0.002 ;
  LAYER m5 ;
    ENCLOSURE 0 0.024 ;
  LAYER v4 ;
    RECT -0.0160 -0.0160 0.0160 0.0160 ;
    SPACING 0.032 BY 0.032 ;
    RESISTANCE 5.72 ;
END VIA4C_36

VIARULE VIA4C_40 GENERATE
  LAYER m4 ;
    ENCLOSURE 0.009 0.004 ;
  LAYER m5 ;
    ENCLOSURE 0 0.024 ;
  LAYER v4 ;
    RECT -0.0160 -0.0160 0.0160 0.0160 ;
    SPACING 0.032 BY 0.032 ;
    RESISTANCE 5.72 ;
END VIA4C_40

VIARULE VIA4C_46 GENERATE
  LAYER m4 ;
    ENCLOSURE 0.009 0.007 ;
  LAYER m5 ;
    ENCLOSURE 0 0.024 ;
  LAYER v4 ;
    RECT -0.0160 -0.0160 0.0160 0.0160 ;
    SPACING 0.032 BY 0.032 ;
    RESISTANCE 5.72 ;
END VIA4C_46

VIARULE VIA4C_54 GENERATE
  LAYER m4 ;
    ENCLOSURE 0.009 0.011 ;
  LAYER m5 ;
    ENCLOSURE 0 0.024 ;
  LAYER v4 ;
    RECT -0.0160 -0.0160 0.0160 0.0160 ;
    SPACING 0.032 BY 0.032 ;
    RESISTANCE 5.72 ;
END VIA4C_54

VIARULE VIA4C_56 GENERATE
  LAYER m4 ;
    ENCLOSURE 0.009 0.012 ;
  LAYER m5 ;
    ENCLOSURE 0 0.024 ;
  LAYER v4 ;
    RECT -0.0160 -0.0160 0.0160 0.0160 ;
    SPACING 0.032 BY 0.032 ;
    RESISTANCE 5.72 ;
END VIA4C_56

VIARULE VIA4C_60 GENERATE
  LAYER m4 ;
    ENCLOSURE 0.009 0.014 ;
  LAYER m5 ;
    ENCLOSURE 0 0.024 ;
  LAYER v4 ;
    RECT -0.0160 -0.0160 0.0160 0.0160 ;
    SPACING 0.032 BY 0.032 ;
    RESISTANCE 5.72 ;
END VIA4C_60

VIARULE VIA4C_66 GENERATE
  LAYER m4 ;
    ENCLOSURE 0.009 0.017 ;
  LAYER m5 ;
    ENCLOSURE 0 0.024 ;
  LAYER v4 ;
    RECT -0.0160 -0.0160 0.0160 0.0160 ;
    SPACING 0.032 BY 0.032 ;
    RESISTANCE 5.72 ;
END VIA4C_66

VIARULE VIA0FX_78 GENERATE
  LAYER m0 ;
    ENCLOSURE 0.014 0 ;
  LAYER m1 ;
    ENCLOSURE 0 0.017 ;
  LAYER v0 ;
    RECT -0.0210 -0.0390 0.0210 0.0390 ;
    SPACING 0.042 BY 0.078 ;
    RESISTANCE 5.72 ;
END VIA0FX_78

VIARULE VIA0AX_36 GENERATE
  LAYER m0 ;
    ENCLOSURE 0.014 0.004 ;
  LAYER m1 ;
    ENCLOSURE 0 0.014 ;
  LAYER v0 ;
    RECT -0.0210 -0.0140 0.0210 0.0140 ;
    SPACING 0.042 BY 0.028 ;
    RESISTANCE 5.72 ;
END VIA0AX_36

VIARULE VIA0FX_80 GENERATE
  LAYER m0 ;
    ENCLOSURE 0.014 0.001 ;
  LAYER m1 ;
    ENCLOSURE 0 0.017 ;
  LAYER v0 ;
    RECT -0.0210 -0.0390 0.0210 0.0390 ;
    SPACING 0.042 BY 0.078 ;
    RESISTANCE 5.72 ;
END VIA0FX_80

VIARULE VIA0BX GENERATE
  LAYER m0 ;
    ENCLOSURE 0.014 0 ;
  LAYER m1 ;
    ENCLOSURE 0 0.014 ;
  LAYER v0 ;
    RECT -0.0210 -0.0160 0.0210 0.0160 ;
    SPACING 0.042 BY 0.032 ;
    RESISTANCE 5.72 ;
END VIA0BX

VIARULE VIA2A_m3_26 GENERATE
  LAYER m2 ;
    ENCLOSURE 0.009 -0.002 ;
  LAYER m3 ;
    ENCLOSURE 0 0.026 ;
  LAYER v2 ;
    RECT -0.0140 -0.0160 0.0140 0.0160 ;
    SPACING 0.028 BY 0.032 ;
    RESISTANCE 5.72 ;
END VIA2A_m3_26

VIARULE VIA0BX_36 GENERATE
  LAYER m0 ;
    ENCLOSURE 0.014 0.002 ;
  LAYER m1 ;
    ENCLOSURE 0 0.014 ;
  LAYER v0 ;
    RECT -0.0210 -0.0160 0.0210 0.0160 ;
    SPACING 0.042 BY 0.032 ;
    RESISTANCE 5.72 ;
END VIA0BX_36

VIARULE VIA2C_m3_26 GENERATE
  LAYER m2 ;
    ENCLOSURE 0.009 -0.002 ;
  LAYER m3 ;
    ENCLOSURE 0 0.026 ;
  LAYER v2 ;
    RECT -0.0160 -0.0160 0.0160 0.0160 ;
    SPACING 0.032 BY 0.032 ;
    RESISTANCE 5.72 ;
END VIA2C_m3_26

VIARULE VIA1HJ GENERATE
  LAYER m1 ;
    ENCLOSURE 0.003 0.017 ;
  LAYER m2 ;
    ENCLOSURE 0.024 0.006 ;
  LAYER v1 ;
    RECT -0.0180 -0.0320 0.0180 0.0320 ;
    SPACING 0.036 BY 0.064 ;
    RESISTANCE 5.72 ;
END VIA1HJ

VIARULE VIA5MP_66 GENERATE
  LAYER m5 ;
    ENCLOSURE 0.011 0.012 ;
  LAYER m6 ;
    ENCLOSURE 0.022 0 ;
  LAYER v5 ;
    RECT -0.0220 -0.0540 0.0220 0.0540 ;
    SPACING 0.044 BY 0.108 ;
    RESISTANCE 5.72 ;
END VIA5MP_66

VIARULE VIA5MP_68 GENERATE
  LAYER m5 ;
    ENCLOSURE 0.012 0.012 ;
  LAYER m6 ;
    ENCLOSURE 0.022 0 ;
  LAYER v5 ;
    RECT -0.0220 -0.0540 0.0220 0.0540 ;
    SPACING 0.044 BY 0.108 ;
    RESISTANCE 5.72 ;
END VIA5MP_68

VIARULE VIA5MP_74 GENERATE
  LAYER m5 ;
    ENCLOSURE 0.015 0.012 ;
  LAYER m6 ;
    ENCLOSURE 0.022 0 ;
  LAYER v5 ;
    RECT -0.0220 -0.0540 0.0220 0.0540 ;
    SPACING 0.044 BY 0.108 ;
    RESISTANCE 5.72 ;
END VIA5MP_74

VIARULE VIA5MP_76 GENERATE
  LAYER m5 ;
    ENCLOSURE 0.016 0.012 ;
  LAYER m6 ;
    ENCLOSURE 0.022 0 ;
  LAYER v5 ;
    RECT -0.0220 -0.0540 0.0220 0.0540 ;
    SPACING 0.044 BY 0.108 ;
    RESISTANCE 5.72 ;
END VIA5MP_76

VIARULE VIA5MP_84 GENERATE
  LAYER m5 ;
    ENCLOSURE 0.02 0.012 ;
  LAYER m6 ;
    ENCLOSURE 0.022 0 ;
  LAYER v5 ;
    RECT -0.0220 -0.0540 0.0220 0.0540 ;
    SPACING 0.044 BY 0.108 ;
    RESISTANCE 5.72 ;
END VIA5MP_84

VIARULE VIA5FA_32 GENERATE
  LAYER m5 ;
    ENCLOSURE 0 0.012 ;
  LAYER m6 ;
    ENCLOSURE 0.022 0 ;
  LAYER v5 ;
    RECT -0.0160 -0.0540 0.0160 0.0540 ;
    SPACING 0.032 BY 0.108 ;
    RESISTANCE 5.72 ;
END VIA5FA_32

VIARULE VIA4A_m5_26 GENERATE
  LAYER m4 ;
    ENCLOSURE 0.009 0 ;
  LAYER m5 ;
    ENCLOSURE 0 0.026 ;
  LAYER v4 ;
    RECT -0.0140 -0.0160 0.0140 0.0160 ;
    SPACING 0.028 BY 0.032 ;
    RESISTANCE 5.72 ;
END VIA4A_m5_26

VIARULE VIA4C_m5_26 GENERATE
  LAYER m4 ;
    ENCLOSURE 0.009 0 ;
  LAYER m5 ;
    ENCLOSURE 0 0.026 ;
  LAYER v4 ;
    RECT -0.0160 -0.0160 0.0160 0.0160 ;
    SPACING 0.032 BY 0.032 ;
    RESISTANCE 5.72 ;
END VIA4C_m5_26

VIARULE VIA4RX_40_60 GENERATE
  LAYER m4 ;
    ENCLOSURE 0.009 0.001 ;
  LAYER m5 ;
    ENCLOSURE 0 0.024 ;
  LAYER v4 ;
    RECT -0.0300 -0.0190 0.0300 0.0190 ;
    SPACING 0.084 BY 0.062 ;
    RESISTANCE 5.72 ;
END VIA4RX_40_60

VIARULE VIA4RY_60_60 GENERATE
  LAYER m4 ;
    ENCLOSURE 0.009 0.008 ;
  LAYER m5 ;
    ENCLOSURE 0 0.024 ;
  LAYER v4 ;
    RECT -0.0300 -0.0220 0.0300 0.0220 ;
    SPACING 0.084 BY 0.068 ;
    RESISTANCE 5.72 ;
END VIA4RY_60_60

VIARULE VIA5B_60_44 GENERATE
  LAYER m5 ;
    ENCLOSURE 0.014 0.012 ;
  LAYER m6 ;
    ENCLOSURE 0.022 0 ;
  LAYER v5 ;
    RECT -0.0160 -0.0220 0.0160 0.0220 ;
    SPACING 0.032 BY 0.044 ;
    RESISTANCE 5.72 ;
END VIA5B_60_44

VIARULE VIA4R_60_60 GENERATE
  LAYER m4 ;
    ENCLOSURE 0.009 0.004 ;
  LAYER m5 ;
    ENCLOSURE 0 0.024 ;
  LAYER v4 ;
    RECT -0.0300 -0.0160 0.0300 0.0160 ;
    SPACING 0.084 BY 0.056 ;
    RESISTANCE 5.72 ;
END VIA4R_60_60

VIARULE VIA5FA_40 GENERATE
  LAYER m5 ;
    ENCLOSURE 0.004 0.012 ;
  LAYER m6 ;
    ENCLOSURE 0.022 0 ;
  LAYER v5 ;
    RECT -0.0160 -0.0540 0.0160 0.0540 ;
    SPACING 0.032 BY 0.108 ;
    RESISTANCE 5.72 ;
END VIA5FA_40

VIARULE VIA5C GENERATE
  LAYER m5 ;
    ENCLOSURE -0.002 0.012 ;
  LAYER m6 ;
    ENCLOSURE 0.022 0 ;
  LAYER v5 ;
    RECT -0.0160 -0.0400 0.0160 0.0400 ;
    SPACING 0.032 BY 0.08 ;
    RESISTANCE 5.72 ;
END VIA5C

VIARULE VIA5C_32 GENERATE
  LAYER m5 ;
    ENCLOSURE 0 0.012 ;
  LAYER m6 ;
    ENCLOSURE 0.022 0 ;
  LAYER v5 ;
    RECT -0.0160 -0.0400 0.0160 0.0400 ;
    SPACING 0.032 BY 0.08 ;
    RESISTANCE 5.72 ;
END VIA5C_32

VIARULE VIA5C_36 GENERATE
  LAYER m5 ;
    ENCLOSURE 0.002 0.012 ;
  LAYER m6 ;
    ENCLOSURE 0.022 0 ;
  LAYER v5 ;
    RECT -0.0160 -0.0400 0.0160 0.0400 ;
    SPACING 0.032 BY 0.08 ;
    RESISTANCE 5.72 ;
END VIA5C_36

VIARULE VIA5CP GENERATE
  LAYER m5 ;
    ENCLOSURE -0.002 0.012 ;
  LAYER m6 ;
    ENCLOSURE 0.022 0 ;
  LAYER v5 ;
    RECT -0.0220 -0.0400 0.0220 0.0400 ;
    SPACING 0.044 BY 0.08 ;
    RESISTANCE 5.72 ;
END VIA5CP

VIARULE VIA5CP_46 GENERATE
  LAYER m5 ;
    ENCLOSURE 0.001 0.012 ;
  LAYER m6 ;
    ENCLOSURE 0.022 0 ;
  LAYER v5 ;
    RECT -0.0220 -0.0400 0.0220 0.0400 ;
    SPACING 0.044 BY 0.08 ;
    RESISTANCE 5.72 ;
END VIA5CP_46

VIARULE VIA5CP_56 GENERATE
  LAYER m5 ;
    ENCLOSURE 0.006 0.012 ;
  LAYER m6 ;
    ENCLOSURE 0.022 0 ;
  LAYER v5 ;
    RECT -0.0220 -0.0400 0.0220 0.0400 ;
    SPACING 0.044 BY 0.08 ;
    RESISTANCE 5.72 ;
END VIA5CP_56

VIARULE VIA5CP_60 GENERATE
  LAYER m5 ;
    ENCLOSURE 0.008 0.012 ;
  LAYER m6 ;
    ENCLOSURE 0.022 0 ;
  LAYER v5 ;
    RECT -0.0220 -0.0400 0.0220 0.0400 ;
    SPACING 0.044 BY 0.08 ;
    RESISTANCE 5.72 ;
END VIA5CP_60

VIARULE VIA5CP_66 GENERATE
  LAYER m5 ;
    ENCLOSURE 0.011 0.012 ;
  LAYER m6 ;
    ENCLOSURE 0.022 0 ;
  LAYER v5 ;
    RECT -0.0220 -0.0400 0.0220 0.0400 ;
    SPACING 0.044 BY 0.08 ;
    RESISTANCE 5.72 ;
END VIA5CP_66

VIARULE VIA5CP_74 GENERATE
  LAYER m5 ;
    ENCLOSURE 0.015 0.012 ;
  LAYER m6 ;
    ENCLOSURE 0.022 0 ;
  LAYER v5 ;
    RECT -0.0220 -0.0400 0.0220 0.0400 ;
    SPACING 0.044 BY 0.08 ;
    RESISTANCE 5.72 ;
END VIA5CP_74

VIARULE VIA5CP_76 GENERATE
  LAYER m5 ;
    ENCLOSURE 0.012 0.012 ;
  LAYER m6 ;
    ENCLOSURE 0.022 0 ;
  LAYER v5 ;
    RECT -0.0220 -0.0400 0.0220 0.0400 ;
    SPACING 0.044 BY 0.08 ;
    RESISTANCE 5.72 ;
END VIA5CP_76

VIARULE VIA5CP_84 GENERATE
  LAYER m5 ;
    ENCLOSURE 0.02 0.012 ;
  LAYER m6 ;
    ENCLOSURE 0.022 0 ;
  LAYER v5 ;
    RECT -0.0220 -0.0400 0.0220 0.0400 ;
    SPACING 0.044 BY 0.08 ;
    RESISTANCE 5.72 ;
END VIA5CP_84

VIARULE VIA6C_44 GENERATE
  LAYER m6 ;
    ENCLOSURE 0.016 -0.008 ;
  LAYER m7 ;
    ENCLOSURE 0 0.032 ;
  LAYER v6 ;
    RECT -0.0420 -0.0300 0.0420 0.0300 ;
    SPACING 0.084 BY 0.06 ;
    RESISTANCE 5.72 ;
END VIA6C_44

VIARULE VIA6C_90 GENERATE
  LAYER m6 ;
    ENCLOSURE 0.016 0.015 ;
  LAYER m7 ;
    ENCLOSURE 0 0.032 ;
  LAYER v6 ;
    RECT -0.0420 -0.0300 0.0420 0.0300 ;
    SPACING 0.084 BY 0.06 ;
    RESISTANCE 5.72 ;
END VIA6C_90

VIARULE VIA6C_108 GENERATE
  LAYER m6 ;
    ENCLOSURE 0.016 0.024 ;
  LAYER m7 ;
    ENCLOSURE 0 0.032 ;
  LAYER v6 ;
    RECT -0.0420 -0.0300 0.0420 0.0300 ;
    SPACING 0.084 BY 0.06 ;
    RESISTANCE 5.72 ;
END VIA6C_108

VIARULE VIA6A_90 GENERATE
  LAYER m6 ;
    ENCLOSURE 0.016 0.015 ;
  LAYER m7 ;
    ENCLOSURE 0 0.032 ;
  LAYER v6 ;
    RECT -0.0280 -0.0300 0.0280 0.0300 ;
    SPACING 0.056 BY 0.06 ;
    RESISTANCE 5.72 ;
END VIA6A_90

VIARULE VIA0AX_DA GENERATE
  LAYER m0 ;
    ENCLOSURE 0.019 0 ;
  LAYER m1 ;
    ENCLOSURE 0 0.014 ;
  LAYER v0 ;
    RECT -0.0210 -0.0140 0.0210 0.0140 ;
    SPACING 0.042 BY 0.028 ;
    RESISTANCE 5.72 ;
END VIA0AX_DA

VIARULE VIA0AX_DB GENERATE
  LAYER m0 ;
    ENCLOSURE 0.014 0 ;
  LAYER m1 ;
    ENCLOSURE 0 0.019 ;
  LAYER v0 ;
    RECT -0.0210 -0.0140 0.0210 0.0140 ;
    SPACING 0.042 BY 0.028 ;
    RESISTANCE 5.72 ;
END VIA0AX_DB

VIARULE VIA0AX_DC GENERATE
  LAYER m0 ;
    ENCLOSURE 0.019 0 ;
  LAYER m1 ;
    ENCLOSURE 0 0.019 ;
  LAYER v0 ;
    RECT -0.0210 -0.0140 0.0210 0.0140 ;
    SPACING 0.042 BY 0.028 ;
    RESISTANCE 5.72 ;
END VIA0AX_DC

VIARULE VIA1A_DA GENERATE
  LAYER m1 ;
    ENCLOSURE 0.003 0.012 ;
  LAYER m2 ;
    ENCLOSURE 0.024 0 ;
  LAYER v1 ;
    RECT -0.0180 -0.0140 0.0180 0.0140 ;
    SPACING 0.036 BY 0.028 ;
    RESISTANCE 5.72 ;
END VIA1A_DA

VIARULE VIA1A_DB GENERATE
  LAYER m1 ;
    ENCLOSURE 0.003 0.007 ;
  LAYER m2 ;
    ENCLOSURE 0.029 0 ;
  LAYER v1 ;
    RECT -0.0180 -0.0140 0.0180 0.0140 ;
    SPACING 0.036 BY 0.028 ;
    RESISTANCE 5.72 ;
END VIA1A_DB

VIARULE VIA1A_DC GENERATE
  LAYER m1 ;
    ENCLOSURE 0.003 0.012 ;
  LAYER m2 ;
    ENCLOSURE 0.029 0 ;
  LAYER v1 ;
    RECT -0.0180 -0.0140 0.0180 0.0140 ;
    SPACING 0.036 BY 0.028 ;
    RESISTANCE 5.72 ;
END VIA1A_DC

VIARULE VIA2A_DA GENERATE
  LAYER m2 ;
    ENCLOSURE 0.014 -0.002 ;
  LAYER m3 ;
    ENCLOSURE 0 0.024 ;
  LAYER v2 ;
    RECT -0.0140 -0.0160 0.0140 0.0160 ;
    SPACING 0.028 BY 0.032 ;
    RESISTANCE 5.72 ;
END VIA2A_DA

VIARULE VIA2A_DB GENERATE
  LAYER m2 ;
    ENCLOSURE 0.009 -0.002 ;
  LAYER m3 ;
    ENCLOSURE 0 0.029 ;
  LAYER v2 ;
    RECT -0.0140 -0.0160 0.0140 0.0160 ;
    SPACING 0.028 BY 0.032 ;
    RESISTANCE 5.72 ;
END VIA2A_DB

VIARULE VIA2A_DC GENERATE
  LAYER m2 ;
    ENCLOSURE 0.014 -0.002 ;
  LAYER m3 ;
    ENCLOSURE 0 0.029 ;
  LAYER v2 ;
    RECT -0.0140 -0.0160 0.0140 0.0160 ;
    SPACING 0.028 BY 0.032 ;
    RESISTANCE 5.72 ;
END VIA2A_DC

VIARULE VIA2C_DA GENERATE
  LAYER m2 ;
    ENCLOSURE 0.014 -0.002 ;
  LAYER m3 ;
    ENCLOSURE 0 0.024 ;
  LAYER v2 ;
    RECT -0.0160 -0.0160 0.0160 0.0160 ;
    SPACING 0.032 BY 0.032 ;
    RESISTANCE 5.72 ;
END VIA2C_DA

VIARULE VIA2C_DB GENERATE
  LAYER m2 ;
    ENCLOSURE 0.009 -0.002 ;
  LAYER m3 ;
    ENCLOSURE 0 0.029 ;
  LAYER v2 ;
    RECT -0.0160 -0.0160 0.0160 0.0160 ;
    SPACING 0.032 BY 0.032 ;
    RESISTANCE 5.72 ;
END VIA2C_DB

VIARULE VIA2C_DC GENERATE
  LAYER m2 ;
    ENCLOSURE 0.014 -0.002 ;
  LAYER m3 ;
    ENCLOSURE 0 0.029 ;
  LAYER v2 ;
    RECT -0.0160 -0.0160 0.0160 0.0160 ;
    SPACING 0.032 BY 0.032 ;
    RESISTANCE 5.72 ;
END VIA2C_DC

VIARULE VIA3C_DA GENERATE
  LAYER m3 ;
    ENCLOSURE 0 0.014 ;
  LAYER m4 ;
    ENCLOSURE 0.024 0 ;
  LAYER v3 ;
    RECT -0.0160 -0.0160 0.0160 0.0160 ;
    SPACING 0.032 BY 0.032 ;
    RESISTANCE 5.72 ;
END VIA3C_DA

VIARULE VIA3C_DB GENERATE
  LAYER m3 ;
    ENCLOSURE 0 0.009 ;
  LAYER m4 ;
    ENCLOSURE 0.029 0 ;
  LAYER v3 ;
    RECT -0.0160 -0.0160 0.0160 0.0160 ;
    SPACING 0.032 BY 0.032 ;
    RESISTANCE 5.72 ;
END VIA3C_DB

VIARULE VIA3C_DC GENERATE
  LAYER m3 ;
    ENCLOSURE 0 0.014 ;
  LAYER m4 ;
    ENCLOSURE 0.029 0 ;
  LAYER v3 ;
    RECT -0.0160 -0.0160 0.0160 0.0160 ;
    SPACING 0.032 BY 0.032 ;
    RESISTANCE 5.72 ;
END VIA3C_DC

VIARULE VIA3C_32_DA GENERATE
  LAYER m3 ;
    ENCLOSURE -0.002 0.012 ;
  LAYER m4 ;
    ENCLOSURE 0.024 0 ;
  LAYER v3 ;
    RECT -0.0160 -0.0160 0.0160 0.0160 ;
    SPACING 0.032 BY 0.032 ;
    RESISTANCE 5.72 ;
END VIA3C_32_DA

VIARULE VIA3C_32_DB GENERATE
  LAYER m3 ;
    ENCLOSURE -0.002 0.009 ;
  LAYER m4 ;
    ENCLOSURE 0.029 0 ;
  LAYER v3 ;
    RECT -0.0160 -0.0160 0.0160 0.0160 ;
    SPACING 0.032 BY 0.032 ;
    RESISTANCE 5.72 ;
END VIA3C_32_DB

VIARULE VIA3C_32_DC GENERATE
  LAYER m3 ;
    ENCLOSURE -0.002 0.012 ;
  LAYER m4 ;
    ENCLOSURE 0.029 0 ;
  LAYER v3 ;
    RECT -0.0160 -0.0160 0.0160 0.0160 ;
    SPACING 0.032 BY 0.032 ;
    RESISTANCE 5.72 ;
END VIA3C_32_DC

VIARULE VIA4A_32_DA GENERATE
  LAYER m4 ;
    ENCLOSURE 0.014 0 ;
  LAYER m5 ;
    ENCLOSURE 0 0.024 ;
  LAYER v4 ;
    RECT -0.0140 -0.0160 0.0140 0.0160 ;
    SPACING 0.028 BY 0.032 ;
    RESISTANCE 5.72 ;
END VIA4A_32_DA

VIARULE VIA4A_32_DB GENERATE
  LAYER m4 ;
    ENCLOSURE 0.009 0 ;
  LAYER m5 ;
    ENCLOSURE 0 0.029 ;
  LAYER v4 ;
    RECT -0.0140 -0.0160 0.0140 0.0160 ;
    SPACING 0.028 BY 0.032 ;
    RESISTANCE 5.72 ;
END VIA4A_32_DB

VIARULE VIA4A_32_DC GENERATE
  LAYER m4 ;
    ENCLOSURE 0.014 0 ;
  LAYER m5 ;
    ENCLOSURE 0 0.029 ;
  LAYER v4 ;
    RECT -0.0140 -0.0160 0.0140 0.0160 ;
    SPACING 0.028 BY 0.032 ;
    RESISTANCE 5.72 ;
END VIA4A_32_DC

VIARULE VIA4C_DA GENERATE
  LAYER m4 ;
    ENCLOSURE 0.012 0 ;
  LAYER m5 ;
    ENCLOSURE 0 0.024 ;
  LAYER v4 ;
    RECT -0.0160 -0.0160 0.0160 0.0160 ;
    SPACING 0.032 BY 0.032 ;
    RESISTANCE 5.72 ;
END VIA4C_DA

VIARULE VIA4C_DB GENERATE
  LAYER m4 ;
    ENCLOSURE 0.009 0 ;
  LAYER m5 ;
    ENCLOSURE 0 0.029 ;
  LAYER v4 ;
    RECT -0.0160 -0.0160 0.0160 0.0160 ;
    SPACING 0.032 BY 0.032 ;
    RESISTANCE 5.72 ;
END VIA4C_DB

VIARULE VIA4C_DC GENERATE
  LAYER m4 ;
    ENCLOSURE 0.012 0 ;
  LAYER m5 ;
    ENCLOSURE 0 0.029 ;
  LAYER v4 ;
    RECT -0.0160 -0.0160 0.0160 0.0160 ;
    SPACING 0.032 BY 0.032 ;
    RESISTANCE 5.72 ;
END VIA4C_DC

VIARULE VIA6A44_DA GENERATE
  LAYER m6 ;
    ENCLOSURE 0.04 -0.008 ;
  LAYER m7 ;
    ENCLOSURE 0 0.032 ;
  LAYER v6 ;
    RECT -0.0280 -0.0300 0.0280 0.0300 ;
    SPACING 0.056 BY 0.06 ;
    RESISTANCE 5.72 ;
END VIA6A44_DA

VIARULE VIA6A44_DB GENERATE
  LAYER m6 ;
    ENCLOSURE 0.016 -0.008 ;
  LAYER m7 ;
    ENCLOSURE 0 0.042 ;
  LAYER v6 ;
    RECT -0.0280 -0.0300 0.0280 0.0300 ;
    SPACING 0.056 BY 0.06 ;
    RESISTANCE 5.72 ;
END VIA6A44_DB

VIARULE VIA6A44_DC GENERATE
  LAYER m6 ;
    ENCLOSURE 0.04 -0.008 ;
  LAYER m7 ;
    ENCLOSURE 0 0.042 ;
  LAYER v6 ;
    RECT -0.0280 -0.0300 0.0280 0.0300 ;
    SPACING 0.056 BY 0.06 ;
    RESISTANCE 5.72 ;
END VIA6A44_DC

VIARULE VIA7F_168 GENERATE
  LAYER m7 ;
    ENCLOSURE 0.038 0.028 ;
  LAYER m8 ;
    ENCLOSURE 0.028 0 ;
  LAYER v7 ;
    RECT -0.0370 -0.0700 0.0370 0.0700 ;
    SPACING 0.074 BY 0.14 ;
    RESISTANCE 5.72 ;
END VIA7F_168

VIARULE VIA2O_40 GENERATE
  LAYER m2 ;
    ENCLOSURE 0.009 0.004 ;
  LAYER m3 ;
    ENCLOSURE 0 0.024 ;
  LAYER v2 ;
    RECT -0.0420 -0.0160 0.0420 0.0160 ;
    SPACING 0.084 BY 0.032 ;
    RESISTANCE 5.72 ;
END VIA2O_40

VIARULE VIA2O_74 GENERATE
  LAYER m2 ;
    ENCLOSURE 0.009 0.021 ;
  LAYER m3 ;
    ENCLOSURE 0 0.024 ;
  LAYER v2 ;
    RECT -0.0420 -0.0160 0.0420 0.0160 ;
    SPACING 0.084 BY 0.032 ;
    RESISTANCE 5.72 ;
END VIA2O_74

VIARULE VIA5O GENERATE
  LAYER m5 ;
    ENCLOSURE -0.002 0.012 ;
  LAYER m6 ;
    ENCLOSURE 0.022 0 ;
  LAYER v5 ;
    RECT -0.0160 -0.0300 0.0160 0.0300 ;
    SPACING 0.032 BY 0.06 ;
    RESISTANCE 5.72 ;
END VIA5O

VIARULE VIA6F_40 GENERATE
  LAYER m6 ;
    ENCLOSURE 0.016 -0.01 ;
  LAYER m7 ;
    ENCLOSURE 0 0.032 ;
  LAYER v6 ;
    RECT -0.0840 -0.0300 0.0840 0.0300 ;
    SPACING 0.168 BY 0.06 ;
    RESISTANCE 5.72 ;
END VIA6F_40

VIARULE VIA6F_60 GENERATE
  LAYER m6 ;
    ENCLOSURE 0.016 0 ;
  LAYER m7 ;
    ENCLOSURE 0 0.032 ;
  LAYER v6 ;
    RECT -0.0840 -0.0300 0.0840 0.0300 ;
    SPACING 0.168 BY 0.06 ;
    RESISTANCE 5.72 ;
END VIA6F_60

VIARULE VIA6F_108 GENERATE
  LAYER m6 ;
    ENCLOSURE 0.016 0.024 ;
  LAYER m7 ;
    ENCLOSURE 0 0.032 ;
  LAYER v6 ;
    RECT -0.0840 -0.0300 0.0840 0.0300 ;
    SPACING 0.168 BY 0.06 ;
    RESISTANCE 5.72 ;
END VIA6F_108

VIARULE VIA6A60 GENERATE
  LAYER m6 ;
    ENCLOSURE 0.016 0 ;
  LAYER m7 ;
    ENCLOSURE 0 0.032 ;
  LAYER v6 ;
    RECT -0.0280 -0.0300 0.0280 0.0300 ;
    SPACING 0.056 BY 0.06 ;
    RESISTANCE 5.72 ;
END VIA6A60

VIARULE VIA6A108 GENERATE
  LAYER m6 ;
    ENCLOSURE 0.016 0.024 ;
  LAYER m7 ;
    ENCLOSURE 0 0.032 ;
  LAYER v6 ;
    RECT -0.0280 -0.0300 0.0280 0.0300 ;
    SPACING 0.056 BY 0.06 ;
    RESISTANCE 5.72 ;
END VIA6A108

VIARULE VIA7A_168 GENERATE
  LAYER m7 ;
    ENCLOSURE 0.047 0.028 ;
  LAYER m8 ;
    ENCLOSURE 0.028 0 ;
  LAYER v7 ;
    RECT -0.0370 -0.0630 0.0370 0.0630 ;
    SPACING 0.074 BY 0.126 ;
    RESISTANCE 5.72 ;
END VIA7A_168

VIARULE VIA4C_28 GENERATE
  LAYER m4 ;
    ENCLOSURE 0.009 -0.002 ;
  LAYER m5 ;
    ENCLOSURE 0 0.024 ;
  LAYER v4 ;
    RECT -0.0160 -0.0160 0.0160 0.0160 ;
    SPACING 0.032 BY 0.032 ;
    RESISTANCE 5.72 ;
END VIA4C_28

VIARULE VIA3A_32 GENERATE
  LAYER m3 ;
    ENCLOSURE 0 0.009 ;
  LAYER m4 ;
    ENCLOSURE 0.024 0 ;
  LAYER v3 ;
    RECT -0.0160 -0.0140 0.0160 0.0140 ;
    SPACING 0.032 BY 0.028 ;
    RESISTANCE 5.72 ;
END VIA3A_32

VIARULE VIA5B_DA GENERATE
  LAYER m5 ;
    ENCLOSURE -0.002 0.017 ;
  LAYER m6 ;
    ENCLOSURE 0.022 0 ;
  LAYER v5 ;
    RECT -0.0160 -0.0220 0.0160 0.0220 ;
    SPACING 0.032 BY 0.044 ;
    RESISTANCE 5.72 ;
END VIA5B_DA

VIARULE VIA5B_DB GENERATE
  LAYER m5 ;
    ENCLOSURE -0.002 0.012 ;
  LAYER m6 ;
    ENCLOSURE 0.04 0 ;
  LAYER v5 ;
    RECT -0.0160 -0.0220 0.0160 0.0220 ;
    SPACING 0.032 BY 0.044 ;
    RESISTANCE 5.72 ;
END VIA5B_DB

VIARULE VIA5B_DC GENERATE
  LAYER m5 ;
    ENCLOSURE -0.002 0.017 ;
  LAYER m6 ;
    ENCLOSURE 0.04 0 ;
  LAYER v5 ;
    RECT -0.0160 -0.0220 0.0160 0.0220 ;
    SPACING 0.032 BY 0.044 ;
    RESISTANCE 5.72 ;
END VIA5B_DC

VIARULE VIA5B_44_DA GENERATE
  LAYER m5 ;
    ENCLOSURE 0 0.017 ;
  LAYER m6 ;
    ENCLOSURE 0.022 0 ;
  LAYER v5 ;
    RECT -0.0160 -0.0220 0.0160 0.0220 ;
    SPACING 0.032 BY 0.044 ;
    RESISTANCE 5.72 ;
END VIA5B_44_DA

VIARULE VIA5B_44_DB GENERATE
  LAYER m5 ;
    ENCLOSURE 0 0.012 ;
  LAYER m6 ;
    ENCLOSURE 0.04 0 ;
  LAYER v5 ;
    RECT -0.0160 -0.0220 0.0160 0.0220 ;
    SPACING 0.032 BY 0.044 ;
    RESISTANCE 5.72 ;
END VIA5B_44_DB

VIARULE VIA5B_44_DC GENERATE
  LAYER m5 ;
    ENCLOSURE 0 0.017 ;
  LAYER m6 ;
    ENCLOSURE 0.04 0 ;
  LAYER v5 ;
    RECT -0.0160 -0.0220 0.0160 0.0220 ;
    SPACING 0.032 BY 0.044 ;
    RESISTANCE 5.72 ;
END VIA5B_44_DC

VIARULE VIA7F_DA GENERATE
  LAYER m7 ;
    ENCLOSURE -0.009 0.032 ;
  LAYER m8 ;
    ENCLOSURE 0.028 0 ;
  LAYER v7 ;
    RECT -0.0370 -0.0700 0.0370 0.0700 ;
    SPACING 0.074 BY 0.14 ;
    RESISTANCE 5.72 ;
END VIA7F_DA

VIARULE VIA7F_DB GENERATE
  LAYER m7 ;
    ENCLOSURE -0.009 0.028 ;
  LAYER m8 ;
    ENCLOSURE 0.032 0 ;
  LAYER v7 ;
    RECT -0.0370 -0.0700 0.0370 0.0700 ;
    SPACING 0.074 BY 0.14 ;
    RESISTANCE 5.72 ;
END VIA7F_DB

VIARULE VIA1HL GENERATE
  LAYER m1 ;
    ENCLOSURE 0.003 0.007 ;
  LAYER m2 ;
    ENCLOSURE 0.024 0 ;
  LAYER v1 ;
    RECT -0.0180 -0.0240 0.0180 0.0240 ;
    SPACING 0.036 BY 0.048 ;
    RESISTANCE 5.72 ;
END VIA1HL

VIARULE VIA6E GENERATE
  LAYER m6 ;
    ENCLOSURE 0.016 -0.01 ;
  LAYER m7 ;
    ENCLOSURE 0 0.032 ;
  LAYER v6 ;
    RECT -0.0750 -0.0300 0.0750 0.0300 ;
    SPACING 0.15 BY 0.06 ;
    RESISTANCE 5.72 ;
END VIA6E

VIARULE VIA6E_44 GENERATE
  LAYER m6 ;
    ENCLOSURE 0.016 -0.008 ;
  LAYER m7 ;
    ENCLOSURE 0 0.032 ;
  LAYER v6 ;
    RECT -0.0750 -0.0300 0.0750 0.0300 ;
    SPACING 0.15 BY 0.06 ;
    RESISTANCE 5.72 ;
END VIA6E_44

VIARULE VIA6E_90 GENERATE
  LAYER m6 ;
    ENCLOSURE 0.016 0.015 ;
  LAYER m7 ;
    ENCLOSURE 0 0.032 ;
  LAYER v6 ;
    RECT -0.0750 -0.0300 0.0750 0.0300 ;
    SPACING 0.15 BY 0.06 ;
    RESISTANCE 5.72 ;
END VIA6E_90

VIARULE VIA6E_108 GENERATE
  LAYER m6 ;
    ENCLOSURE 0.016 0.024 ;
  LAYER m7 ;
    ENCLOSURE 0 0.032 ;
  LAYER v6 ;
    RECT -0.0750 -0.0300 0.0750 0.0300 ;
    SPACING 0.15 BY 0.06 ;
    RESISTANCE 5.72 ;
END VIA6E_108

VIARULE VIA7F_DC GENERATE
  LAYER m7 ;
    ENCLOSURE -0.009 0.032 ;
  LAYER m8 ;
    ENCLOSURE 0.032 0 ;
  LAYER v7 ;
    RECT -0.0370 -0.0700 0.0370 0.0700 ;
    SPACING 0.074 BY 0.14 ;
    RESISTANCE 5.72 ;
END VIA7F_DC

VIARULE VIA1HA GENERATE
  LAYER m1 ;
    ENCLOSURE 0.003 0.007 ;
  LAYER m2 ;
    ENCLOSURE 0.024 0 ;
  LAYER v1 ;
    RECT -0.0180 -0.0180 0.0180 0.0180 ;
    SPACING 0.036 BY 0.036 ;
    RESISTANCE 5.72 ;
END VIA1HA

VIARULE VIA1HK GENERATE
  LAYER m1 ;
    ENCLOSURE 0.003 0.017 ;
  LAYER m2 ;
    ENCLOSURE 0.024 0 ;
  LAYER v1 ;
    RECT -0.0180 -0.0350 0.0180 0.0350 ;
    SPACING 0.036 BY 0.07 ;
    RESISTANCE 5.72 ;
END VIA1HK

VIARULE VIA1S GENERATE
  LAYER m1 ;
    ENCLOSURE 0.003 0.007 ;
  LAYER m2 ;
    ENCLOSURE 0.024 0 ;
  LAYER v1 ;
    RECT -0.0180 -0.0380 0.0180 0.0380 ;
    SPACING 0.036 BY 0.076 ;
    RESISTANCE 5.72 ;
END VIA1S

VIARULE TV1A GENERATE
  LAYER tm1 ;
    DIRECTION HORIZONTAL ;
    OVERHANG 3 ;
  LAYER c4 ;
    DIRECTION VERTICAL ;
    OVERHANG 3 ;
  LAYER tv1 ;
    RECT -3.0000 -15.0000 3.0000 15.0000 ;
    SPACING 58 BY 82 ;
    RESISTANCE 5.72 ;
END TV1A

VIARULE VIA9A_R GENERATE
  LAYER m9 ;
    ENCLOSURE 0.14 0.14 ;
  LAYER tm1 ;
    ENCLOSURE 3 3 ;
  LAYER v9 ;
    RECT -0.9250 -0.4000 0.9250 0.4000 ;
    SPACING 3.85 BY 2.8 ;
    RESISTANCE 5.72 ;
END VIA9A_R

VIARULE VIA9B_R GENERATE
  LAYER m9 ;
    ENCLOSURE 0.14 0.14 ;
  LAYER tm1 ;
    ENCLOSURE 3 3 ;
  LAYER v9 ;
    RECT -3.7000 -0.4000 3.7000 0.4000 ;
    SPACING 9.4 BY 2.8 ;
    RESISTANCE 5.72 ;
END VIA9B_R

VIARULE VIA9C_R GENERATE
  LAYER m9 ;
    ENCLOSURE 0.14 0.14 ;
  LAYER tm1 ;
    ENCLOSURE 3 3 ;
  LAYER v9 ;
    RECT -1.8500 -0.4000 1.8500 0.4000 ;
    SPACING 5.7 BY 2.8 ;
    RESISTANCE 5.72 ;
END VIA9C_R

SPACING
  SAMENET vcn vcn 0 STACK ;
  SAMENET vcn v0 0 STACK ;
  SAMENET v0 v0 0 STACK ;
  SAMENET v0 v1 0 STACK ;
  SAMENET v1 v1 0 STACK ;
  SAMENET v1 v2 0 STACK ;
  SAMENET v2 v2 0 STACK ;
  SAMENET v2 v3 0 STACK ;
  SAMENET v3 v3 0 STACK ;
  SAMENET v3 v4 0 STACK ;
  SAMENET v4 v4 0 STACK ;
  SAMENET v4 v5 0 STACK ;
  SAMENET v5 v5 0 STACK ;
  SAMENET v5 v6 0 STACK ;
  SAMENET v6 v6 0 STACK ;
  SAMENET v6 v7 0 STACK ;
  SAMENET v7 v7 0 STACK ;
END SPACING

SITE unit
  CLASS CORE ;
  SYMMETRY X Y ;
  SIZE 0.07 BY 0.399 ;
END unit

SITE core
  CLASS CORE ;
  SYMMETRY X Y ;
  SIZE 0.07 BY 0.399 ;
END core

SITE bonuscore
  CLASS CORE ;
  SYMMETRY X Y ;
  SIZE 0.28 BY 0.399 ;
END bonuscore

SITE core2h
  CLASS CORE ;
  SYMMETRY X Y ;
  SIZE 0.07 BY 0.798 ;
END core2h

SITE core84
  CLASS CORE ;
  SYMMETRY X Y ;
  SIZE 0.084 BY 0.399 ;
END core84

SITE bonuscore84
  CLASS CORE ;
  SYMMETRY X Y ;
  SIZE 0.336 BY 0.399 ;
END bonuscore84

SITE core2h84
  CLASS CORE ;
  SYMMETRY X Y ;
  SIZE 0.084 BY 0.798 ;
END core2h84
  
END LIBRARY
